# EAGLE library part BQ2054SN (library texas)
CHARGE MANAGEMENT IC

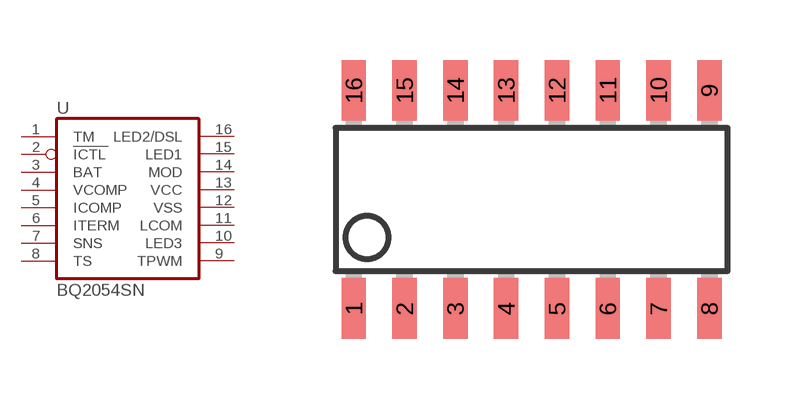
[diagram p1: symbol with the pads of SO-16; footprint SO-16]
Designator prefix U

## BQ2054SN (MF: TEXAS INSTRUMENT CONNECTORS; MPN: BQ2054SN; OC_FARNELL: unknown; OC_NEWARK: 74C7583)  [SO-16]
1  TM  in
2  ICTL  out
3  BAT  in
4  VCOMP  in
5  ICOMP  in
6  ITERM  in
7  SNS  in
8  TS  in
9  TPWM  in
10  LED3  hiz
11  LCOM  out
12  VSS  pwr
13  VCC  pwr
14  MOD  out
15  LED1  hiz
16  LED2/DSL  hiz

## Footprint SO-16 (pad centres in mm)
Small Outline Integrated Circuit
smd 0.61 x 1.524: 1 -4.445,-2.794; 2 -3.175,-2.794; 3 -1.905,-2.794; 4 -0.635,-2.794; 5 0.635,-2.794; 6 1.905,-2.794; 7 3.175,-2.794; 8 4.445,-2.794; 9 4.445,2.667; 10 3.175,2.667; 11 1.905,2.667; 12 0.635,2.667; 13 -0.635,2.667; 14 -1.905,2.667; 15 -3.175,2.667; 16 -4.445,2.667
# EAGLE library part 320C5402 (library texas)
DSP DEVICE

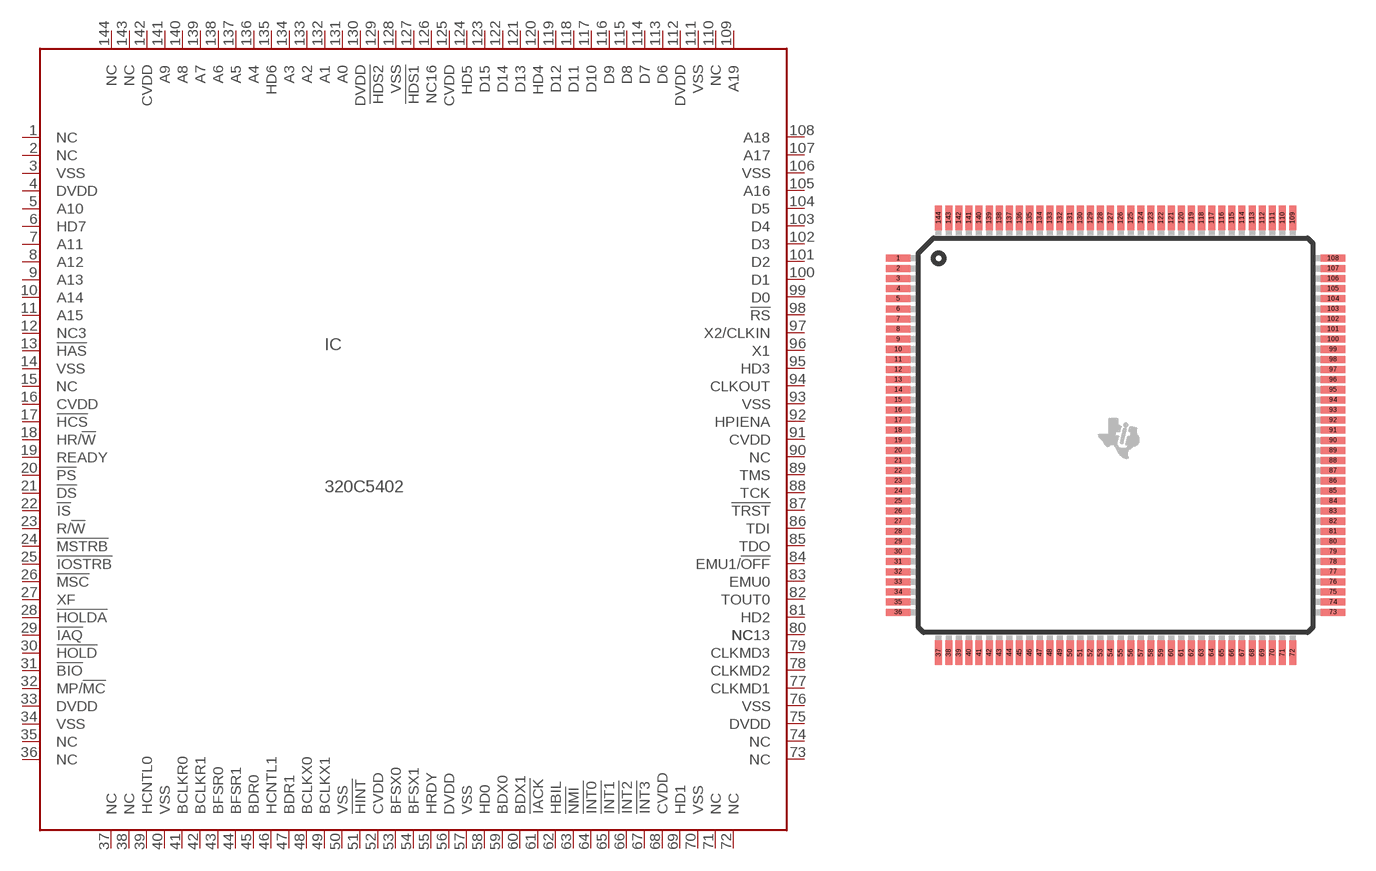
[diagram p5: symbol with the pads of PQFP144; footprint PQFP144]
Designator prefix IC

## 320C5402 (OC_FARNELL: unknown; OC_NEWARK: unknown)  [PQFP144]
1  NC1  nc
2  NC2  nc
3  VSS  pwr
4  DVDD  pwr
5  A10  in
6  HD7  in
7  A11  in
8  A12  in
9  A13  in
10  A14  in
11  A15  in
12  NC3  nc
13  !HAS  in
14  VSS  pwr
15  NC4  nc
16  CVDD  pwr
17  !HCS  in
18  HR/!W  in
19  READY  in
20  !PS  in
21  !DS  in
22  !IS  in
23  R/!W  in
24  !MSTRB  in
25  !IOSTRB  in
26  !MSC  in
27  XF  in
28  !HOLDA  in
29  !IAQ  in
30  !HOLD  in
31  !BIO  in
32  MP/!MC  in
33  DVDD  pwr
34  VSS  pwr
35  NC5  nc
36  NC6  nc
37  NC7  nc
38  NC8  nc
39  HCNTL0  in
40  VSS  pwr
41  BCLKR0  in
42  BCLKR1  in
43  BFSR0  in
44  BFSR1  in
45  BDR0  in
46  HCNTL1  in
47  BDR1  in
48  BCLKX0  in
49  BCLKX1  in
50  VSS  pwr
51  !HINT  in
52  CVDD  pwr
53  BFSX0  in
54  BFSX1  in
55  HRDY  in
56  DVDD  pwr
57  VSS  pwr
58  HD0  in
59  BDX0  in
60  BDX1  in
61  !IACK  in
62  HBIL  in
63  !NMI  in
64  !INT0  in
65  !INT1  in
66  !INT2  in
67  !INT3  in
68  CVDD  pwr
69  HD1  in
70  VSS  pwr
71  NC9  nc
72  NC10  nc
73  NC11  nc
74  NC12  nc
75  DVDD  pwr
76  VSS  pwr
77  CLKMD1  in
78  CLKMD2  in
79  CLKMD3  in
80  NC13  nc
81  HD2  in
82  TOUT0  in
83  EMU0  in
84  EMU1/!OFF  in
85  TDO  in
86  TDI  in
87  !TRST  in
88  TCK  in
89  TMS  in
90  NC14  nc
91  CVDD  pwr
92  HPIENA  in
93  VSS  pwr
94  CLKOUT  in
95  HD3  in
96  X1  in
97  X2/CLKIN  in
98  !RS  in
99  D0  in
100  D1  in
101  D2  in
102  D3  in
103  D4  in
104  D5  in
105  A16  in
106  VSS  pwr
107  A17  in
108  A18  in
109  A19  in
110  NC15  nc
111  VSS  pwr
112  DVDD  pwr
113  D6  in
114  D7  in
115  D8  in
116  D9  in
117  D10  in
118  D11  in
119  D12  in
120  HD4  in
121  D13  in
122  D14  in
123  D15  in
124  HD5  in
125  CVDD  pwr
126  NC16  nc
127  !HDS1  in
128  VSS  pwr
129  !HDS2  in
130  DVDD  pwr
131  A0  in
132  A1  in
133  A2  in
134  A3  in
135  HD6  in
136  A4  in
137  A5  in
138  A6  in
139  A7  in
140  A8  in
141  A9  in
142  CVDD  pwr
143  NC17  nc
144  NC18  nc

## Footprint PQFP144 (pad centres in mm)
Platic Quad Flat Package PGE (S-PQFP-G144)
smd 1.2 x 0.35: 1 -10.75,8.75; 2 -10.75,8.25; 3 -10.75,7.75; 4 -10.75,7.25; 5 -10.75,6.75; 6 -10.75,6.25; 7 -10.75,5.75; 8 -10.75,5.25; 9 -10.75,4.75; 10 -10.75,4.25; 11 -10.75,3.75; 12 -10.75,3.25; 13 -10.75,2.75; 14 -10.75,2.25; 15 -10.75,1.75; 16 -10.75,1.25; 17 -10.75,0.75; 18 -10.75,0.25; 19 -10.75,-0.25; 20 -10.75,-0.75; 21 -10.75,-1.25; 22 -10.75,-1.75; 23 -10.75,-2.25; 24 -10.75,-2.75; 25 -10.75,-3.25; 26 -10.75,-3.75; 27 -10.75,-4.25; 28 -10.75,-4.75; 29 -10.75,-5.25; 30 -10.75,-5.75; 31 -10.75,-6.25; 32 -10.75,-6.75; 33 -10.75,-7.25; 34 -10.75,-7.75; 35 -10.75,-8.25; 36 -10.75,-8.75; 73 10.75,-8.75; 74 10.75,-8.25; 75 10.75,-7.75; 76 10.75,-7.25; 77 10.75,-6.75; 78 10.75,-6.25; 79 10.75,-5.75; 80 10.75,-5.25; 81 10.75,-4.75; 82 10.75,-4.25; 83 10.75,-3.75; 84 10.75,-3.25; 85 10.75,-2.75; 86 10.75,-2.25; 87 10.75,-1.75; 88 10.75,-1.25; 89 10.75,-0.75; 90 10.75,-0.25; 91 10.75,0.25; 92 10.75,0.75; 93 10.75,1.25; 94 10.75,1.75; 95 10.75,2.25; 96 10.75,2.75; 97 10.75,3.25; 98 10.75,3.75; 99 10.75,4.25; 100 10.75,4.75; 101 10.75,5.25; 102 10.75,5.75; 103 10.75,6.25; 104 10.75,6.75; 105 10.75,7.25; 106 10.75,7.75; 107 10.75,8.25; 108 10.75,8.75
smd 0.35 x 1.2: 37 -8.75,-10.75; 38 -8.25,-10.75; 39 -7.75,-10.75; 40 -7.25,-10.75; 41 -6.75,-10.75; 42 -6.25,-10.75; 43 -5.75,-10.75; 44 -5.25,-10.75; 45 -4.75,-10.75; 46 -4.25,-10.75; 47 -3.75,-10.75; 48 -3.25,-10.75; 49 -2.75,-10.75; 50 -2.25,-10.75; 51 -1.75,-10.75; 52 -1.25,-10.75; 53 -0.75,-10.75; 54 -0.25,-10.75; 55 0.25,-10.75; 56 0.75,-10.75; 57 1.25,-10.75; 58 1.75,-10.75; 59 2.25,-10.75; 60 2.75,-10.75; 61 3.25,-10.75; 62 3.75,-10.75; 63 4.25,-10.75; 64 4.75,-10.75; 65 5.25,-10.75; 66 5.75,-10.75; 67 6.25,-10.75; 68 6.75,-10.75; 69 7.25,-10.75; 70 7.75,-10.75; 71 8.25,-10.75; 72 8.75,-10.75; 109 8.75,10.75; 110 8.25,10.75; 111 7.75,10.75; 112 7.25,10.75; 113 6.75,10.75; 114 6.25,10.75; 115 5.75,10.75; 116 5.25,10.75; 117 4.75,10.75; 118 4.25,10.75; 119 3.75,10.75; 120 3.25,10.75; 121 2.75,10.75; 122 2.25,10.75; 123 1.75,10.75; 124 1.25,10.75; 125 0.75,10.75; 126 0.25,10.75; 127 -0.25,10.75; 128 -0.75,10.75; 129 -1.25,10.75; 130 -1.75,10.75; 131 -2.25,10.75; 132 -2.75,10.75; 133 -3.25,10.75; 134 -3.75,10.75; 135 -4.25,10.75; 136 -4.75,10.75; 137 -5.25,10.75; 138 -5.75,10.75; 139 -6.25,10.75; 140 -6.75,10.75; 141 -7.25,10.75; 142 -7.75,10.75; 143 -8.25,10.75; 144 -8.75,10.75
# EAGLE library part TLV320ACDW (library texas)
DSP DEVICE

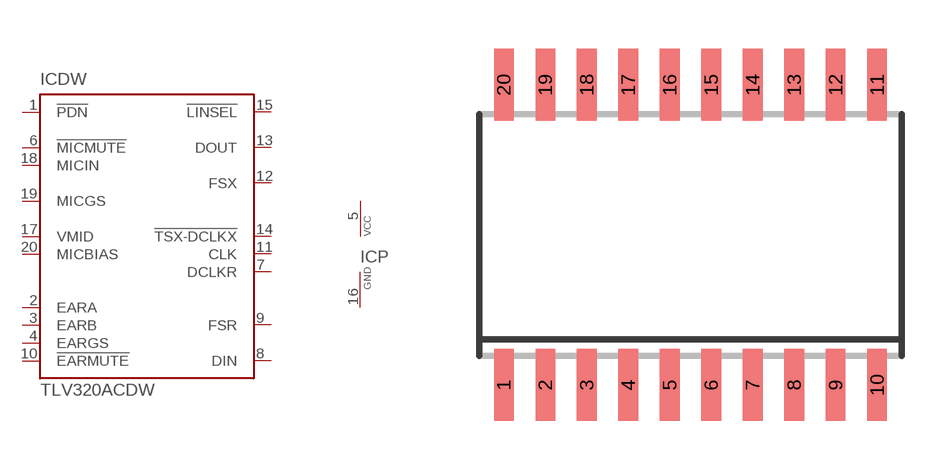
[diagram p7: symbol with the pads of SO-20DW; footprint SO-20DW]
Designator prefix IC; gates DW=TLV320AC P=VCCGND

## TLV320ACDW (OC_FARNELL: unknown; OC_NEWARK: unknown)  [SO-20DW]
1  DW:!PDN  in
2  DW:EARA  out
3  DW:EARB  out
4  DW:EARGS  in
5  P:VCC  pwr
6  DW:!MICMUTE  in
7  DW:DCLKR  in
8  DW:DIN  in
9  DW:FSR  in
10  DW:!EARMUTE  in
11  DW:CLK  in
12  DW:FSX  in
13  DW:DOUT  out
14  DW:!TSX-DCLKX
15  DW:!LINSEL  in
16  P:GND  pwr
17  DW:VMID  out
18  DW:MICIN  in
19  DW:MICGS  out
20  DW:MICBIAS  out

## Footprint SO-20DW (pad centres in mm)
Small Outline Integrated Circuit wide
smd 0.6 x 2.2: 1 -5.715,-4.6; 2 -4.445,-4.6; 3 -3.175,-4.6; 4 -1.905,-4.6; 5 -0.635,-4.6; 6 0.635,-4.6; 7 1.905,-4.6; 8 3.175,-4.6; 9 4.445,-4.6; 10 5.715,-4.6; 11 5.715,4.6; 12 4.445,4.6; 13 3.175,4.6; 14 1.905,4.6; 15 0.635,4.6; 16 -0.635,4.6; 17 -1.905,4.6; 18 -3.175,4.6; 19 -4.445,4.6; 20 -5.715,4.6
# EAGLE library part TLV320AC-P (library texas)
DSP DEVICE

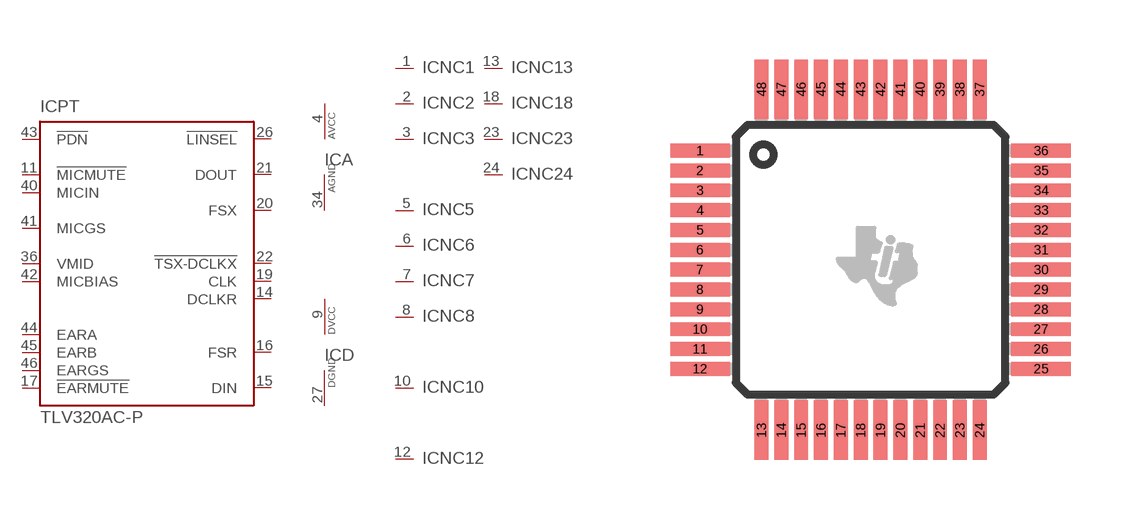
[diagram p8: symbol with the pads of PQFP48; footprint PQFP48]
Designator prefix IC; gates PT=TLV320AC A=AVCCGND D=DVCCGND NC1=NC NC2=NC NC3=NC NC5=NC NC6=NC NC7=NC NC8=NC NC10=NC NC12=NC NC13=NC NC18=NC NC23=NC NC24=NC NC25=NC NC28=NC NC29=NC NC30=NC NC31=NC NC32=NC NC33=NC NC35=NC NC37=NC NC38=NC NC39=NC NC47=NC NC48=NC

## TLV320AC-P (OC_FARNELL: unknown; OC_NEWARK: unknown)  [PQFP48]
1  NC1:NC  nc
2  NC2:NC  nc
3  NC3:NC  nc
4  A:AVCC  pwr
5  NC5:NC  nc
6  NC6:NC  nc
7  NC7:NC  nc
8  NC8:NC  nc
9  D:DVCC  pwr
10  NC10:NC  nc
11  PT:!MICMUTE  in
12  NC12:NC  nc
13  NC13:NC  nc
14  PT:DCLKR  in
15  PT:DIN  in
16  PT:FSR  in
17  PT:!EARMUTE  in
18  NC18:NC  nc
19  PT:CLK  in
20  PT:FSX  in
21  PT:DOUT  out
22  PT:!TSX-DCLKX
23  NC23:NC  nc
24  NC24:NC  nc
25  NC25:NC  nc
26  PT:!LINSEL  in
27  D:DGND  pwr
28  NC28:NC  nc
29  NC29:NC  nc
30  NC30:NC  nc
31  NC31:NC  nc
32  NC32:NC  nc
33  NC33:NC  nc
34  A:AGND  pwr
35  NC35:NC  nc
36  PT:VMID  out
37  NC37:NC  nc
38  NC38:NC  nc
39  NC39:NC  nc
40  PT:MICIN  in
41  PT:MICGS  out
42  PT:MICBIAS  out
43  PT:!PDN  in
44  PT:EARA  out
45  PT:EARB  out
46  PT:EARGS  in
47  NC47:NC  nc
48  NC48:NC  nc

## Footprint PQFP48 (pad centres in mm)
Platic Quad Flat Package
smd 1.5 x 0.35: 1 -4.3,2.75; 2 -4.3,2.25; 3 -4.3,1.75; 4 -4.3,1.25; 5 -4.3,0.75; 6 -4.3,0.25; 7 -4.3,-0.25; 8 -4.3,-0.75; 9 -4.3,-1.25; 10 -4.3,-1.75; 11 -4.3,-2.25; 12 -4.3,-2.75; 25 4.3,-2.75; 26 4.3,-2.25; 27 4.3,-1.75; 28 4.3,-1.25; 29 4.3,-0.75; 30 4.3,-0.25; 31 4.3,0.25; 32 4.3,0.75; 33 4.3,1.25; 34 4.3,1.75; 35 4.3,2.25; 36 4.3,2.75
smd 0.35 x 1.5: 13 -2.75,-4.3; 14 -2.25,-4.3; 15 -1.75,-4.3; 16 -1.25,-4.3; 17 -0.75,-4.3; 18 -0.25,-4.3; 19 0.25,-4.3; 20 0.75,-4.3; 21 1.25,-4.3; 22 1.75,-4.3; 23 2.25,-4.3; 24 2.75,-4.3; 37 2.75,4.3; 38 2.25,4.3; 39 1.75,4.3; 40 1.25,4.3; 41 0.75,4.3; 42 0.25,4.3; 43 -0.25,4.3; 44 -0.75,4.3; 45 -1.25,4.3; 46 -1.75,4.3; 47 -2.25,4.3; 48 -2.75,4.3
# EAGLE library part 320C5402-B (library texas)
DSP DEVICE

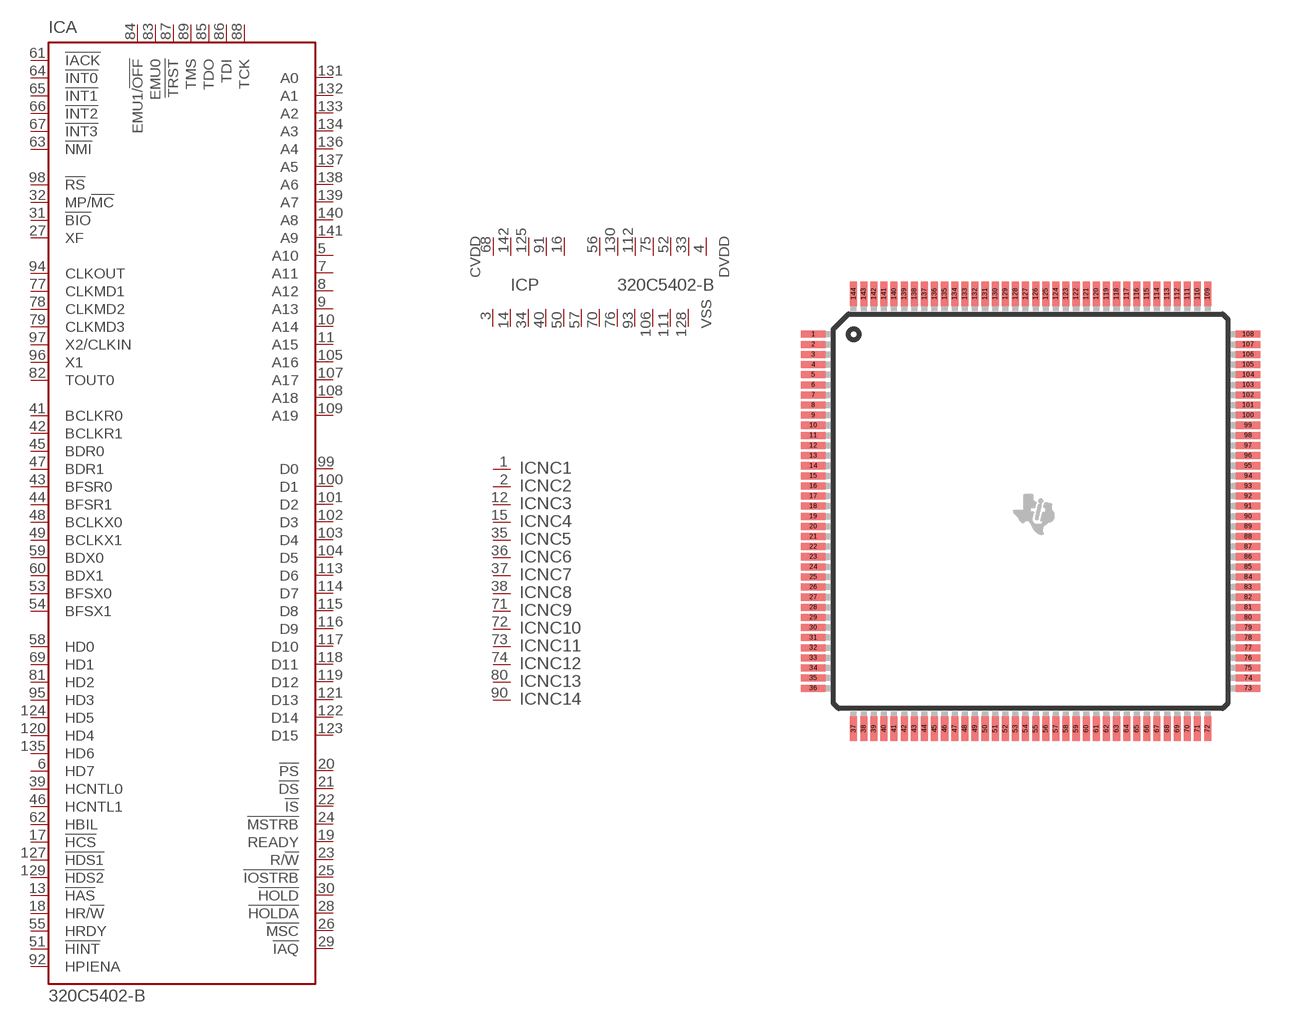
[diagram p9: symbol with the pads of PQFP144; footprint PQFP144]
Designator prefix IC; gates A=320C54-B P=320PWR NC1=NC NC2=NC NC3=NC NC4=NC NC5=NC NC6=NC NC7=NC NC8=NC NC9=NC NC10=NC NC11=NC NC12=NC NC13=NC NC14=NC NC15=NC NC16=NC NC17=NC NC18=NC

## 320C5402-B (OC_FARNELL: unknown; OC_NEWARK: unknown)  [PQFP144]
1  NC1:NC  nc
2  NC2:NC  nc
3  P:VSS  pwr
4  P:DVDD  pwr
5  A:A10  hiz
6  A:HD7  hiz
7  A:A11  hiz
8  A:A12  hiz
9  A:A13  hiz
10  A:A14  hiz
11  A:A15  hiz
12  NC3:NC  nc
13  A:!HAS  in
14  P:VSS  pwr
15  NC4:NC  nc
16  P:CVDD  pwr
17  A:!HCS  in
18  A:HR/!W  in
19  A:READY  in
20  A:!PS  hiz
21  A:!DS  hiz
22  A:!IS  hiz
23  A:R/!W  hiz
24  A:!MSTRB  hiz
25  A:!IOSTRB  hiz
26  A:!MSC  hiz
27  A:XF  hiz
28  A:!HOLDA  hiz
29  A:!IAQ  hiz
30  A:!HOLD  in
31  A:!BIO  in
32  A:MP/!MC  in
33  P:DVDD  pwr
34  P:VSS  pwr
35  NC5:NC  nc
36  NC6:NC  nc
37  NC7:NC  nc
38  NC8:NC  nc
39  A:HCNTL0  in
40  P:VSS  pwr
41  A:BCLKR0  hiz
42  A:BCLKR1  hiz
43  A:BFSR0  hiz
44  A:BFSR1  hiz
45  A:BDR0  in
46  A:HCNTL1  in
47  A:BDR1  in
48  A:BCLKX0  hiz
49  A:BCLKX1  hiz
50  P:VSS  pwr
51  A:!HINT  hiz
52  P:CVDD  pwr
53  A:BFSX0  hiz
54  A:BFSX1  hiz
55  A:HRDY  hiz
56  P:DVDD  pwr
57  P:VSS  pwr
58  A:HD0  hiz
59  A:BDX0  hiz
60  A:BDX1  hiz
61  A:!IACK  hiz
62  A:HBIL  in
63  A:!NMI  in
64  A:!INT0  in
65  A:!INT1  in
66  A:!INT2  in
67  A:!INT3  in
68  P:CVDD  pwr
69  A:HD1  hiz
70  P:VSS  pwr
71  NC9:NC  nc
72  NC10:NC  nc
73  NC11:NC  nc
74  NC12:NC  nc
75  P:DVDD  pwr
76  P:VSS  pwr
77  A:CLKMD1  in
78  A:CLKMD2  in
79  A:CLKMD3  in
80  NC13:NC  nc
81  A:HD2  hiz
82  A:TOUT0  hiz
83  A:EMU0  hiz
84  A:EMU1/!OFF  hiz
85  A:TDO  hiz
86  A:TDI  in
87  A:!TRST  in
88  A:TCK  in
89  A:TMS  in
90  NC14:NC  nc
91  P:CVDD  pwr
92  A:HPIENA  in
93  P:VSS  pwr
94  A:CLKOUT  hiz
95  A:HD3  hiz
96  A:X1  out
97  A:X2/CLKIN  in
98  A:!RS  in
99  A:D0  hiz
100  A:D1  hiz
101  A:D2  hiz
102  A:D3  hiz
103  A:D4  hiz
104  A:D5  hiz
105  A:A16  hiz
106  P:VSS  pwr
107  A:A17  hiz
108  A:A18  hiz
109  A:A19  hiz
110  NC15:NC  nc
111  P:VSS  pwr
112  P:DVDD  pwr
113  A:D6  hiz
114  A:D7  hiz
115  A:D8  hiz
116  A:D9  hiz
117  A:D10  hiz
118  A:D11  hiz
119  A:D12  hiz
120  A:HD4  hiz
121  A:D13  hiz
122  A:D14  hiz
123  A:D15  hiz
124  A:HD5  hiz
125  P:CVDD  pwr
126  NC16:NC  nc
127  A:!HDS1  in
128  P:VSS  pwr
129  A:!HDS2  in
130  P:DVDD  pwr
131  A:A0  hiz
132  A:A1  hiz
133  A:A2  hiz
134  A:A3  hiz
135  A:HD6  hiz
136  A:A4  hiz
137  A:A5  hiz
138  A:A6  hiz
139  A:A7  hiz
140  A:A8  hiz
141  A:A9  hiz
142  P:CVDD  pwr
143  NC17:NC  nc
144  NC18:NC  nc

## Footprint PQFP144 (pad centres in mm)
Platic Quad Flat Package PGE (S-PQFP-G144)
smd 1.2 x 0.35: 1 -10.75,8.75; 2 -10.75,8.25; 3 -10.75,7.75; 4 -10.75,7.25; 5 -10.75,6.75; 6 -10.75,6.25; 7 -10.75,5.75; 8 -10.75,5.25; 9 -10.75,4.75; 10 -10.75,4.25; 11 -10.75,3.75; 12 -10.75,3.25; 13 -10.75,2.75; 14 -10.75,2.25; 15 -10.75,1.75; 16 -10.75,1.25; 17 -10.75,0.75; 18 -10.75,0.25; 19 -10.75,-0.25; 20 -10.75,-0.75; 21 -10.75,-1.25; 22 -10.75,-1.75; 23 -10.75,-2.25; 24 -10.75,-2.75; 25 -10.75,-3.25; 26 -10.75,-3.75; 27 -10.75,-4.25; 28 -10.75,-4.75; 29 -10.75,-5.25; 30 -10.75,-5.75; 31 -10.75,-6.25; 32 -10.75,-6.75; 33 -10.75,-7.25; 34 -10.75,-7.75; 35 -10.75,-8.25; 36 -10.75,-8.75; 73 10.75,-8.75; 74 10.75,-8.25; 75 10.75,-7.75; 76 10.75,-7.25; 77 10.75,-6.75; 78 10.75,-6.25; 79 10.75,-5.75; 80 10.75,-5.25; 81 10.75,-4.75; 82 10.75,-4.25; 83 10.75,-3.75; 84 10.75,-3.25; 85 10.75,-2.75; 86 10.75,-2.25; 87 10.75,-1.75; 88 10.75,-1.25; 89 10.75,-0.75; 90 10.75,-0.25; 91 10.75,0.25; 92 10.75,0.75; 93 10.75,1.25; 94 10.75,1.75; 95 10.75,2.25; 96 10.75,2.75; 97 10.75,3.25; 98 10.75,3.75; 99 10.75,4.25; 100 10.75,4.75; 101 10.75,5.25; 102 10.75,5.75; 103 10.75,6.25; 104 10.75,6.75; 105 10.75,7.25; 106 10.75,7.75; 107 10.75,8.25; 108 10.75,8.75
smd 0.35 x 1.2: 37 -8.75,-10.75; 38 -8.25,-10.75; 39 -7.75,-10.75; 40 -7.25,-10.75; 41 -6.75,-10.75; 42 -6.25,-10.75; 43 -5.75,-10.75; 44 -5.25,-10.75; 45 -4.75,-10.75; 46 -4.25,-10.75; 47 -3.75,-10.75; 48 -3.25,-10.75; 49 -2.75,-10.75; 50 -2.25,-10.75; 51 -1.75,-10.75; 52 -1.25,-10.75; 53 -0.75,-10.75; 54 -0.25,-10.75; 55 0.25,-10.75; 56 0.75,-10.75; 57 1.25,-10.75; 58 1.75,-10.75; 59 2.25,-10.75; 60 2.75,-10.75; 61 3.25,-10.75; 62 3.75,-10.75; 63 4.25,-10.75; 64 4.75,-10.75; 65 5.25,-10.75; 66 5.75,-10.75; 67 6.25,-10.75; 68 6.75,-10.75; 69 7.25,-10.75; 70 7.75,-10.75; 71 8.25,-10.75; 72 8.75,-10.75; 109 8.75,10.75; 110 8.25,10.75; 111 7.75,10.75; 112 7.25,10.75; 113 6.75,10.75; 114 6.25,10.75; 115 5.75,10.75; 116 5.25,10.75; 117 4.75,10.75; 118 4.25,10.75; 119 3.75,10.75; 120 3.25,10.75; 121 2.75,10.75; 122 2.25,10.75; 123 1.75,10.75; 124 1.25,10.75; 125 0.75,10.75; 126 0.25,10.75; 127 -0.25,10.75; 128 -0.75,10.75; 129 -1.25,10.75; 130 -1.75,10.75; 131 -2.25,10.75; 132 -2.75,10.75; 133 -3.25,10.75; 134 -3.75,10.75; 135 -4.25,10.75; 136 -4.75,10.75; 137 -5.25,10.75; 138 -5.75,10.75; 139 -6.25,10.75; 140 -6.75,10.75; 141 -7.25,10.75; 142 -7.75,10.75; 143 -8.25,10.75; 144 -8.75,10.75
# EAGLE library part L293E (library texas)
TI DEVICE

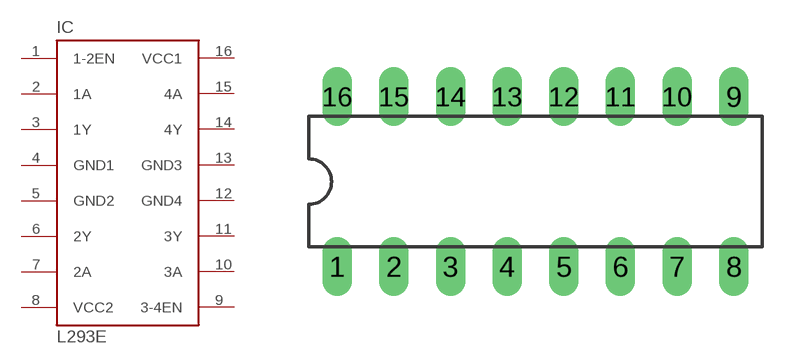
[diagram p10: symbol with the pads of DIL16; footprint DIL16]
Designator prefix IC

## L293E (MF: Arrow Electronics; MPN: L293E; OC_FARNELL: 1467711; OC_NEWARK: 89K0732)  [DIL16]
1  1-2EN  in
2  1A  in
3  1Y  out
4  GND1  pwr
5  GND2  pwr
6  2Y  out
7  2A  in
8  VCC2  pwr
9  3-4EN  in
10  3A  in
11  3Y  out
12  GND4  pwr
13  GND3  pwr
14  4Y  out
15  4A  in
16  VCC1  pwr

## Footprint DIL16 (pad centres in mm)
Dual In Line Package
drill 0.813 long: 1 -8.89,-3.81; 2 -6.35,-3.81; 3 -3.81,-3.81; 4 -1.27,-3.81; 5 1.27,-3.81; 6 3.81,-3.81; 7 6.35,-3.81; 8 8.89,-3.81; 9 8.89,3.81; 10 6.35,3.81; 11 3.81,3.81; 12 1.27,3.81; 13 -1.27,3.81; 14 -3.81,3.81; 15 -6.35,3.81; 16 -8.89,3.81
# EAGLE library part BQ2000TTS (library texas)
CHARGE MANAGEMENT IC

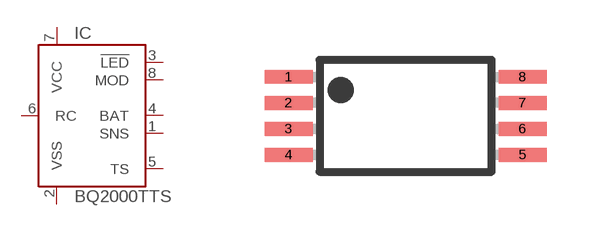
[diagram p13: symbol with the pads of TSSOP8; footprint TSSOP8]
Designator prefix IC

## BQ2000TTS (OC_FARNELL: unknown; OC_NEWARK: unknown)  [TSSOP8]
1  SNS  in
2  VSS  pwr
3  !LED  out
4  BAT  in
5  TS  in
6  RC  in
7  VCC  in
8  MOD  out

## Footprint TSSOP8 (pad centres in mm)
Plastic Small Outline
smd 1.2 x 0.35: 1 -2.925,0.975; 2 -2.925,0.325; 3 -2.925,-0.325; 4 -2.925,-0.975; 5 2.925,-0.975; 6 2.925,-0.325; 7 2.925,0.325; 8 2.925,0.975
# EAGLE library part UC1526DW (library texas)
PULSE WIDTH MODULATOR

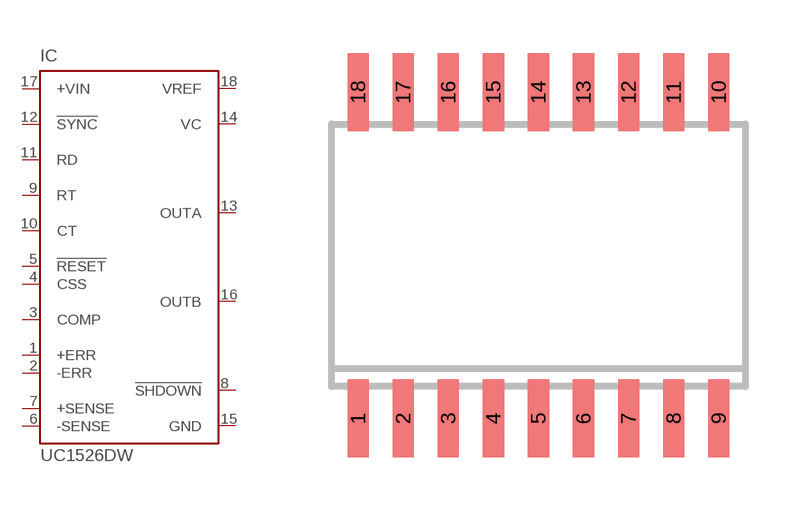
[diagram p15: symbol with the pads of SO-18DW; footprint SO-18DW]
Designator prefix IC

## UC1526DW (OC_FARNELL: unknown; OC_NEWARK: unknown)  [SO-18DW]
1  +ERR  in
2  -ERR  in
3  COMP  pas
4  CSS  in
5  !RESET  in
6  -SENSE  in
7  +SENSE  in
8  !SHDOWN  out
9  RT  pas
10  CT  pas
11  RD  pas
12  !SYNC  in
13  OUTA  out
14  VC  in
15  GND  pwr
16  OUTB  out
17  +VIN  in
18  VREF  out

## Footprint SO-18DW (pad centres in mm)
Small Outline Integrated Circuit wide
smd 0.6 x 2.2: 1 -5.08,-4.6; 2 -3.81,-4.6; 3 -2.54,-4.6; 4 -1.27,-4.6; 5 0,-4.6; 6 1.27,-4.6; 7 2.54,-4.6; 8 3.81,-4.6; 9 5.08,-4.6; 10 5.08,4.6; 11 3.81,4.6; 12 2.54,4.6; 13 1.27,4.6; 14 0,4.6; 15 -1.27,4.6; 16 -2.54,4.6; 17 -3.81,4.6; 18 -5.08,4.6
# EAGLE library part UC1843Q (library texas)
PULSE WIDTH MODULATOR

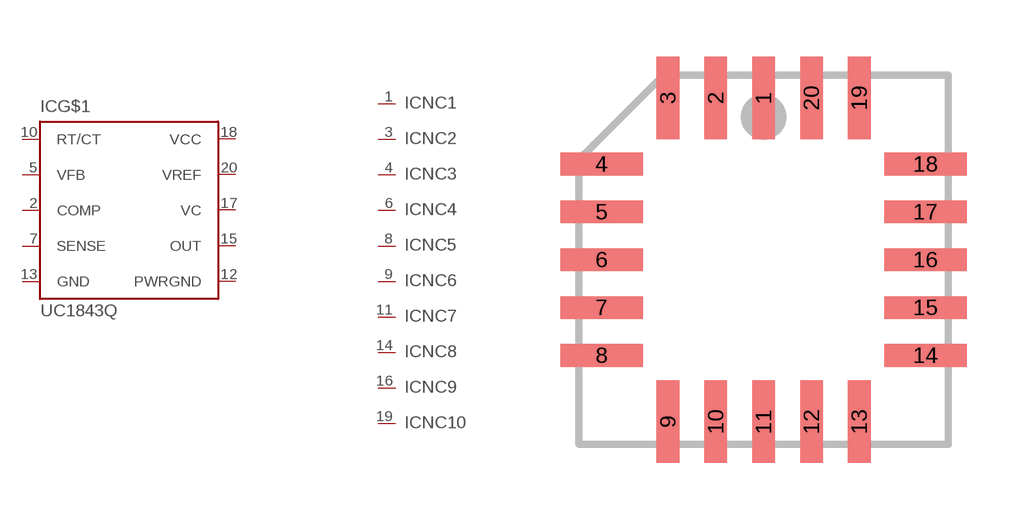
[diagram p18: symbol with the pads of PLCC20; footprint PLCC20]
Designator prefix IC; gates G$1=UC1843 NC1=NC NC2=NC NC3=NC NC4=NC NC5=NC NC6=NC NC7=NC NC8=NC NC9=NC NC10=NC

## UC1843Q (OC_FARNELL: unknown; OC_NEWARK: unknown)  [PLCC20]
1  NC1:NC  nc
2  G$1:COMP  pas
3  NC2:NC  nc
4  NC3:NC  nc
5  G$1:VFB  in
6  NC4:NC  nc
7  G$1:SENSE  in
8  NC5:NC  nc
9  NC6:NC  nc
10  G$1:RT/CT  pas
11  NC7:NC  nc
12  G$1:PWRGND  pwr
13  G$1:GND  pwr
14  NC8:NC  nc
15  G$1:OUT  out
16  NC9:NC  nc
17  G$1:VC  in
18  G$1:VCC  pwr
19  NC10:NC  nc
20  G$1:VREF  out

## Footprint PLCC20 (pad centres in mm)
Plastic Leaded Chip Carrier
smd 0.6 x 2.2: 1 0,4.3; 2 -1.27,4.3; 3 -2.54,4.3; 9 -2.54,-4.3; 10 -1.27,-4.3; 11 0,-4.3; 12 1.27,-4.3; 13 2.54,-4.3; 19 2.54,4.3; 20 1.27,4.3
smd 2.2 x 0.6: 4 -4.3,2.54; 5 -4.3,1.27; 6 -4.3,0; 7 -4.3,-1.27; 8 -4.3,-2.54; 14 4.3,-2.54; 15 4.3,-1.27; 16 4.3,0; 17 4.3,1.27; 18 4.3,2.54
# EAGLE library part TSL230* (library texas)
PROGRAMMABLE LIGHT TO FREQUENCY CONVERTER

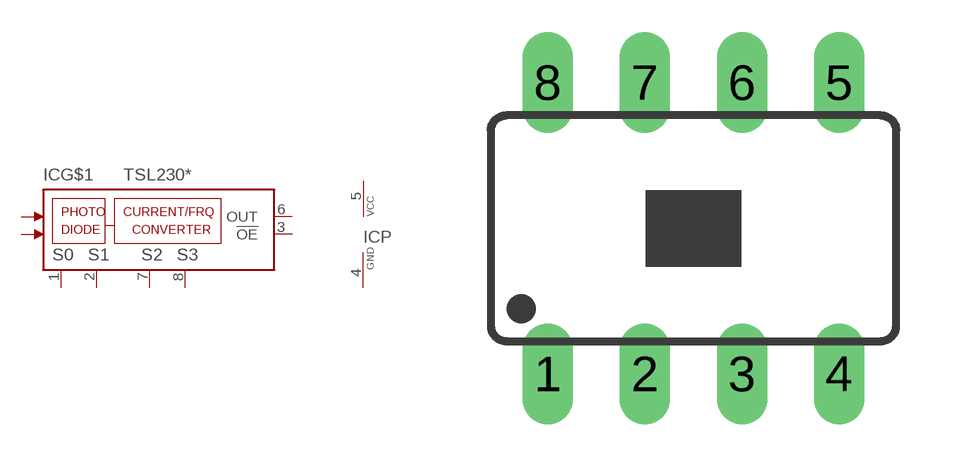
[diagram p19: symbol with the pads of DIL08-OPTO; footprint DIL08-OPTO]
Designator prefix IC; gates G$1=TSL230 P=VCCGND

## TSL230 (MPN: TSL230RP-LF; OC_FARNELL: 1182355; OC_NEWARK: 24M8654), TSL230A (OC_FARNELL: unknown; OC_NEWARK: unknown), TSL230B (OC_FARNELL: unknown; OC_NEWARK: unknown)  [DIL08-OPTO]
1  G$1:S0  in
2  G$1:S1  in
3  G$1:!OE  in
4  P:GND  pwr
5  P:VCC  pwr
6  G$1:OUT  out
7  G$1:S2  in
8  G$1:S3  in

## Footprint DIL08-OPTO (pad centres in mm)
Dula In Line This dual-in-line package consists of an integrated circuit mounted on a lead frame and encapsulated with an electrically nonconductive clear plastic compound. The photodiode area is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
drill 0.813 long: 1 -3.81,-3.81; 2 -1.27,-3.81; 3 1.27,-3.81; 4 3.81,-3.81; 5 3.81,3.81; 6 1.27,3.81; 7 -1.27,3.81; 8 -3.81,3.81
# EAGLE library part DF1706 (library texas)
Stereo, 24-Bit, 192kHz 8x Oversampling Digital Interpolation Filter www.ti.com df1706.pdf

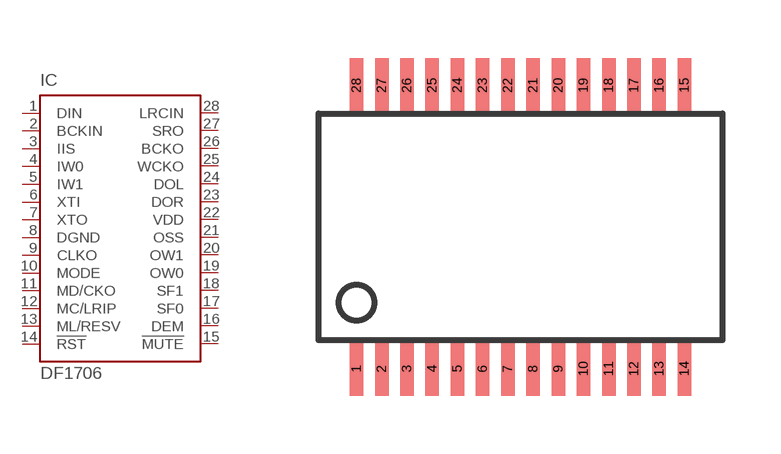
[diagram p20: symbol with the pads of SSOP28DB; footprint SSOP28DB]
Designator prefix IC

## DF1706 (MPN: DF1706EG4; OC_FARNELL: unknown; OC_NEWARK: 66K1929)  [SSOP28DB]
1  DIN  in
2  BCKIN  in
3  IIS  in
4  IW0  in
5  IW1  in
6  XTI  in
7  XTO  out
8  DGND  pwr
9  CLKO  out
10  MODE  in
11  MD/CKO  in
12  MC/LRIP  in
13  ML/RESV  in
14  !RST  in
15  !MUTE  in
16  DEM  in
17  SF0  in
18  SF1  in
19  OW0  in
20  OW1  in
21  OSS  in
22  VDD  pwr
23  DOR  out
24  DOL  out
25  WCKO  out
26  BCKO  out
27  SRO  in
28  LRCIN  in

## Footprint SSOP28DB (pad centres in mm)
Small Shrink Outline Package
smd 0.348 x 1.397: 1 -4.225,-3.656; 2 -3.575,-3.656; 3 -2.925,-3.656; 4 -2.275,-3.656; 5 -1.625,-3.656; 6 -0.975,-3.656; 7 -0.325,-3.656; 8 0.325,-3.656; 9 0.975,-3.656; 10 1.625,-3.656; 11 2.275,-3.656; 12 2.925,-3.656; 13 3.575,-3.656; 14 4.225,-3.656; 15 4.225,3.656; 16 3.575,3.656; 17 2.925,3.656; 18 2.275,3.656; 19 1.625,3.656; 20 0.975,3.656; 21 0.325,3.656; 22 -0.325,3.656; 23 -0.975,3.656; 24 -1.625,3.656; 25 -2.275,3.656; 26 -2.925,3.656; 27 -3.575,3.656; 28 -4.225,3.656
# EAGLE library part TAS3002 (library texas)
Digital Audio Processor with Codec www.ti.com; tas3002.pdf

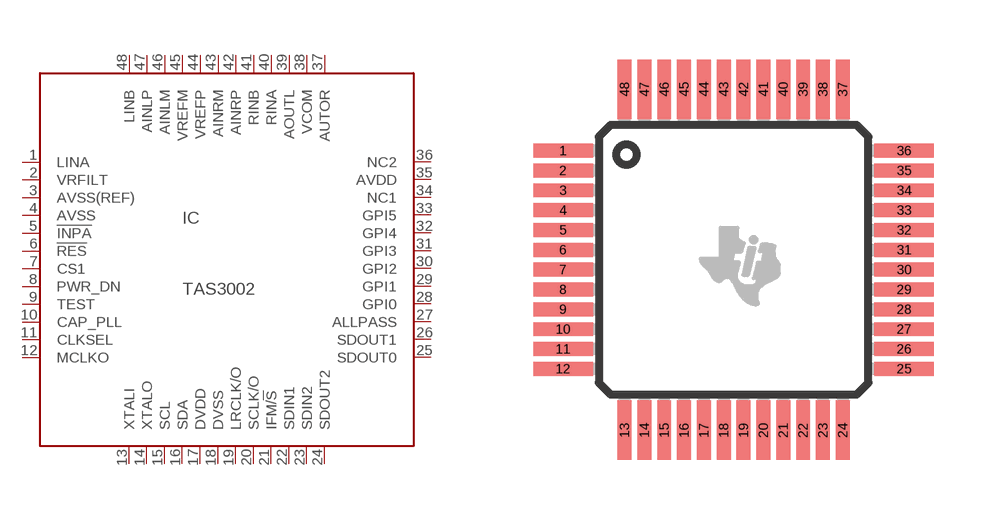
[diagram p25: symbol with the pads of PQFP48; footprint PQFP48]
Designator prefix IC

## TAS3002 (MF: TEXAS INSTRUMENTS; MPN: TAS3002PFB; OC_FARNELL: unknown; OC_NEWARK: 76C5960)  [PQFP48]
1  LINA  in
2  VRFILT  out
3  AVSS(REF)  pwr
4  AVSS  pwr
5  !INPA  out
6  !RES  in
7  CS1  in
8  PWR_DN  in
9  TEST  in
10  CAP_PLL  in
11  CLKSEL  in
12  MCLKO  out
13  XTALI  in
14  XTALO  in
15  SCL
16  SDA
17  DVDD  pwr
18  DVSS  pwr
19  LRCLK/O
20  SCLK/O
21  IFM/!S  in
22  SDIN1  in
23  SDIN2  in
24  SDOUT2  out
25  SDOUT0  out
26  SDOUT1  out
27  ALLPASS  in
28  GPI0  in
29  GPI1  in
30  GPI2  in
31  GPI3  in
32  GPI4  in
33  GPI5  in
34  NC1  in
35  AVDD  pwr
36  NC2  in
37  AUTOR  out
38  VCOM  pwr
39  AOUTL  out
40  RINA  in
41  RINB  in
42  AINRP  in
43  AINRM  in
44  VREFP  in
45  VREFM  in
46  AINLM  in
47  AINLP  in
48  LINB  in

## Footprint PQFP48 (pad centres in mm)
Platic Quad Flat Package
smd 1.5 x 0.35: 1 -4.3,2.75; 2 -4.3,2.25; 3 -4.3,1.75; 4 -4.3,1.25; 5 -4.3,0.75; 6 -4.3,0.25; 7 -4.3,-0.25; 8 -4.3,-0.75; 9 -4.3,-1.25; 10 -4.3,-1.75; 11 -4.3,-2.25; 12 -4.3,-2.75; 25 4.3,-2.75; 26 4.3,-2.25; 27 4.3,-1.75; 28 4.3,-1.25; 29 4.3,-0.75; 30 4.3,-0.25; 31 4.3,0.25; 32 4.3,0.75; 33 4.3,1.25; 34 4.3,1.75; 35 4.3,2.25; 36 4.3,2.75
smd 0.35 x 1.5: 13 -2.75,-4.3; 14 -2.25,-4.3; 15 -1.75,-4.3; 16 -1.25,-4.3; 17 -0.75,-4.3; 18 -0.25,-4.3; 19 0.25,-4.3; 20 0.75,-4.3; 21 1.25,-4.3; 22 1.75,-4.3; 23 2.25,-4.3; 24 2.75,-4.3; 37 2.75,4.3; 38 2.25,4.3; 39 1.75,4.3; 40 1.25,4.3; 41 0.75,4.3; 42 0.25,4.3; 43 -0.25,4.3; 44 -0.75,4.3; 45 -1.25,4.3; 46 -1.75,4.3; 47 -2.25,4.3; 48 -2.75,4.3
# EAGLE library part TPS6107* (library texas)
90% EFFICIENT SYNCHRONOUS BOOST CONVERTER WITH 600-mA SWITCH Source: http://focus.ti.com/lit/ds/symlink/tps61070.pdf

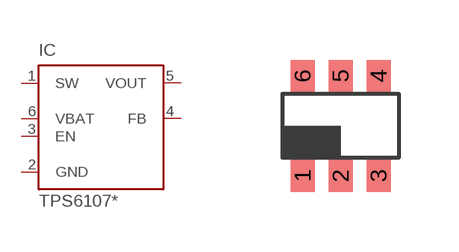
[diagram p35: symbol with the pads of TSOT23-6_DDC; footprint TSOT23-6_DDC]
Designator prefix IC

## TPS61070DDC (MPN: TPS61070DDCR; OC_FARNELL: 1461062; OC_NEWARK: 64M3125), TPS61071DDC (MF: TEXAS INSTRUMENT CONNECTORS; MPN: TPS61071DDCR; OC_FARNELL: 1412515; OC_NEWARK: 21J9232), TPS61072DDC (MPN: TPS61072DDCR; OC_FARNELL: unknown; OC_NEWARK: 30M1829), TPS61073DDC (MPN: TPS61073DDCRG4; OC_FARNELL: 1755459; OC_NEWARK: 52M6122)  [TSOT23-6_DDC]
1  SW  in
2  GND  pwr
3  EN  in
4  FB  in
5  VOUT  pas
6  VBAT  in

## Footprint TSOT23-6_DDC (pad centres in mm)
DDC (R-PDSO-G6) PLASTIC SMALL OUTLINE PACKAGE Source: http://focus.ti.com/lit/ds/symlink/tps61070.pdf
smd 0.6 x 0.8: 1 -0.95,-1.25; 2 0,-1.25; 3 0.95,-1.25; 4 0.95,1.25; 5 0,1.25; 6 -0.95,1.25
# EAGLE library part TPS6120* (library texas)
LOW INPUT VOLTAGE SYNCHRONOUS BOOST CONVERTER WITH 1.3-A SWITCHES Source: http://focus.ti.com/lit/ds/symlink/tps61200.pdf

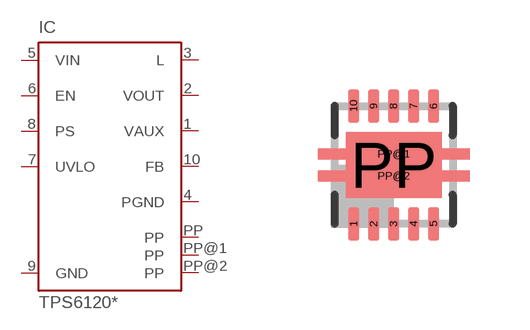
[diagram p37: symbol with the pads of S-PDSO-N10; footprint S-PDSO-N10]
Designator prefix IC

## TPS61200 (MPN: TPS61200DRCT; OC_FARNELL: 1471238; OC_NEWARK: 37M0066), TPS61201 (MPN: TPS61201DRCT; OC_FARNELL: unknown; OC_NEWARK: 37M0068), TPS61202 (MPN: TPS61202DRCR; OC_FARNELL: unknown; OC_NEWARK: 37M0069)  [S-PDSO-N10]
1  VAUX
2  VOUT  pas
3  L  in
4  PGND  pwr
5  VIN  in
6  EN  in
7  UVLO  in
8  PS  in
9  GND  pwr
10  FB  in
PP  PP  pwr
PP@1  PP  pwr
PP@2  PP  pwr

## Footprint S-PDSO-N10 (pad centres in mm)
QFN 10 3 x 3 mm Source: http://focus.ti.com/lit/ds/symlink/tps61200.pdf
smd 0.28 x 0.85: 1 -1,-1.475; 2 -0.5,-1.475; 3 0,-1.475; 4 0.5,-1.475; 5 1,-1.475; 6 1,1.475; 7 0.5,1.475; 8 0,1.475; 9 -0.5,1.475; 10 -1,1.475
smd 2.4 x 1.65: PP 0,0
smd 3.8 x 0.28: PP@1 0,0.275; PP@2 0,-0.275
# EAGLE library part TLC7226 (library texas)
QUADRUPLE 8-BIT DIGITAL-TO-ANALOG CONVERTERS Source: http://focus.ti.com/lit/ds/symlink/tlc7226.pdf

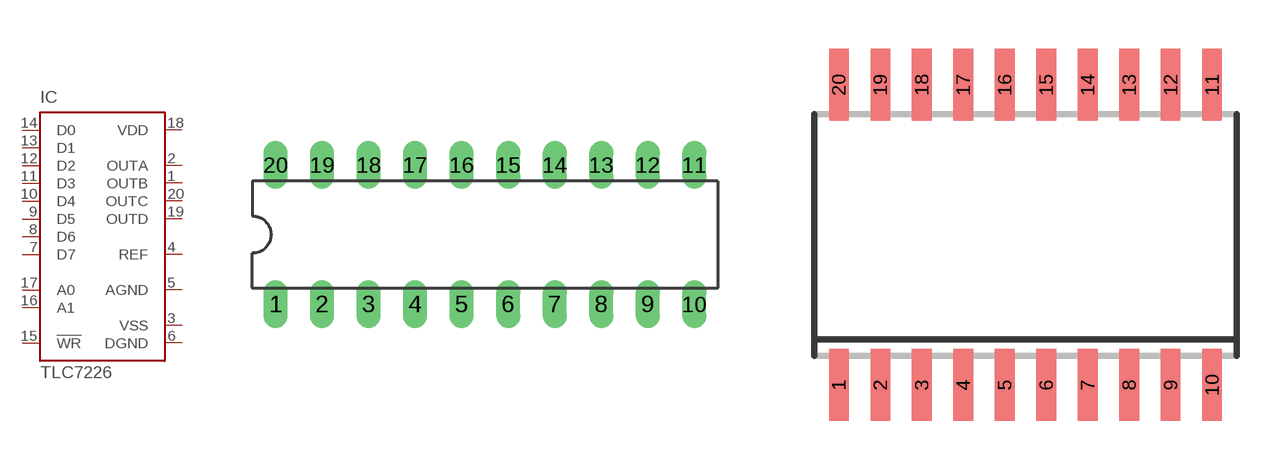
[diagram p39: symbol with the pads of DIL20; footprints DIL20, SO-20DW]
Designator prefix IC

## TLC7226CN (MF: TEXAS INSTRUMENT CONNECTORS; MPN: TLC7226CN; OC_FARNELL: 8454604; OC_NEWARK: 36K3647), TLC7226IN (MF: TEXAS INSTRUMENT CONNECTORS; MPN: TLC7226IN; OC_FARNELL: 8454620; OC_NEWARK: 76C7492)  [DIL20]
1  OUTB  out
2  OUTA  out
3  VSS  pwr
4  REF  in
5  AGND  pwr
6  DGND  pwr
7  D7  in
8  D6  in
9  D5  in
10  D4  in
11  D3  in
12  D2  in
13  D1  in
14  D0  in
15  !WR  in
16  A1  in
17  A0  in
18  VDD  pwr
19  OUTD  out
20  OUTC  out

## TLC7226CDW (MF: TEXAS INSTRUMENTS; MPN: TLC7226CDW; OC_FARNELL: 9854061; OC_NEWARK: 35K1223), TLC7226IDW (MF: TEXAS INSTRUMENTS; MPN: TLC7226IDW; OC_FARNELL: 8454612; OC_NEWARK: 76C7490)  [SO-20DW]
Pads as for DIL20

## TLC7226MFK (OC_FARNELL: unknown; OC_NEWARK: unknown)  [PLCC20]
Pads as for DIL20

## Footprint DIL20 (pad centres in mm)
Dual In Line Package
drill 0.813 long: 1 -11.43,-3.81; 2 -8.89,-3.81; 3 -6.35,-3.81; 4 -3.81,-3.81; 5 -1.27,-3.81; 6 1.27,-3.81; 7 3.81,-3.81; 8 6.35,-3.81; 9 8.89,-3.81; 10 11.43,-3.81; 11 11.43,3.81; 12 8.89,3.81; 13 6.35,3.81; 14 3.81,3.81; 15 1.27,3.81; 16 -1.27,3.81; 17 -3.81,3.81; 18 -6.35,3.81; 19 -8.89,3.81; 20 -11.43,3.81

## Footprint SO-20DW (pad centres in mm)
Small Outline Integrated Circuit wide
smd 0.6 x 2.2: 1 -5.715,-4.6; 2 -4.445,-4.6; 3 -3.175,-4.6; 4 -1.905,-4.6; 5 -0.635,-4.6; 6 0.635,-4.6; 7 1.905,-4.6; 8 3.175,-4.6; 9 4.445,-4.6; 10 5.715,-4.6; 11 5.715,4.6; 12 4.445,4.6; 13 3.175,4.6; 14 1.905,4.6; 15 0.635,4.6; 16 -0.635,4.6; 17 -1.905,4.6; 18 -3.175,4.6; 19 -4.445,4.6; 20 -5.715,4.6

## Footprint PLCC20 (pad centres in mm)
Plastic Leaded Chip Carrier
smd 0.6 x 2.2: 1 0,4.3; 2 -1.27,4.3; 3 -2.54,4.3; 9 -2.54,-4.3; 10 -1.27,-4.3; 11 0,-4.3; 12 1.27,-4.3; 13 2.54,-4.3; 19 2.54,4.3; 20 1.27,4.3
smd 2.2 x 0.6: 4 -4.3,2.54; 5 -4.3,1.27; 6 -4.3,0; 7 -4.3,-1.27; 8 -4.3,-2.54; 14 4.3,-2.54; 15 4.3,-1.27; 16 4.3,0; 17 4.3,1.27; 18 4.3,2.54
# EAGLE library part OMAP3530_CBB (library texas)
OMAP3530/25 Applications Processor 600-MHz ARM Cortex?-A8 Core Auto generated by make-symbol-device-package-bsdl.ulp Rev. 23 Source: sprm315.bsd

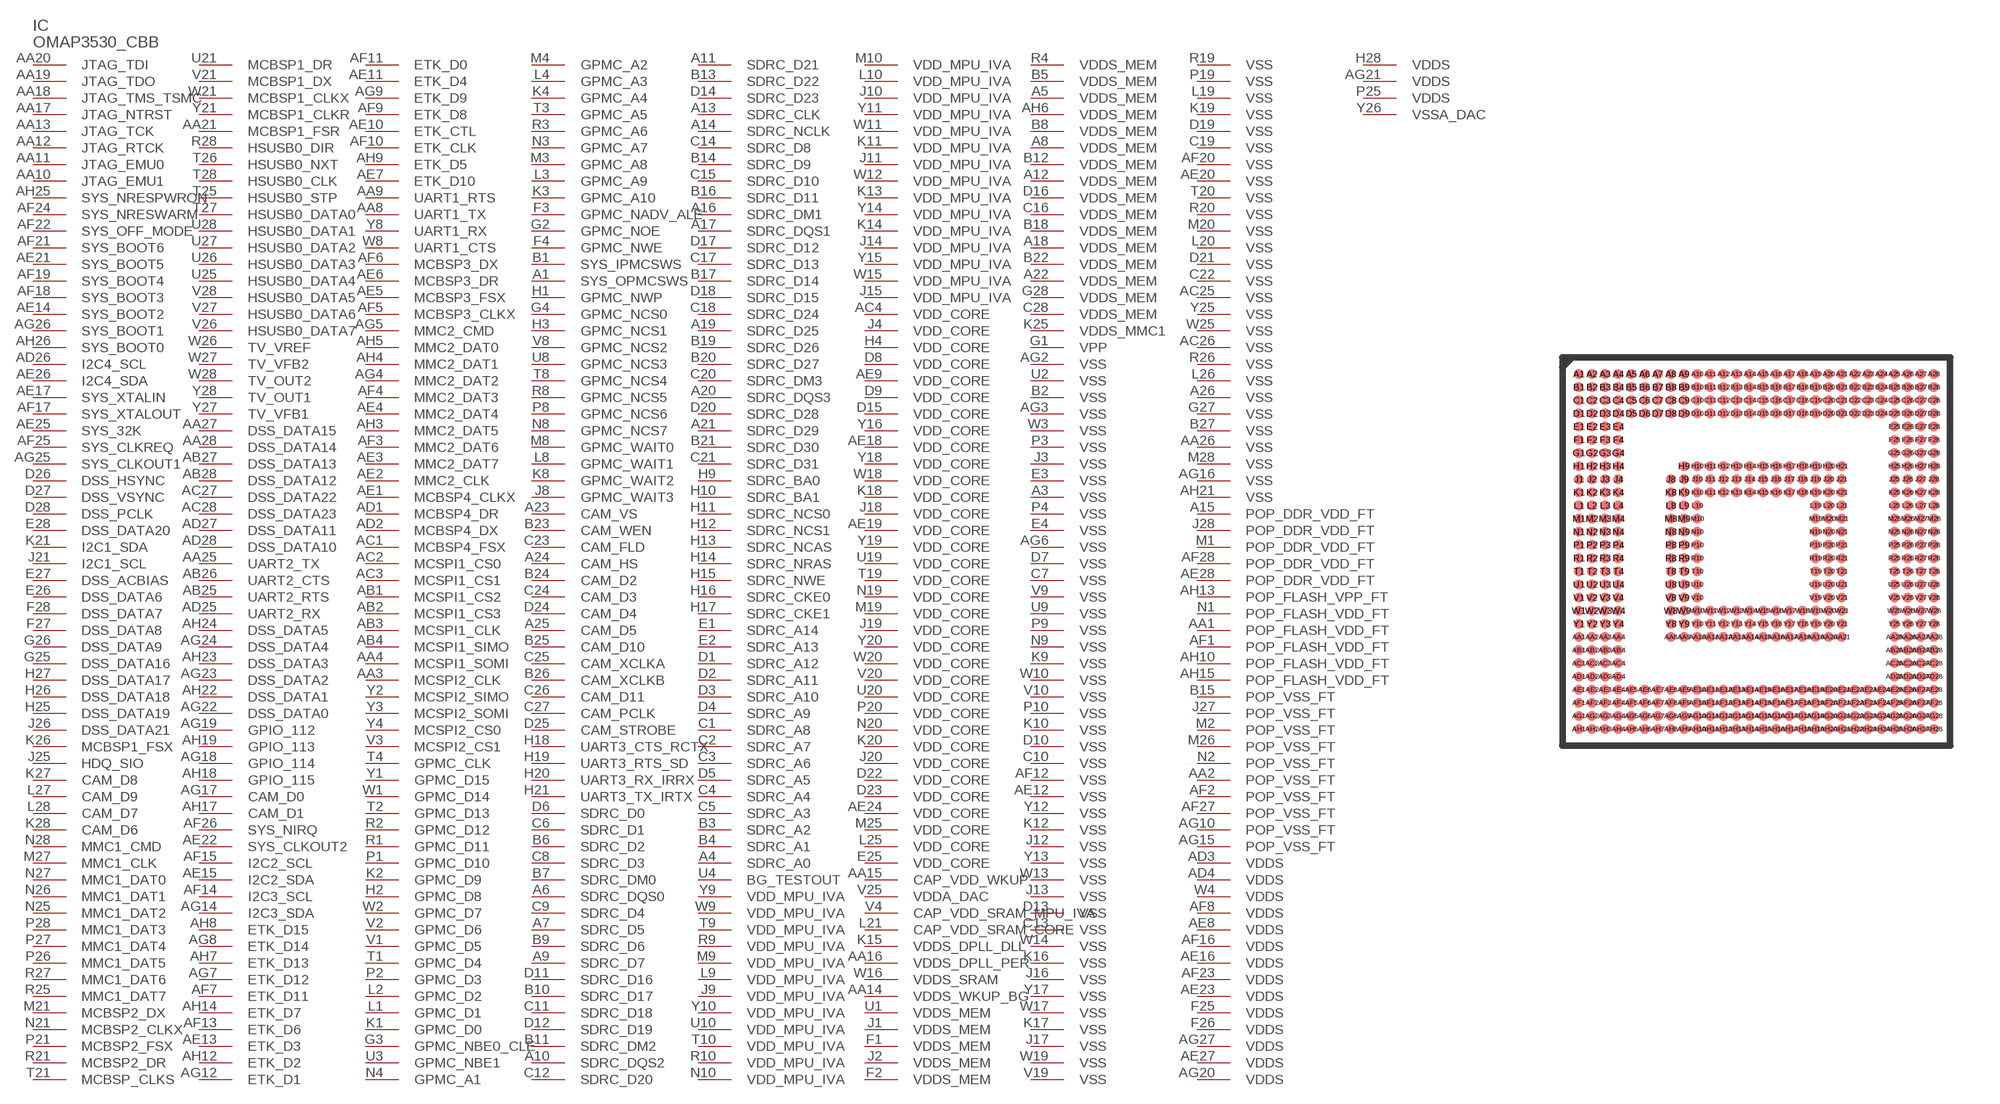
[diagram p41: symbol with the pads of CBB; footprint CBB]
Designator prefix IC

## OMAP3530_CBB (OC_FARNELL: 1660215; OC_NEWARK: unknown)  [CBB]
A1  SYS_OPMCSWS  pas
A3  VSS  pwr
A4  SDRC_A0  out
A5  VDDS_MEM  pwr
A6  SDRC_DQS0  pas
A7  SDRC_D5
A8  VDDS_MEM  pwr
A9  SDRC_D7
A10  SDRC_DQS2  pas
A11  SDRC_D21
A12  VDDS_MEM  pwr
A13  SDRC_CLK  pas
A14  SDRC_NCLK  pas
A15  POP_DDR_VDD_FT  pwr
A16  SDRC_DM1  out
A17  SDRC_DQS1  pas
A18  VDDS_MEM  pwr
A19  SDRC_D25
A20  SDRC_DQS3  pas
A21  SDRC_D29
A22  VDDS_MEM  pwr
A23  CAM_VS
A24  CAM_HS
A25  CAM_D5
A26  VSS  pwr
AA1  POP_FLASH_VDD_FT  pwr
AA2  POP_VSS_FT  pwr
AA3  MCSPI2_CLK
AA4  MCSPI1_SOMI
AA8  UART1_TX
AA9  UART1_RTS
AA10  JTAG_EMU1  pas
AA11  JTAG_EMU0  pas
AA12  JTAG_RTCK  pas
AA13  JTAG_TCK  in
AA14  VDDS_WKUP_BG  pwr
AA15  CAP_VDD_WKUP  pwr
AA16  VDDS_DPLL_PER  pwr
AA17  JTAG_NTRST  in
AA18  JTAG_TMS_TSMC  in
AA19  JTAG_TDO  out
AA20  JTAG_TDI  in
AA21  MCBSP1_FSR
AA25  UART2_TX
AA26  VSS  pwr
AA27  DSS_DATA15
AA28  DSS_DATA14
AB1  MCSPI1_CS2
AB2  MCSPI1_CS3
AB3  MCSPI1_CLK
AB4  MCSPI1_SIMO
AB25  UART2_RTS
AB26  UART2_CTS
AB27  DSS_DATA13
AB28  DSS_DATA12
AC1  MCBSP4_FSX
AC2  MCSPI1_CS0
AC3  MCSPI1_CS1
AC4  VDD_CORE  pwr
AC25  VSS  pwr
AC26  VSS  pwr
AC27  DSS_DATA22
AC28  DSS_DATA23
AD1  MCBSP4_DR
AD2  MCBSP4_DX
AD3  VDDS  pwr
AD4  VDDS  pwr
AD25  UART2_RX
AD26  I2C4_SCL
AD27  DSS_DATA11
AD28  DSS_DATA10
AE1  MCBSP4_CLKX
AE2  MMC2_CLK
AE3  MMC2_DAT7
AE4  MMC2_DAT4
AE5  MCBSP3_FSX
AE6  MCBSP3_DR
AE7  ETK_D10
AE8  VDDS  pwr
AE9  VDD_CORE  pwr
AE10  ETK_CTL
AE11  ETK_D4
AE12  VSS  pwr
AE13  ETK_D3
AE14  SYS_BOOT2
AE15  I2C2_SDA
AE16  VDDS  pwr
AE17  SYS_XTALIN  pas
AE18  VDD_CORE  pwr
AE19  VDD_CORE  pwr
AE20  VSS  pwr
AE21  SYS_BOOT5
AE22  SYS_CLKOUT2
AE23  VDDS  pwr
AE24  VDD_CORE  pwr
AE25  SYS_32K  pas
AE26  I2C4_SDA
AE27  VDDS  pwr
AE28  POP_DDR_VDD_FT  pwr
AF1  POP_FLASH_VDD_FT  pwr
AF2  POP_VSS_FT  pwr
AF3  MMC2_DAT6
AF4  MMC2_DAT3
AF5  MCBSP3_CLKX
AF6  MCBSP3_DX
AF7  ETK_D11
AF8  VDDS  pwr
AF9  ETK_D8
AF10  ETK_CLK
AF11  ETK_D0
AF12  VSS  pwr
AF13  ETK_D6
AF14  I2C3_SCL
AF15  I2C2_SCL
AF16  VDDS  pwr
AF17  SYS_XTALOUT  pas
AF18  SYS_BOOT3
AF19  SYS_BOOT4
AF20  VSS  pwr
AF21  SYS_BOOT6
AF22  SYS_OFF_MODE
AF23  VDDS  pwr
AF24  SYS_NRESWARM  pas
AF25  SYS_CLKREQ
AF26  SYS_NIRQ
AF27  POP_VSS_FT  pwr
AF28  POP_DDR_VDD_FT  pwr
AG2  VSS  pwr
AG3  VSS  pwr
AG4  MMC2_DAT2
AG5  MMC2_CMD
AG6  VSS  pwr
AG7  ETK_D12
AG8  ETK_D14
AG9  ETK_D9
AG10  POP_VSS_FT  pwr
AG12  ETK_D1
AG14  I2C3_SDA
AG15  POP_VSS_FT  pwr
AG16  VSS  pwr
AG17  CAM_D0
AG18  GPIO_114
AG19  GPIO_112
AG20  VDDS  pwr
AG21  VDDS  pwr
AG22  DSS_DATA0
AG23  DSS_DATA2
AG24  DSS_DATA4
AG25  SYS_CLKOUT1
AG26  SYS_BOOT1
AG27  VDDS  pwr
AH3  MMC2_DAT5
AH4  MMC2_DAT1
AH5  MMC2_DAT0
AH6  VDDS_MEM  pwr
AH7  ETK_D13
AH8  ETK_D15
AH9  ETK_D5
AH10  POP_FLASH_VDD_FT  pwr
AH12  ETK_D2
AH13  POP_FLASH_VPP_FT  pas
AH14  ETK_D7
AH15  POP_FLASH_VDD_FT  pwr
AH17  CAM_D1
AH18  GPIO_115
AH19  GPIO_113
AH21  VSS  pwr
AH22  DSS_DATA1
AH23  DSS_DATA3
AH24  DSS_DATA5
AH25  SYS_NRESPWRON  pas
AH26  SYS_BOOT0
B1  SYS_IPMCSWS  pas
B2  VSS  pwr
B3  SDRC_A2  out
B4  SDRC_A1  out
B5  VDDS_MEM  pwr
B6  SDRC_D2
B7  SDRC_DM0  out
B8  VDDS_MEM  pwr
B9  SDRC_D6
B10  SDRC_D17
B11  SDRC_DM2  out
B12  VDDS_MEM  pwr
B13  SDRC_D22
B14  SDRC_D9
B15  POP_VSS_FT  pwr
B16  SDRC_D11
B17  SDRC_D14
B18  VDDS_MEM  pwr
B19  SDRC_D26
B20  SDRC_D27
B21  SDRC_D30
B22  VDDS_MEM  pwr
B23  CAM_WEN
B24  CAM_D2
B25  CAM_D10
B26  CAM_XCLKB
B27  VSS  pwr
C1  SDRC_A8  out
C2  SDRC_A7  out
C3  SDRC_A6  out
C4  SDRC_A4  out
C5  SDRC_A3  out
C6  SDRC_D1
C7  VSS  pwr
C8  SDRC_D3
C9  SDRC_D4
C10  VSS  pwr
C11  SDRC_D18
C12  SDRC_D20
C13  VSS  pwr
C14  SDRC_D8
C15  SDRC_D10
C16  VDDS_MEM  pwr
C17  SDRC_D13
C18  SDRC_D24
C19  VSS  pwr
C20  SDRC_DM3  out
C21  SDRC_D31
C22  VSS  pwr
C23  CAM_FLD
C24  CAM_D3
C25  CAM_XCLKA
C26  CAM_D11
C27  CAM_PCLK
C28  VDDS_MEM  pwr
D1  SDRC_A12  out
D2  SDRC_A11  out
D3  SDRC_A10  out
D4  SDRC_A9  out
D5  SDRC_A5  out
D6  SDRC_D0
D7  VSS  pwr
D8  VDD_CORE  pwr
D9  VDD_CORE  pwr
D10  VSS  pwr
D11  SDRC_D16
D12  SDRC_D19
D13  VSS  pwr
D14  SDRC_D23
D15  VDD_CORE  pwr
D16  VDDS_MEM  pwr
D17  SDRC_D12
D18  SDRC_D15
D19  VSS  pwr
D20  SDRC_D28
D21  VSS  pwr
D22  VDD_CORE  pwr
D23  VDD_CORE  pwr
D24  CAM_D4
D25  CAM_STROBE
D26  DSS_HSYNC
D27  DSS_VSYNC
D28  DSS_PCLK
E1  SDRC_A14  out
E2  SDRC_A13  out
E3  VSS  pwr
E4  VSS  pwr
E25  VDD_CORE  pwr
E26  DSS_DATA6
E27  DSS_ACBIAS
E28  DSS_DATA20
F1  VDDS_MEM  pwr
F2  VDDS_MEM  pwr
F3  GPMC_NADV_ALE  out
F4  GPMC_NWE  out
F25  VDDS  pwr
F26  VDDS  pwr
F27  DSS_DATA8
F28  DSS_DATA7
G1  VPP  pas
G2  GPMC_NOE  out
G3  GPMC_NBE0_CLE
G4  GPMC_NCS0  out
G25  DSS_DATA16
G26  DSS_DATA9
G27  VSS  pwr
G28  VDDS_MEM  pwr
H1  GPMC_NWP
H2  GPMC_D8
H3  GPMC_NCS1
H4  VDD_CORE  pwr
H9  SDRC_BA0  out
H10  SDRC_BA1  out
H11  SDRC_NCS0  out
H12  SDRC_NCS1  out
H13  SDRC_NCAS  out
H14  SDRC_NRAS  out
H15  SDRC_NWE  out
H16  SDRC_CKE0  out
H17  SDRC_CKE1  out
H18  UART3_CTS_RCTX
H19  UART3_RTS_SD
H20  UART3_RX_IRRX
H21  UART3_TX_IRTX
H25  DSS_DATA19
H26  DSS_DATA18
H27  DSS_DATA17
H28  VDDS  pwr
J1  VDDS_MEM  pwr
J2  VDDS_MEM  pwr
J3  VSS  pwr
J4  VDD_CORE  pwr
J8  GPMC_WAIT3
J9  VDD_MPU_IVA  pwr
J10  VDD_MPU_IVA  pwr
J11  VDD_MPU_IVA  pwr
J12  VSS  pwr
J13  VSS  pwr
J14  VDD_MPU_IVA  pwr
J15  VDD_MPU_IVA  pwr
J16  VSS  pwr
J17  VSS  pwr
J18  VDD_CORE  pwr
J19  VDD_CORE  pwr
J20  VDD_CORE  pwr
J21  I2C1_SCL
J25  HDQ_SIO
J26  DSS_DATA21
J27  POP_VSS_FT  pwr
J28  POP_DDR_VDD_FT  pwr
K1  GPMC_D0
K2  GPMC_D9
K3  GPMC_A10
K4  GPMC_A4
K8  GPMC_WAIT2
K9  VSS  pwr
K10  VSS  pwr
K11  VDD_MPU_IVA  pwr
K12  VSS  pwr
K13  VDD_MPU_IVA  pwr
K14  VDD_MPU_IVA  pwr
K15  VDDS_DPLL_DLL  pwr
K16  VSS  pwr
K17  VSS  pwr
K18  VDD_CORE  pwr
K19  VSS  pwr
K20  VDD_CORE  pwr
K21  I2C1_SDA
K25  VDDS_MMC1  pwr
K26  MCBSP1_FSX
K27  CAM_D8
K28  CAM_D6
L1  GPMC_D1
L2  GPMC_D2
L3  GPMC_A9
L4  GPMC_A3
L8  GPMC_WAIT1
L9  VDD_MPU_IVA  pwr
L10  VDD_MPU_IVA  pwr
L19  VSS  pwr
L20  VSS  pwr
L21  CAP_VDD_SRAM_CORE  pwr
L25  VDD_CORE  pwr
L26  VSS  pwr
L27  CAM_D9
L28  CAM_D7
M1  POP_DDR_VDD_FT  pwr
M2  POP_VSS_FT  pwr
M3  GPMC_A8
M4  GPMC_A2
M8  GPMC_WAIT0  in
M9  VDD_MPU_IVA  pwr
M10  VDD_MPU_IVA  pwr
M19  VDD_CORE  pwr
M20  VSS  pwr
M21  MCBSP2_DX
M25  VDD_CORE  pwr
M26  POP_VSS_FT  pwr
M27  MMC1_CLK
M28  VSS  pwr
N1  POP_FLASH_VDD_FT  pwr
N2  POP_VSS_FT  pwr
N3  GPMC_A7
N4  GPMC_A1
N8  GPMC_NCS7
N9  VSS  pwr
N10  VDD_MPU_IVA  pwr
N19  VDD_CORE  pwr
N20  VDD_CORE  pwr
N21  MCBSP2_CLKX
N25  MMC1_DAT2
N26  MMC1_DAT1
N27  MMC1_DAT0
N28  MMC1_CMD
P1  GPMC_D10
P2  GPMC_D3
P3  VSS  pwr
P4  VSS  pwr
P8  GPMC_NCS6
P9  VSS  pwr
P10  VSS  pwr
P19  VSS  pwr
P20  VDD_CORE  pwr
P21  MCBSP2_FSX
P25  VDDS  pwr
P26  MMC1_DAT5
P27  MMC1_DAT4
P28  MMC1_DAT3
R1  GPMC_D11
R2  GPMC_D12
R3  GPMC_A6
R4  VDDS_MEM  pwr
R8  GPMC_NCS5
R9  VDD_MPU_IVA  pwr
R10  VDD_MPU_IVA  pwr
R19  VSS  pwr
R20  VSS  pwr
R21  MCBSP2_DR
R25  MMC1_DAT7
R26  VSS  pwr
R27  MMC1_DAT6
R28  HSUSB0_DIR
T1  GPMC_D4
T2  GPMC_D13
T3  GPMC_A5
T4  GPMC_CLK
T8  GPMC_NCS4
T9  VDD_MPU_IVA  pwr
T10  VDD_MPU_IVA  pwr
T19  VDD_CORE  pwr
T20  VSS  pwr
T21  MCBSP_CLKS
T25  HSUSB0_STP
T26  HSUSB0_NXT
T27  HSUSB0_DATA0
T28  HSUSB0_CLK
U1  VDDS_MEM  pwr
U2  VSS  pwr
U3  GPMC_NBE1
U4  BG_TESTOUT  pas
U8  GPMC_NCS3
U9  VSS  pwr
U10  VDD_MPU_IVA  pwr
U19  VDD_CORE  pwr
U20  VDD_CORE  pwr
U21  MCBSP1_DR
U25  HSUSB0_DATA4
U26  HSUSB0_DATA3
U27  HSUSB0_DATA2
U28  HSUSB0_DATA1
V1  GPMC_D5
V2  GPMC_D6
V3  MCSPI2_CS1
V4  CAP_VDD_SRAM_MPU_IVA  pwr
V8  GPMC_NCS2
V9  VSS  pwr
V10  VSS  pwr
V19  VSS  pwr
V20  VDD_CORE  pwr
V21  MCBSP1_DX
V25  VDDA_DAC  pwr
V26  HSUSB0_DATA7
V27  HSUSB0_DATA6
V28  HSUSB0_DATA5
W1  GPMC_D14
W2  GPMC_D7
W3  VSS  pwr
W4  VDDS  pwr
W8  UART1_CTS
W9  VDD_MPU_IVA  pwr
W10  VSS  pwr
W11  VDD_MPU_IVA  pwr
W12  VDD_MPU_IVA  pwr
W13  VSS  pwr
W14  VSS  pwr
W15  VDD_MPU_IVA  pwr
W16  VDDS_SRAM  pwr
W17  VSS  pwr
W18  VDD_CORE  pwr
W19  VSS  pwr
W20  VDD_CORE  pwr
W21  MCBSP1_CLKX
W25  VSS  pwr
W26  TV_VREF  pas
W27  TV_VFB2  pas
W28  TV_OUT2  pas
Y1  GPMC_D15
Y2  MCSPI2_SIMO
Y3  MCSPI2_SOMI
Y4  MCSPI2_CS0
Y8  UART1_RX
Y9  VDD_MPU_IVA  pwr
Y10  VDD_MPU_IVA  pwr
Y11  VDD_MPU_IVA  pwr
Y12  VSS  pwr
Y13  VSS  pwr
Y14  VDD_MPU_IVA  pwr
Y15  VDD_MPU_IVA  pwr
Y16  VDD_CORE  pwr
Y17  VSS  pwr
Y18  VDD_CORE  pwr
Y19  VDD_CORE  pwr
Y20  VDD_CORE  pwr
Y21  MCBSP1_CLKR
Y25  VSS  pwr
Y26  VSSA_DAC  pwr
Y27  TV_VFB1  pas
Y28  TV_OUT1  pas

## Footprint CBB (pad centres in mm)
CBB (S-PBGA-N515) Auto generated by make-symbol-device-package-bsdl.ulp Rev. 23 Source: sprm315.bsd
smd 0.3 x 0.3: A1 -5.4,5.4; A2 -5,5.4; A3 -4.6,5.4; A4 -4.2,5.4; A5 -3.8,5.4; A6 -3.4,5.4; A7 -3,5.4; A8 -2.6,5.4; A9 -2.2,5.4; A10 -1.8,5.4; A11 -1.4,5.4; A12 -1,5.4; A13 -0.6,5.4; A14 -0.2,5.4; A15 0.2,5.4; A16 0.6,5.4; A17 1,5.4; A18 1.4,5.4; A19 1.8,5.4; A20 2.2,5.4; A21 2.6,5.4; A22 3,5.4; A23 3.4,5.4; A24 3.8,5.4; A25 4.2,5.4; A26 4.6,5.4; A27 5,5.4; A28 5.4,5.4; AA1 -5.4,-2.6; AA2 -5,-2.6; AA3 -4.6,-2.6; AA4 -4.2,-2.6; AA8 -2.6,-2.6; AA9 -2.2,-2.6; AA10 -1.8,-2.6; AA11 -1.4,-2.6; AA12 -1,-2.6; AA13 -0.6,-2.6; AA14 -0.2,-2.6; AA15 0.2,-2.6; AA16 0.6,-2.6; AA17 1,-2.6; AA18 1.4,-2.6; AA19 1.8,-2.6; AA20 2.2,-2.6; AA21 2.6,-2.6; AA25 4.2,-2.6; AA26 4.6,-2.6; AA27 5,-2.6; AA28 5.4,-2.6; AB1 -5.4,-3; AB2 -5,-3; AB3 -4.6,-3; AB4 -4.2,-3; AB25 4.2,-3; AB26 4.6,-3; AB27 5,-3; AB28 5.4,-3; AC1 -5.4,-3.4; AC2 -5,-3.4; AC3 -4.6,-3.4; AC4 -4.2,-3.4; AC25 4.2,-3.4; AC26 4.6,-3.4; AC27 5,-3.4; AC28 5.4,-3.4; AD1 -5.4,-3.8; AD2 -5,-3.8; AD3 -4.6,-3.8; AD4 -4.2,-3.8; AD25 4.2,-3.8; AD26 4.6,-3.8; AD27 5,-3.8; AD28 5.4,-3.8; AE1 -5.4,-4.2; AE2 -5,-4.2; AE3 -4.6,-4.2; AE4 -4.2,-4.2; AE5 -3.8,-4.2; AE6 -3.4,-4.2; AE7 -3,-4.2; AE8 -2.6,-4.2; AE9 -2.2,-4.2; AE10 -1.8,-4.2; AE11 -1.4,-4.2; AE12 -1,-4.2; AE13 -0.6,-4.2; AE14 -0.2,-4.2; AE15 0.2,-4.2; AE16 0.6,-4.2; AE17 1,-4.2; AE18 1.4,-4.2; AE19 1.8,-4.2; AE20 2.2,-4.2; AE21 2.6,-4.2; AE22 3,-4.2; AE23 3.4,-4.2; AE24 3.8,-4.2; AE25 4.2,-4.2; AE26 4.6,-4.2; AE27 5,-4.2; AE28 5.4,-4.2; AF1 -5.4,-4.6; AF2 -5,-4.6; AF3 -4.6,-4.6; AF4 -4.2,-4.6; AF5 -3.8,-4.6; AF6 -3.4,-4.6; AF7 -3,-4.6; AF8 -2.6,-4.6; AF9 -2.2,-4.6; AF10 -1.8,-4.6; AF11 -1.4,-4.6; AF12 -1,-4.6; AF13 -0.6,-4.6; AF14 -0.2,-4.6; AF15 0.2,-4.6; AF16 0.6,-4.6; AF17 1,-4.6; AF18 1.4,-4.6; AF19 1.8,-4.6; AF20 2.2,-4.6; AF21 2.6,-4.6; AF22 3,-4.6; AF23 3.4,-4.6; AF24 3.8,-4.6; AF25 4.2,-4.6; AF26 4.6,-4.6; AF27 5,-4.6; AF28 5.4,-4.6; AG1 -5.4,-5; AG2 -5,-5; AG3 -4.6,-5; AG4 -4.2,-5; AG5 -3.8,-5; AG6 -3.4,-5; AG7 -3,-5; AG8 -2.6,-5; AG9 -2.2,-5; AG10 -1.8,-5; AG11 -1.4,-5; AG12 -1,-5; AG13 -0.6,-5; AG14 -0.2,-5; AG15 0.2,-5; AG16 0.6,-5; AG17 1,-5; AG18 1.4,-5; AG19 1.8,-5; AG20 2.2,-5; AG21 2.6,-5; AG22 3,-5; AG23 3.4,-5; AG24 3.8,-5; AG25 4.2,-5; AG26 4.6,-5; AG27 5,-5; AG28 5.4,-5; AH1 -5.4,-5.4; AH2 -5,-5.4; AH3 -4.6,-5.4; AH4 -4.2,-5.4; AH5 -3.8,-5.4; AH6 -3.4,-5.4; AH7 -3,-5.4; AH8 -2.6,-5.4; AH9 -2.2,-5.4; AH10 -1.8,-5.4; AH11 -1.4,-5.4; AH12 -1,-5.4; AH13 -0.6,-5.4; AH14 -0.2,-5.4; AH15 0.2,-5.4; AH16 0.6,-5.4; AH17 1,-5.4; AH18 1.4,-5.4; AH19 1.8,-5.4; AH20 2.2,-5.4; AH21 2.6,-5.4; AH22 3,-5.4; AH23 3.4,-5.4; AH24 3.8,-5.4; AH25 4.2,-5.4; AH26 4.6,-5.4; AH27 5,-5.4; AH28 5.4,-5.4; B1 -5.4,5; B2 -5,5; B3 -4.6,5; B4 -4.2,5; B5 -3.8,5; B6 -3.4,5; B7 -3,5; B8 -2.6,5; B9 -2.2,5; B10 -1.8,5; B11 -1.4,5; B12 -1,5; B13 -0.6,5; B14 -0.2,5; B15 0.2,5; B16 0.6,5; B17 1,5; B18 1.4,5; B19 1.8,5; B20 2.2,5; B21 2.6,5; B22 3,5; B23 3.4,5; B24 3.8,5; B25 4.2,5; B26 4.6,5; B27 5,5; B28 5.4,5; C1 -5.4,4.6; C2 -5,4.6; C3 -4.6,4.6; C4 -4.2,4.6; C5 -3.8,4.6; C6 -3.4,4.6; C7 -3,4.6; C8 -2.6,4.6; C9 -2.2,4.6; C10 -1.8,4.6; C11 -1.4,4.6; C12 -1,4.6; C13 -0.6,4.6; C14 -0.2,4.6; C15 0.2,4.6; C16 0.6,4.6; C17 1,4.6; C18 1.4,4.6; C19 1.8,4.6; C20 2.2,4.6; C21 2.6,4.6; C22 3,4.6; C23 3.4,4.6; C24 3.8,4.6; C25 4.2,4.6; C26 4.6,4.6; C27 5,4.6; C28 5.4,4.6; D1 -5.4,4.2; D2 -5,4.2; D3 -4.6,4.2; D4 -4.2,4.2; D5 -3.8,4.2; D6 -3.4,4.2; D7 -3,4.2; D8 -2.6,4.2; D9 -2.2,4.2; D10 -1.8,4.2; D11 -1.4,4.2; D12 -1,4.2; D13 -0.6,4.2; D14 -0.2,4.2; D15 0.2,4.2; D16 0.6,4.2; D17 1,4.2; D18 1.4,4.2; D19 1.8,4.2; D20 2.2,4.2; D21 2.6,4.2; D22 3,4.2; D23 3.4,4.2; D24 3.8,4.2; D25 4.2,4.2; D26 4.6,4.2; D27 5,4.2; D28 5.4,4.2; E1 -5.4,3.8; E2 -5,3.8; E3 -4.6,3.8; E4 -4.2,3.8; E25 4.2,3.8; E26 4.6,3.8; E27 5,3.8; E28 5.4,3.8; F1 -5.4,3.4; F2 -5,3.4; F3 -4.6,3.4; F4 -4.2,3.4; F25 4.2,3.4; F26 4.6,3.4; F27 5,3.4; F28 5.4,3.4; G1 -5.4,3; G2 -5,3; G3 -4.6,3; G4 -4.2,3; G25 4.2,3; G26 4.6,3; G27 5,3; G28 5.4,3; H1 -5.4,2.6; H2 -5,2.6; H3 -4.6,2.6; H4 -4.2,2.6; H9 -2.2,2.6; H10 -1.8,2.6; H11 -1.4,2.6; H12 -1,2.6; H13 -0.6,2.6; H14 -0.2,2.6; H15 0.2,2.6; H16 0.6,2.6; H17 1,2.6; H18 1.4,2.6; H19 1.8,2.6; H20 2.2,2.6; H21 2.6,2.6; H25 4.2,2.6; H26 4.6,2.6; H27 5,2.6; H28 5.4,2.6; J1 -5.4,2.2; J2 -5,2.2; J3 -4.6,2.2; J4 -4.2,2.2; J8 -2.6,2.2; J9 -2.2,2.2; J10 -1.8,2.2; J11 -1.4,2.2; J12 -1,2.2; J13 -0.6,2.2; J14 -0.2,2.2; J15 0.2,2.2; J16 0.6,2.2; J17 1,2.2; J18 1.4,2.2; J19 1.8,2.2; J20 2.2,2.2; J21 2.6,2.2; J25 4.2,2.2; J26 4.6,2.2; J27 5,2.2; J28 5.4,2.2; K1 -5.4,1.8; K2 -5,1.8; K3 -4.6,1.8; K4 -4.2,1.8; K8 -2.6,1.8; K9 -2.2,1.8; K10 -1.8,1.8; K11 -1.4,1.8; K12 -1,1.8; K13 -0.6,1.8; K14 -0.2,1.8; K15 0.2,1.8; K16 0.6,1.8; K17 1,1.8; K18 1.4,1.8; K19 1.8,1.8; K20 2.2,1.8; K21 2.6,1.8; K25 4.2,1.8; K26 4.6,1.8; K27 5,1.8; K28 5.4,1.8; L1 -5.4,1.4; L2 -5,1.4; L3 -4.6,1.4; L4 -4.2,1.4; L8 -2.6,1.4; L9 -2.2,1.4; L10 -1.8,1.4; L19 1.8,1.4; L20 2.2,1.4; L21 2.6,1.4; L25 4.2,1.4; L26 4.6,1.4; L27 5,1.4; L28 5.4,1.4; M1 -5.4,1; M2 -5,1; M3 -4.6,1; M4 -4.2,1; M8 -2.6,1; M9 -2.2,1; M10 -1.8,1; M19 1.8,1; M20 2.2,1; M21 2.6,1; M25 4.2,1; M26 4.6,1; M27 5,1; M28 5.4,1; N1 -5.4,0.6; N2 -5,0.6; N3 -4.6,0.6; N4 -4.2,0.6; N8 -2.6,0.6; N9 -2.2,0.6; N10 -1.8,0.6; N19 1.8,0.6; N20 2.2,0.6; N21 2.6,0.6; N25 4.2,0.6; N26 4.6,0.6; N27 5,0.6; N28 5.4,0.6; P1 -5.4,0.2; P2 -5,0.2; P3 -4.6,0.2; P4 -4.2,0.2; P8 -2.6,0.2; P9 -2.2,0.2; P10 -1.8,0.2; P19 1.8,0.2; P20 2.2,0.2; P21 2.6,0.2; P25 4.2,0.2; P26 4.6,0.2; P27 5,0.2; P28 5.4,0.2; R1 -5.4,-0.2; R2 -5,-0.2; R3 -4.6,-0.2; R4 -4.2,-0.2; R8 -2.6,-0.2; R9 -2.2,-0.2; R10 -1.8,-0.2; R19 1.8,-0.2; R20 2.2,-0.2; R21 2.6,-0.2; R25 4.2,-0.2; R26 4.6,-0.2; R27 5,-0.2; R28 5.4,-0.2; T1 -5.4,-0.6; T2 -5,-0.6; T3 -4.6,-0.6; T4 -4.2,-0.6; T8 -2.6,-0.6; T9 -2.2,-0.6; T10 -1.8,-0.6; T19 1.8,-0.6; T20 2.2,-0.6; T21 2.6,-0.6; T25 4.2,-0.6; T26 4.6,-0.6; T27 5,-0.6; T28 5.4,-0.6; U1 -5.4,-1; U2 -5,-1; U3 -4.6,-1; U4 -4.2,-1; U8 -2.6,-1; U9 -2.2,-1; U10 -1.8,-1; U19 1.8,-1; U20 2.2,-1; U21 2.6,-1; U25 4.2,-1; U26 4.6,-1; U27 5,-1; U28 5.4,-1; V1 -5.4,-1.4; V2 -5,-1.4; V3 -4.6,-1.4; V4 -4.2,-1.4; V8 -2.6,-1.4; V9 -2.2,-1.4; V10 -1.8,-1.4; V19 1.8,-1.4; V20 2.2,-1.4; V21 2.6,-1.4; V25 4.2,-1.4; V26 4.6,-1.4; V27 5,-1.4; V28 5.4,-1.4; W1 -5.4,-1.8; W2 -5,-1.8; W3 -4.6,-1.8; W4 -4.2,-1.8; W8 -2.6,-1.8; W9 -2.2,-1.8; W10 -1.8,-1.8; W11 -1.4,-1.8; W12 -1,-1.8; W13 -0.6,-1.8; W14 -0.2,-1.8; W15 0.2,-1.8; W16 0.6,-1.8; W17 1,-1.8; W18 1.4,-1.8; W19 1.8,-1.8; W20 2.2,-1.8; W21 2.6,-1.8; W25 4.2,-1.8; W26 4.6,-1.8; W27 5,-1.8; W28 5.4,-1.8; Y1 -5.4,-2.2; Y2 -5,-2.2; Y3 -4.6,-2.2; Y4 -4.2,-2.2; Y8 -2.6,-2.2; Y9 -2.2,-2.2; Y10 -1.8,-2.2; Y11 -1.4,-2.2; Y12 -1,-2.2; Y13 -0.6,-2.2; Y14 -0.2,-2.2; Y15 0.2,-2.2; Y16 0.6,-2.2; Y17 1,-2.2; Y18 1.4,-2.2; Y19 1.8,-2.2; Y20 2.2,-2.2; Y21 2.6,-2.2; Y25 4.2,-2.2; Y26 4.6,-2.2; Y27 5,-2.2; Y28 5.4,-2.2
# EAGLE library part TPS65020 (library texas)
POWER MANAGEMENT IC FOR LI-ION POWERED SYSTEMS Source: http://focus.ti.com/lit/ds/symlink/tps65020.pdf

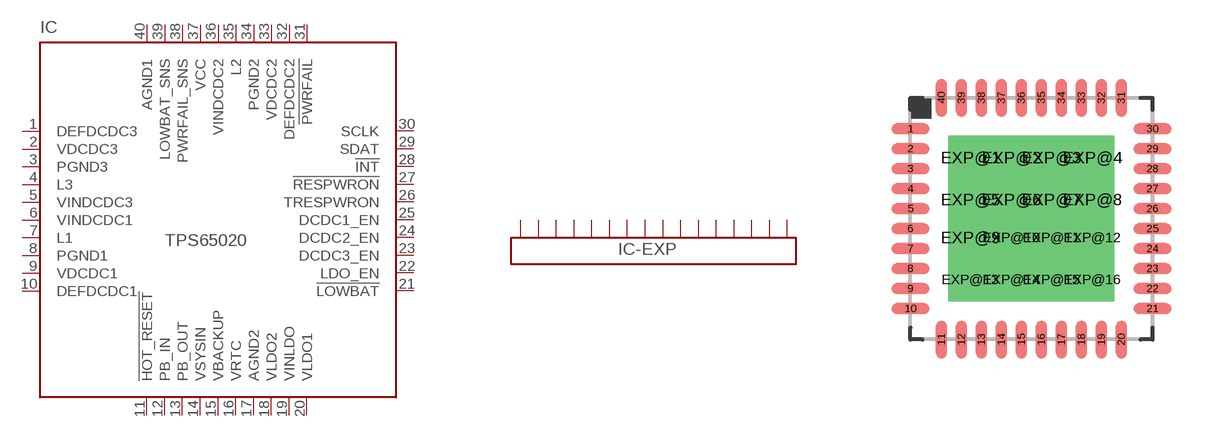
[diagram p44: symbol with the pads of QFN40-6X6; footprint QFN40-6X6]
Designator prefix IC; gates G$1=TPS65020 -EXP=EXP-16

## TPS65020 (MF: TEXAS INSTRUMENT CONNECTORS; MPN: TPS65020RHAT; OC_FARNELL: 1412603; OC_NEWARK: 61K1903)  [QFN40-6X6]
1  G$1:DEFDCDC3  in
2  G$1:VDCDC3  in
3  G$1:PGND3  in
4  G$1:L3  pas
5  G$1:VINDCDC3  in
6  G$1:VINDCDC1  in
7  G$1:L1  pas
8  G$1:PGND1  in
9  G$1:VDCDC1  in
10  G$1:DEFDCDC1  in
11  G$1:!HOT_RESET  in
12  G$1:PB_IN  in
13  G$1:PB_OUT  in
14  G$1:VSYSIN  in
15  G$1:VBACKUP  in
16  G$1:VRTC  out
17  G$1:AGND2  in
18  G$1:VLDO2  out
19  G$1:VINLDO  in
20  G$1:VLDO1  out
21  G$1:!LOWBAT  oc
22  G$1:LDO_EN  in
23  G$1:DCDC3_EN  in
24  G$1:DCDC2_EN  in
25  G$1:DCDC1_EN  in
26  G$1:TRESPWRON  in
27  G$1:!RESPWRON  oc
28  G$1:!INT  oc
29  G$1:SDAT
30  G$1:SCLK  in
31  G$1:!PWRFAIL  oc
32  G$1:DEFDCDC2  in
33  G$1:VDCDC2  in
34  G$1:PGND2  in
35  G$1:L2  pas
36  G$1:VINDCDC2  in
37  G$1:VCC  in
38  G$1:PWRFAIL_SNS  in
39  G$1:LOWBAT_SNS  in
40  G$1:AGND1  in
EXP@1  -EXP:EXP16  in
EXP@2  -EXP:EXP16  in
EXP@3  -EXP:EXP16  in
EXP@4  -EXP:EXP16  in
EXP@5  -EXP:EXP16  in
EXP@6  -EXP:EXP16  in
EXP@7  -EXP:EXP16  in
EXP@8  -EXP:EXP16  in
EXP@9  -EXP:EXP16  in
EXP@10  -EXP:EXP16  in
EXP@11  -EXP:EXP16  in
EXP@12  -EXP:EXP16  in
EXP@13  -EXP:EXP16  in
EXP@14  -EXP:EXP16  in
EXP@15  -EXP:EXP16  in
EXP@16  -EXP:EXP16  in

## Footprint QFN40-6X6 (pad centres in mm)
RHA (S-PQFP-N40) 6 x 6 mm Source: http://focus.ti.com/lit/ds/symlink/tps65020.pdf
smd 0.95 x 0.28: 1 -3.025,2.25; 2 -3.025,1.75; 3 -3.025,1.25; 4 -3.025,0.75; 5 -3.025,0.25; 6 -3.025,-0.25; 7 -3.025,-0.75; 8 -3.025,-1.25; 9 -3.025,-1.75; 10 -3.025,-2.25; 21 3.025,-2.25; 22 3.025,-1.75; 23 3.025,-1.25; 24 3.025,-0.75; 25 3.025,-0.25; 26 3.025,0.25; 27 3.025,0.75; 28 3.025,1.25; 29 3.025,1.75; 30 3.025,2.25
smd 0.28 x 0.95: 11 -2.25,-3.025; 12 -1.75,-3.025; 13 -1.25,-3.025; 14 -0.75,-3.025; 15 -0.25,-3.025; 16 0.25,-3.025; 17 0.75,-3.025; 18 1.25,-3.025; 19 1.75,-3.025; 20 2.25,-3.025; 31 2.25,3.025; 32 1.75,3.025; 33 1.25,3.025; 34 0.75,3.025; 35 0.25,3.025; 36 -0.25,3.025; 37 -0.75,3.025; 38 -1.25,3.025; 39 -1.75,3.025; 40 -2.25,3.025
drill 0.3 pad 1.1 square: EXP@1 -1.525,1.525; EXP@2 -0.5,1.525; EXP@3 0.5,1.525; EXP@4 1.525,1.525; EXP@5 -1.525,0.475; EXP@6 -0.5,0.475; EXP@7 0.5,0.475; EXP@8 1.525,0.475; EXP@9 -1.525,-0.475; EXP@10 -0.5,-0.475; EXP@11 0.5,-0.475; EXP@12 1.525,-0.475; EXP@13 -1.525,-1.525; EXP@14 -0.5,-1.525; EXP@15 0.5,-1.525; EXP@16 1.525,-1.525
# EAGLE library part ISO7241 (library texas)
HIGH SPEED QUAD DIGITAL ISOLATORS Source: http://focus.ti.com/lit/ds/symlink/iso7240m.pdf

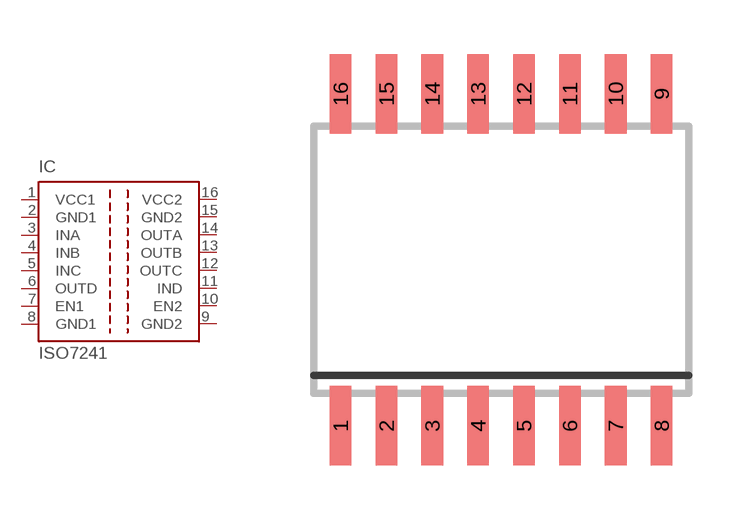
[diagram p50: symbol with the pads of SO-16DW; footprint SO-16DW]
Designator prefix IC

## ISO7241 (MPN: ISO7241CDW; OC_FARNELL: 1575372; OC_NEWARK: 73M3155)  [SO-16DW]
1  VCC1  pwr
2  GND1  pwr
3  INA  in
4  INB  in
5  INC  in
6  OUTD  out
7  EN1  in
8  GND1  pwr
9  GND2  pwr
10  EN2  in
11  IND  in
12  OUTC  out
13  OUTB  out
14  OUTA  out
15  GND2  pwr
16  VCC2  pwr

## Footprint SO-16DW (pad centres in mm)
DW (RPDSO-G16) Source: http://focus.ti.com/lit/ds/symlink/iso1176.pdf
smd 0.6 x 2.2: 1 -4.445,-4.6; 2 -3.175,-4.6; 3 -1.905,-4.6; 4 -0.635,-4.6; 5 0.635,-4.6; 6 1.905,-4.6; 7 3.175,-4.6; 8 4.445,-4.6; 9 4.445,4.6; 10 3.175,4.6; 11 1.905,4.6; 12 0.635,4.6; 13 -0.635,4.6; 14 -1.905,4.6; 15 -3.175,4.6; 16 -4.445,4.6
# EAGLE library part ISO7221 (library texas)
DUAL DIGITAL ISOLATORS Source: http://focus.ti.com/lit/ds/symlink/iso7221a.pdf

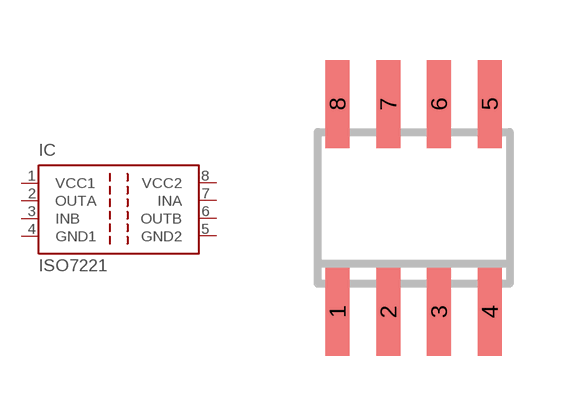
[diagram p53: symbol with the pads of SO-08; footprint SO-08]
Designator prefix IC

## ISO7221A (MPN: ISO7221AD; OC_FARNELL: 1390651; OC_NEWARK: 48M0672), ISO7221B (MPN: ISO7221BD; OC_FARNELL: 1600639; OC_NEWARK: 94M7889), ISO7221C (MPN: ISO7221CD; OC_FARNELL: 1390645; OC_NEWARK: 61M6993), ISO7221M (MPN: ISO7221MD; OC_FARNELL: 1390647; OC_NEWARK: 48M0676)  [SO-08]
1  VCC1  pwr
2  OUTA  out
3  INB  in
4  GND1  pwr
5  GND2  pwr
6  OUTB  out
7  INA  in
8  VCC2  pwr

## Footprint SO-08 (pad centres in mm)
D (R-PDSO-G8) Plastic Small Outline Package Source: http://focus.ti.com/lit/ds/symlink/sn65als176.pdf
smd 0.6 x 2.2: 1 -1.905,-2.6; 2 -0.635,-2.6; 3 0.635,-2.6; 4 1.905,-2.6; 5 1.905,2.6; 6 0.635,2.6; 7 -0.635,2.6; 8 -1.905,2.6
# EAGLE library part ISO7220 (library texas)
DUAL DIGITAL ISOLATORS Source: http://focus.ti.com/lit/ds/symlink/iso7221a.pdf

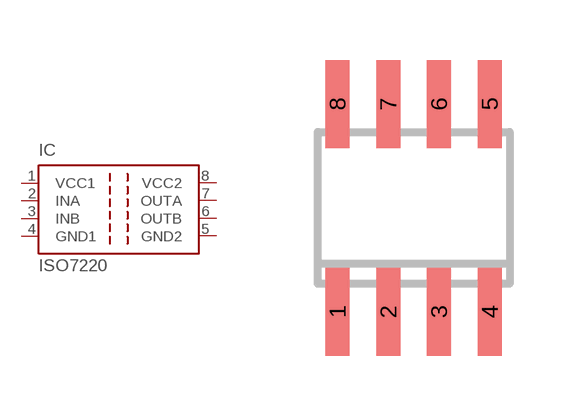
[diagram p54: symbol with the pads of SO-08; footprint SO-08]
Designator prefix IC

## ISO7220A (MPN: ISO7220AD; OC_FARNELL: 1390649; OC_NEWARK: 48M0666), ISO7220B (MPN: ISO7220BD; OC_FARNELL: 1600638; OC_NEWARK: 94M7887), ISO7220C (MPN: ISO7220CD; OC_FARNELL: 1390644; OC_NEWARK: 48M0668), ISO7220M (MPN: ISO7220MD; OC_FARNELL: 1390646; OC_NEWARK: 61M6991)  [SO-08]
1  VCC1  pwr
2  INA  in
3  INB  in
4  GND1  pwr
5  GND2  pwr
6  OUTB  out
7  OUTA  out
8  VCC2  pwr

## Footprint SO-08 (pad centres in mm)
D (R-PDSO-G8) Plastic Small Outline Package Source: http://focus.ti.com/lit/ds/symlink/sn65als176.pdf
smd 0.6 x 2.2: 1 -1.905,-2.6; 2 -0.635,-2.6; 3 0.635,-2.6; 4 1.905,-2.6; 5 1.905,2.6; 6 0.635,2.6; 7 -0.635,2.6; 8 -1.905,2.6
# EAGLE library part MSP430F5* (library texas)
MIXED SIGNAL MICROCONTROLLER Auto generated by make-symbol-device-package-bsdl.ulp Rev. 27 Source: www.ti.com .. msp430f5437.pdf

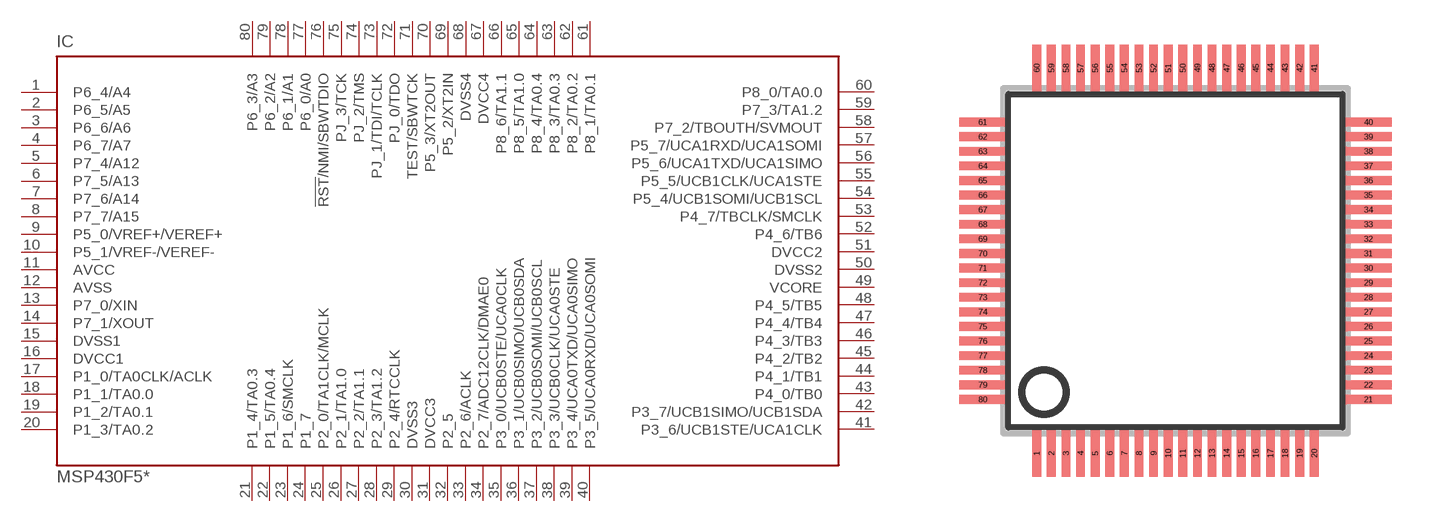
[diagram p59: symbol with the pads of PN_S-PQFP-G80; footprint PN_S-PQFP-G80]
Designator prefix IC

## MSP430F5418 (MPN: MSP430F5418IPN; OC_FARNELL: 1740334; OC_NEWARK: 84R7421), MSP430F5418A (MPN: MSP430F5418AIPN; OC_FARNELL: 1740334; OC_NEWARK: 68R9290), MSP430F5435 (MPN: MSP430F5435AIPN; OC_FARNELL: 1740336; OC_NEWARK: 68R9296), MSP430F5435A (MPN: MSP430F5435AIPN; OC_FARNELL: 1740336; OC_NEWARK: 68R9296), MSP430F5437 (MPN: MSP430F5437IPN; OC_FARNELL: 1740339; OC_NEWARK: 87R0103), MSP430F5437A (MPN: MSP430F5437AIPN; OC_FARNELL: unknown; OC_NEWARK: 68R9302)  [PN_S-PQFP-G80]
1  P6_4/A4
2  P6_5/A5
3  P6_6/A6
4  P6_7/A7
5  P7_4/A12
6  P7_5/A13
7  P7_6/A14
8  P7_7/A15
9  P5_0/VREF+/VEREF+
10  P5_1/VREF-/VEREF-
11  AVCC  pwr
12  AVSS  pwr
13  P7_0/XIN
14  P7_1/XOUT
15  DVSS1  pwr
16  DVCC1  pwr
17  P1_0/TA0CLK/ACLK
18  P1_1/TA0.0
19  P1_2/TA0.1
20  P1_3/TA0.2
21  P1_4/TA0.3
22  P1_5/TA0.4
23  P1_6/SMCLK
24  P1_7
25  P2_0/TA1CLK/MCLK
26  P2_1/TA1.0
27  P2_2/TA1.1
28  P2_3/TA1.2
29  P2_4/RTCCLK
30  DVSS3  pwr
31  DVCC3  pwr
32  P2_5
33  P2_6/ACLK
34  P2_7/ADC12CLK/DMAE0
35  P3_0/UCB0STE/UCA0CLK
36  P3_1/UCB0SIMO/UCB0SDA
37  P3_2/UCB0SOMI/UCB0SCL
38  P3_3/UCB0CLK/UCA0STE
39  P3_4/UCA0TXD/UCA0SIMO
40  P3_5/UCA0RXD/UCA0SOMI
41  P3_6/UCB1STE/UCA1CLK
42  P3_7/UCB1SIMO/UCB1SDA
43  P4_0/TB0
44  P4_1/TB1
45  P4_2/TB2
46  P4_3/TB3
47  P4_4/TB4
48  P4_5/TB5
49  VCORE  pwr
50  DVSS2  pwr
51  DVCC2  pwr
52  P4_6/TB6
53  P4_7/TBCLK/SMCLK
54  P5_4/UCB1SOMI/UCB1SCL
55  P5_5/UCB1CLK/UCA1STE
56  P5_6/UCA1TXD/UCA1SIMO
57  P5_7/UCA1RXD/UCA1SOMI
58  P7_2/TBOUTH/SVMOUT
59  P7_3/TA1.2
60  P8_0/TA0.0
61  P8_1/TA0.1
62  P8_2/TA0.2
63  P8_3/TA0.3
64  P8_4/TA0.4
65  P8_5/TA1.0
66  P8_6/TA1.1
67  DVCC4  pwr
68  DVSS4  pwr
69  P5_2/XT2IN
70  P5_3/XT2OUT
71  TEST/SBWTCK  in
72  PJ_0/TDO
73  PJ_1/TDI/TCLK
74  PJ_2/TMS
75  PJ_3/TCK
76  !RST!/NMI/SBWTDIO
77  P6_0/A0
78  P6_1/A1
79  P6_2/A2
80  P6_3/A3

## Footprint PN_S-PQFP-G80 (pad centres in mm)
QFP80 Source: www.ti.com .. msp430f5437.pdf
smd 0.3 x 1.6: 1 -4.75,-6.6; 2 -4.25,-6.6; 3 -3.75,-6.6; 4 -3.25,-6.6; 5 -2.75,-6.6; 6 -2.25,-6.6; 7 -1.75,-6.6; 8 -1.25,-6.6; 9 -0.75,-6.6; 10 -0.25,-6.6; 11 0.25,-6.6; 12 0.75,-6.6; 13 1.25,-6.6; 14 1.75,-6.6; 15 2.25,-6.6; 16 2.75,-6.6; 17 3.25,-6.6; 18 3.75,-6.6; 19 4.25,-6.6; 20 4.75,-6.6; 41 4.75,6.6; 42 4.25,6.6; 43 3.75,6.6; 44 3.25,6.6; 45 2.75,6.6; 46 2.25,6.6; 47 1.75,6.6; 48 1.25,6.6; 49 0.75,6.6; 50 0.25,6.6; 51 -0.25,6.6; 52 -0.75,6.6; 53 -1.25,6.6; 54 -1.75,6.6; 55 -2.25,6.6; 56 -2.75,6.6; 57 -3.25,6.6; 58 -3.75,6.6; 59 -4.25,6.6; 60 -4.75,6.6
smd 1.6 x 0.3: 21 6.6,-4.75; 22 6.6,-4.25; 23 6.6,-3.75; 24 6.6,-3.25; 25 6.6,-2.75; 26 6.6,-2.25; 27 6.6,-1.75; 28 6.6,-1.25; 29 6.6,-0.75; 30 6.6,-0.25; 31 6.6,0.25; 32 6.6,0.75; 33 6.6,1.25; 34 6.6,1.75; 35 6.6,2.25; 36 6.6,2.75; 37 6.6,3.25; 38 6.6,3.75; 39 6.6,4.25; 40 6.6,4.75; 61 -6.6,4.75; 62 -6.6,4.25; 63 -6.6,3.75; 64 -6.6,3.25; 65 -6.6,2.75; 66 -6.6,2.25; 67 -6.6,1.75; 68 -6.6,1.25; 69 -6.6,0.75; 70 -6.6,0.25; 71 -6.6,-0.25; 72 -6.6,-0.75; 73 -6.6,-1.25; 74 -6.6,-1.75; 75 -6.6,-2.25; 76 -6.6,-2.75; 77 -6.6,-3.25; 78 -6.6,-3.75; 79 -6.6,-4.25; 80 -6.6,-4.75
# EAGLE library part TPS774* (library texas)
250-mA LDO REGULATORS WITH POWER GOOD OUTPUT WITH 8-PIN MSOP PACKAGING Source: http://focus.ti.com/lit/ds/symlink/tps77333.pdf

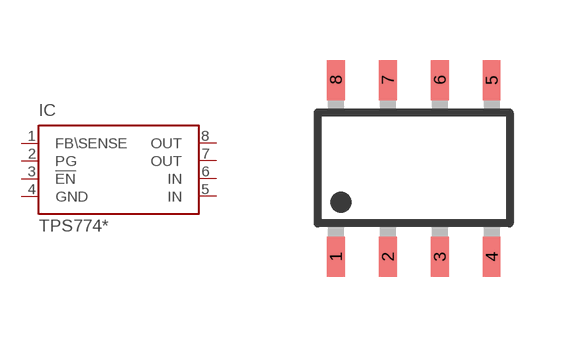
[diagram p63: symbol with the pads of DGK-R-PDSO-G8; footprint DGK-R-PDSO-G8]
Designator prefix IC

## TPS774 (OC_FARNELL: 1412896; OC_NEWARK: unknown)  [DGK-R-PDSO-G8]
1  FB\SENSE  in
2  PG  in
3  !EN  in
4  GND  pwr
5  IN  in
6  IN  in
7  OUT  out
8  OUT  pas

## Footprint DGK-R-PDSO-G8 (pad centres in mm)
DGK (R-PDSO-G8) Source: http://focus.ti.com/lit/ds/symlink/tps77333.pdf
smd 0.45 x 1: 1 -1.95,-2.21; 2 -0.65,-2.21; 3 0.65,-2.21; 4 1.95,-2.21; 5 1.95,2.21; 6 0.65,2.21; 7 -0.65,2.21; 8 -1.95,2.21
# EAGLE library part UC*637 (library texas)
Switched Mode Controller for DC Motor Drive Source: http://focus.ti.com/lit/ds/symlink/uc3637.pdf

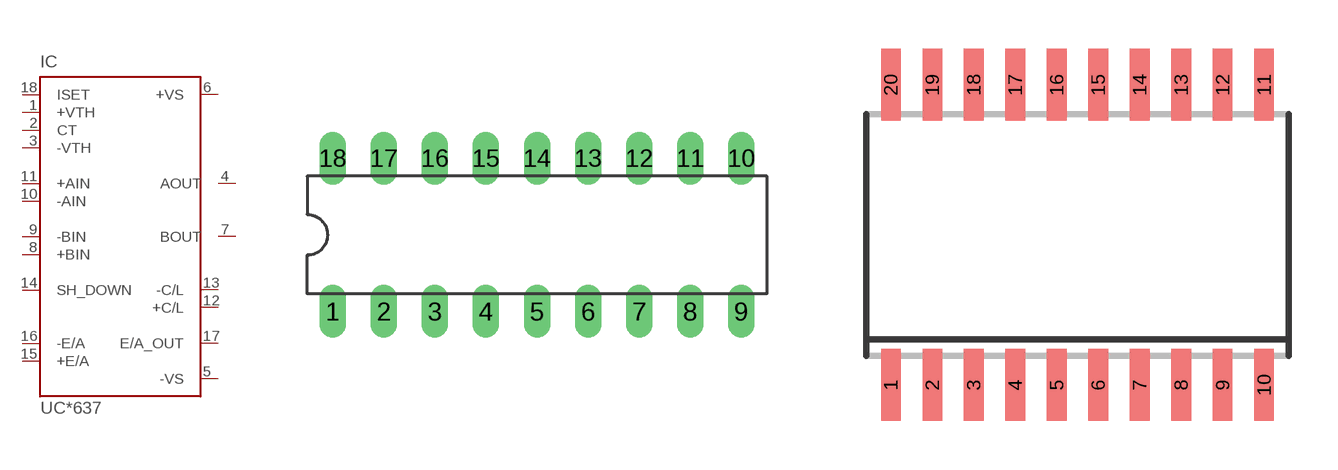
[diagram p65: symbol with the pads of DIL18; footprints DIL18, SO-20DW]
Designator prefix IC

## UC2637N (MF: TEXAS INSTRUMENTS; MPN: UC2637N; OC_FARNELL: 1207367; OC_NEWARK: 77C2829), UC3637N (MF: TEXAS INSTRUMENTS; MPN: UC3637N; OC_FARNELL: 1107292; OC_NEWARK: 62K3473)  [DIL18]
1  +VTH  in
2  CT  pas
3  -VTH  in
4  AOUT  out
5  -VS  in
6  +VS  in
7  BOUT  out
8  +BIN  in
9  -BIN  in
10  -AIN  in
11  +AIN  in
12  +C/L  in
13  -C/L  in
14  SH_DOWN  in
15  +E/A  in
16  -E/A  in
17  E/A_OUT  out
18  ISET  in

## UC2637DW (MF: TEXAS INSTRUMENTS; MPN: UC2637DW; OC_FARNELL: unknown; OC_NEWARK: 77C2827), UC3637DW (MF: TEXAS INSTRUMENTS; MPN: UC3637DW; OC_FARNELL: 1212378; OC_NEWARK: 77C3168)  [SO-20DW]
1  +VTH  in
2  CT  pas
3  -VTH  in
4  AOUT  out
5  -VS  in
6  +VS  in
7  BOUT  out
8  +BIN  in
9  -BIN  in
12  -AIN  in
13  +AIN  in
14  +C/L  in
15  -C/L  in
16  SH_DOWN  in
17  +E/A  in
18  -E/A  in
19  E/A_OUT  out
20  ISET  in

## UC2637Q (MF: TEXAS INSTRUMENT CONNECTORS; MPN: UC2637Q; OC_FARNELL: 1510339; OC_NEWARK: 77C2830), UC3637Q (MF: TEXAS INSTRUMENT CONNECTORS; MPN: UC3637Q; OC_FARNELL: 1413281; OC_NEWARK: 05C3766)  [PLCC20]
1  +VTH  in
2  CT  pas
3  -VTH  in
4  AOUT  out
5  -VS  in
7  +VS  in
8  BOUT  out
9  +BIN  in
10  -BIN  in
11  -AIN  in
12  +AIN  in
13  +C/L  in
14  -C/L  in
15  SH_DOWN  in
17  +E/A  in
18  -E/A  in
19  E/A_OUT  out
20  ISET  in

## UC1637J (OC_FARNELL: unknown; OC_NEWARK: unknown)  [DIL18]
Pads as for DIL18

## Footprint DIL18 (pad centres in mm)
Dual In Line Package
drill 0.813 long: 1 -10.16,-3.81; 2 -7.62,-3.81; 3 -5.08,-3.81; 4 -2.54,-3.81; 5 0,-3.81; 6 2.54,-3.81; 7 5.08,-3.81; 8 7.62,-3.81; 9 10.16,-3.81; 10 10.16,3.81; 11 7.62,3.81; 12 5.08,3.81; 13 2.54,3.81; 14 0,3.81; 15 -2.54,3.81; 16 -5.08,3.81; 17 -7.62,3.81; 18 -10.16,3.81

## Footprint SO-20DW (pad centres in mm)
Small Outline Integrated Circuit wide
smd 0.6 x 2.2: 1 -5.715,-4.6; 2 -4.445,-4.6; 3 -3.175,-4.6; 4 -1.905,-4.6; 5 -0.635,-4.6; 6 0.635,-4.6; 7 1.905,-4.6; 8 3.175,-4.6; 9 4.445,-4.6; 10 5.715,-4.6; 11 5.715,4.6; 12 4.445,4.6; 13 3.175,4.6; 14 1.905,4.6; 15 0.635,4.6; 16 -0.635,4.6; 17 -1.905,4.6; 18 -3.175,4.6; 19 -4.445,4.6; 20 -5.715,4.6

## Footprint PLCC20 (pad centres in mm)
Plastic Leaded Chip Carrier
smd 0.6 x 2.2: 1 0,4.3; 2 -1.27,4.3; 3 -2.54,4.3; 9 -2.54,-4.3; 10 -1.27,-4.3; 11 0,-4.3; 12 1.27,-4.3; 13 2.54,-4.3; 19 2.54,4.3; 20 1.27,4.3
smd 2.2 x 0.6: 4 -4.3,2.54; 5 -4.3,1.27; 6 -4.3,0; 7 -4.3,-1.27; 8 -4.3,-2.54; 14 4.3,-2.54; 15 4.3,-1.27; 16 4.3,0; 17 4.3,1.27; 18 4.3,2.54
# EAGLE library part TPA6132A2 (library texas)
25-mW DIRECTPATH (TM) STEREO HEADPHONE AMPLIFIER WITH POP SUPPRESSION Source: www.ti.com .. tpa6132a2 direct path stereo $.65.pdf

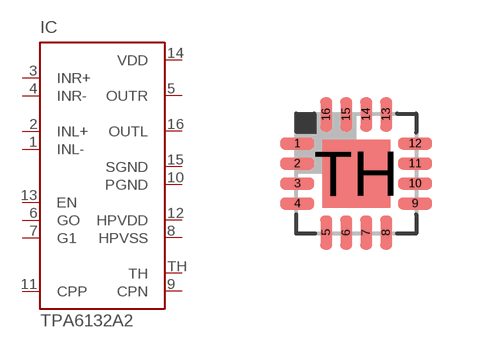
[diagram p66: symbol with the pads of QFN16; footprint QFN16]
Designator prefix IC

## TPA6132A2 (MPN: TPA6132A2RTET; OC_FARNELL: 1697167; OC_NEWARK: 46P3781)  [QFN16]
1  INL-  in
2  INL+  in
3  INR+  in
4  INR-  in
5  OUTR  out
6  GO  in
7  G1  in
8  HPVSS  pas
9  CPN  pas
10  PGND  pwr
11  CPP  pas
12  HPVDD  pas
13  EN  in
14  VDD  pwr
15  SGND  pwr
16  OUTL  out
TH  TH  pas

## Footprint QFN16 (pad centres in mm)
RTE (S-PQFP-N16) 3x3 mm Source: www.ti.com .. tpa6132a2 direct path stereo $.65.pdf
smd 0.85 x 0.3: 1 -1.475,0.75; 2 -1.475,0.25; 3 -1.475,-0.25; 4 -1.475,-0.75; 9 1.475,-0.75; 10 1.475,-0.25; 11 1.475,0.25; 12 1.475,0.75
smd 0.3 x 0.85: 5 -0.75,-1.475; 6 -0.25,-1.475; 7 0.25,-1.475; 8 0.75,-1.475; 13 0.75,1.475; 14 0.25,1.475; 15 -0.25,1.475; 16 -0.75,1.475
smd 1.7 x 1.7: TH 0,0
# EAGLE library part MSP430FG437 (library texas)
MIXED SIGNAL MICROCONTROLLER Auto generated by make-symbol-device-package-bsdl.ulp Rev. 29 Source: http://focus.ti.com/lit/ds/symlink/msp430fg437.pdf

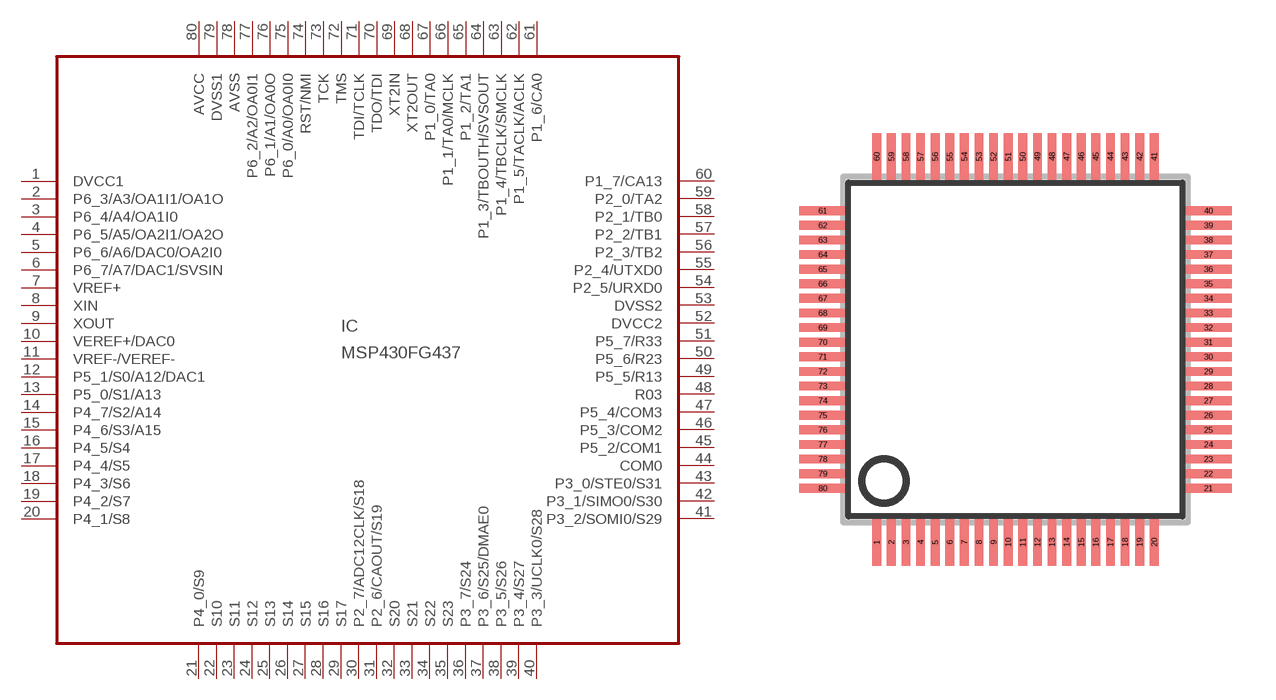
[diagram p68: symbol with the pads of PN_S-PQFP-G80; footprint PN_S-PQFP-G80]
Designator prefix IC

## MSP430FG437 (MPN: MSP430FG437IPN; OC_FARNELL: 1471275; OC_NEWARK: 61M7844)  [PN_S-PQFP-G80]
1  DVCC1  pwr
2  P6_3/A3/OA1I1/OA1O
3  P6_4/A4/OA1I0
4  P6_5/A5/OA2I1/OA2O
5  P6_6/A6/DAC0/OA2I0
6  P6_7/A7/DAC1/SVSIN
7  VREF+  out
8  XIN  in
9  XOUT  out
10  VEREF+/DAC0
11  VREF-/VEREF-  in
12  P5_1/S0/A12/DAC1
13  P5_0/S1/A13
14  P4_7/S2/A14
15  P4_6/S3/A15
16  P4_5/S4
17  P4_4/S5
18  P4_3/S6
19  P4_2/S7
20  P4_1/S8
21  P4_0/S9
22  S10  out
23  S11  out
24  S12  out
25  S13  out
26  S14  out
27  S15  out
28  S16  out
29  S17  out
30  P2_7/ADC12CLK/S18
31  P2_6/CAOUT/S19
32  S20  out
33  S21  out
34  S22  out
35  S23  out
36  P3_7/S24
37  P3_6/S25/DMAE0
38  P3_5/S26
39  P3_4/S27
40  P3_3/UCLK0/S28
41  P3_2/SOMI0/S29
42  P3_1/SIMO0/S30
43  P3_0/STE0/S31
44  COM0  out
45  P5_2/COM1
46  P5_3/COM2
47  P5_4/COM3
48  R03  in
49  P5_5/R13
50  P5_6/R23
51  P5_7/R33
52  DVCC2  pwr
53  DVSS2  pwr
54  P2_5/URXD0
55  P2_4/UTXD0
56  P2_3/TB2
57  P2_2/TB1
58  P2_1/TB0
59  P2_0/TA2
60  P1_7/CA13
61  P1_6/CA0
62  P1_5/TACLK/ACLK
63  P1_4/TBCLK/SMCLK
64  P1_3/TBOUTH/SVSOUT
65  P1_2/TA1
66  P1_1/TA0/MCLK
67  P1_0/TA0
68  XT2OUT  out
69  XT2IN  in
70  TDO/TDI
71  TDI/TCLK  in
72  TMS  in
73  TCK  in
74  RST/NMI  in
75  P6_0/A0/OA0I0
76  P6_1/A1/OA0O
77  P6_2/A2/OA0I1
78  AVSS  pwr
79  DVSS1  pwr
80  AVCC  pwr

## Footprint PN_S-PQFP-G80 (pad centres in mm)
QFP80 Source: www.ti.com .. msp430f5437.pdf
smd 0.3 x 1.6: 1 -4.75,-6.6; 2 -4.25,-6.6; 3 -3.75,-6.6; 4 -3.25,-6.6; 5 -2.75,-6.6; 6 -2.25,-6.6; 7 -1.75,-6.6; 8 -1.25,-6.6; 9 -0.75,-6.6; 10 -0.25,-6.6; 11 0.25,-6.6; 12 0.75,-6.6; 13 1.25,-6.6; 14 1.75,-6.6; 15 2.25,-6.6; 16 2.75,-6.6; 17 3.25,-6.6; 18 3.75,-6.6; 19 4.25,-6.6; 20 4.75,-6.6; 41 4.75,6.6; 42 4.25,6.6; 43 3.75,6.6; 44 3.25,6.6; 45 2.75,6.6; 46 2.25,6.6; 47 1.75,6.6; 48 1.25,6.6; 49 0.75,6.6; 50 0.25,6.6; 51 -0.25,6.6; 52 -0.75,6.6; 53 -1.25,6.6; 54 -1.75,6.6; 55 -2.25,6.6; 56 -2.75,6.6; 57 -3.25,6.6; 58 -3.75,6.6; 59 -4.25,6.6; 60 -4.75,6.6
smd 1.6 x 0.3: 21 6.6,-4.75; 22 6.6,-4.25; 23 6.6,-3.75; 24 6.6,-3.25; 25 6.6,-2.75; 26 6.6,-2.25; 27 6.6,-1.75; 28 6.6,-1.25; 29 6.6,-0.75; 30 6.6,-0.25; 31 6.6,0.25; 32 6.6,0.75; 33 6.6,1.25; 34 6.6,1.75; 35 6.6,2.25; 36 6.6,2.75; 37 6.6,3.25; 38 6.6,3.75; 39 6.6,4.25; 40 6.6,4.75; 61 -6.6,4.75; 62 -6.6,4.25; 63 -6.6,3.75; 64 -6.6,3.25; 65 -6.6,2.75; 66 -6.6,2.25; 67 -6.6,1.75; 68 -6.6,1.25; 69 -6.6,0.75; 70 -6.6,0.25; 71 -6.6,-0.25; 72 -6.6,-0.75; 73 -6.6,-1.25; 74 -6.6,-1.75; 75 -6.6,-2.25; 76 -6.6,-2.75; 77 -6.6,-3.25; 78 -6.6,-3.75; 79 -6.6,-4.25; 80 -6.6,-4.75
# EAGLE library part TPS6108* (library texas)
HIGH VOLTAGE DC/DC BOOST CONVERTER WITH 0.5-A/1.3-A INTEGRATED SWITCH Source: www.ti.com .. tps61081[1].pdf

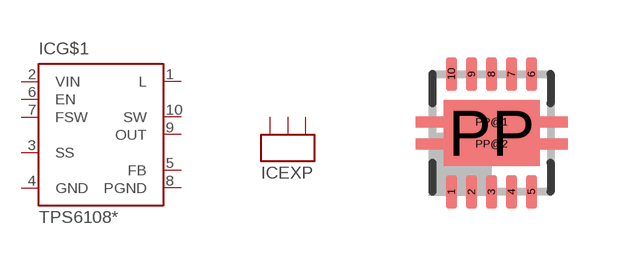
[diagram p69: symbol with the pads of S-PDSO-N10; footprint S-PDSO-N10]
Designator prefix IC; gates G$1=TPS6108 EXP=EXP-3

## TPS61080 (MPN: TPS61080DRCT; OC_FARNELL: 1412517; OC_NEWARK: 30M1831), TPS61081 (MPN: TPS61081DRCT; OC_FARNELL: 1412518; OC_NEWARK: 30M1833)  [S-PDSO-N10]
1  G$1:L  pas
2  G$1:VIN  in
3  G$1:SS  in
4  G$1:GND  pwr
5  G$1:FB  in
6  G$1:EN  in
7  G$1:FSW  in
8  G$1:PGND  in
9  G$1:OUT  out
10  G$1:SW  pas
PP  EXP:EXP  in
PP@1  EXP:EXP  in
PP@2  EXP:EXP  in

## Footprint S-PDSO-N10 (pad centres in mm)
QFN 10 3 x 3 mm Source: http://focus.ti.com/lit/ds/symlink/tps61200.pdf
smd 0.28 x 0.85: 1 -1,-1.475; 2 -0.5,-1.475; 3 0,-1.475; 4 0.5,-1.475; 5 1,-1.475; 6 1,1.475; 7 0.5,1.475; 8 0,1.475; 9 -0.5,1.475; 10 -1,1.475
smd 2.4 x 1.65: PP 0,0
smd 3.8 x 0.28: PP@1 0,0.275; PP@2 0,-0.275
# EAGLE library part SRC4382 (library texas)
Two-Channel, Asynchronous Sample Rate Converter with Integrated Digital Audio Interface Receiver and Transmitter Auto generated by make-symbol-device-package-bsdl.ulp Rev. 29 Source: http://focus.ti.com/lit/ds/symlink/src4382.pdf

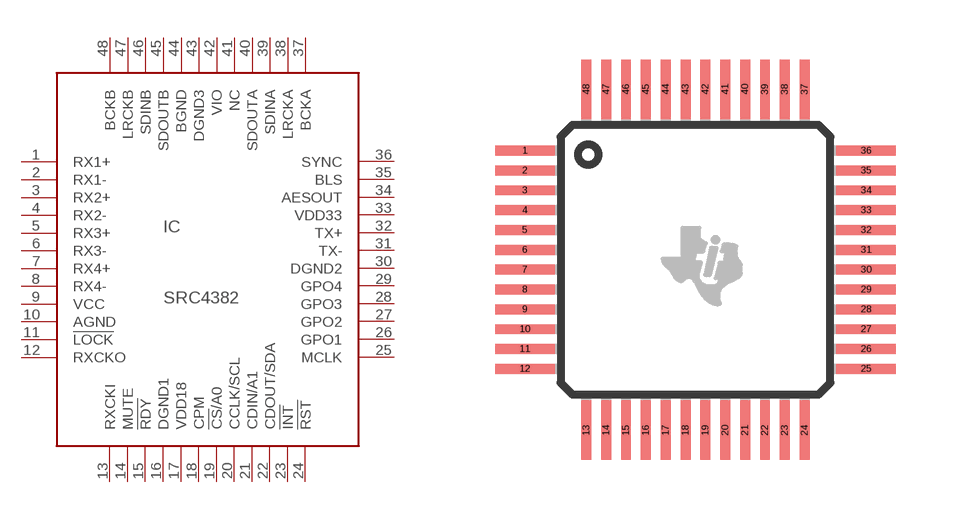
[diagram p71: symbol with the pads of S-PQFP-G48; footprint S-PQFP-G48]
Designator prefix IC

## SRC4382 (MPN: SRC4382IPFB; OC_FARNELL: 1755339; OC_NEWARK: 99K4322)  [S-PQFP-G48]
1  RX1+  in
2  RX1-  in
3  RX2+  in
4  RX2-  in
5  RX3+  in
6  RX3-  in
7  RX4+  in
8  RX4-  in
9  VCC  pwr
10  AGND  pwr
11  !LOCK  out
12  RXCKO  out
13  RXCKI  in
14  MUTE  in
15  !RDY  out
16  DGND1  pwr
17  VDD18  pwr
18  CPM  in
19  !CS!/A0  in
20  CCLK/SCL  in
21  CDIN/A1  in
22  CDOUT/SDA
23  !INT  out
24  !RST  in
25  MCLK  in
26  GPO1  out
27  GPO2  out
28  GPO3  out
29  GPO4  out
30  DGND2  pwr
31  TX-  out
32  TX+  out
33  VDD33  pwr
34  AESOUT  out
35  BLS
36  SYNC  out
37  BCKA
38  LRCKA
39  SDINA  in
40  SDOUTA  out
41  NC  nc
42  VIO  pwr
43  DGND3  pwr
44  BGND  pwr
45  SDOUTB  out
46  SDINB  in
47  LRCKB
48  BCKB

## Footprint S-PQFP-G48 (pad centres in mm)
PFB (S-PQFP-G48) Source: http://focus.ti.com/lit/ds/symlink/src4392.pdf
smd 1.5 x 0.25: 1 -4.3,2.75; 2 -4.3,2.25; 3 -4.3,1.75; 4 -4.3,1.25; 5 -4.3,0.75; 6 -4.3,0.25; 7 -4.3,-0.25; 8 -4.3,-0.75; 9 -4.3,-1.25; 10 -4.3,-1.75; 11 -4.3,-2.25; 12 -4.3,-2.75; 25 4.3,-2.75; 26 4.3,-2.25; 27 4.3,-1.75; 28 4.3,-1.25; 29 4.3,-0.75; 30 4.3,-0.25; 31 4.3,0.25; 32 4.3,0.75; 33 4.3,1.25; 34 4.3,1.75; 35 4.3,2.25; 36 4.3,2.75
smd 0.25 x 1.5: 13 -2.75,-4.3; 14 -2.25,-4.3; 15 -1.75,-4.3; 16 -1.25,-4.3; 17 -0.75,-4.3; 18 -0.25,-4.3; 19 0.25,-4.3; 20 0.75,-4.3; 21 1.25,-4.3; 22 1.75,-4.3; 23 2.25,-4.3; 24 2.75,-4.3; 37 2.75,4.3; 38 2.25,4.3; 39 1.75,4.3; 40 1.25,4.3; 41 0.75,4.3; 42 0.25,4.3; 43 -0.25,4.3; 44 -0.75,4.3; 45 -1.25,4.3; 46 -1.75,4.3; 47 -2.25,4.3; 48 -2.75,4.3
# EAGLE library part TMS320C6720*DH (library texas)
Floating-Point Digital Signal Processors TMS320C6727B, TMS320C6726B, TMS320C6722B, TMS320C6720 Auto generated by make-symbol-device-package-bsdl.ulp Rev. 29 Source: http://focus.ti.com/lit/ds/symlink/tms320c6720.pdf

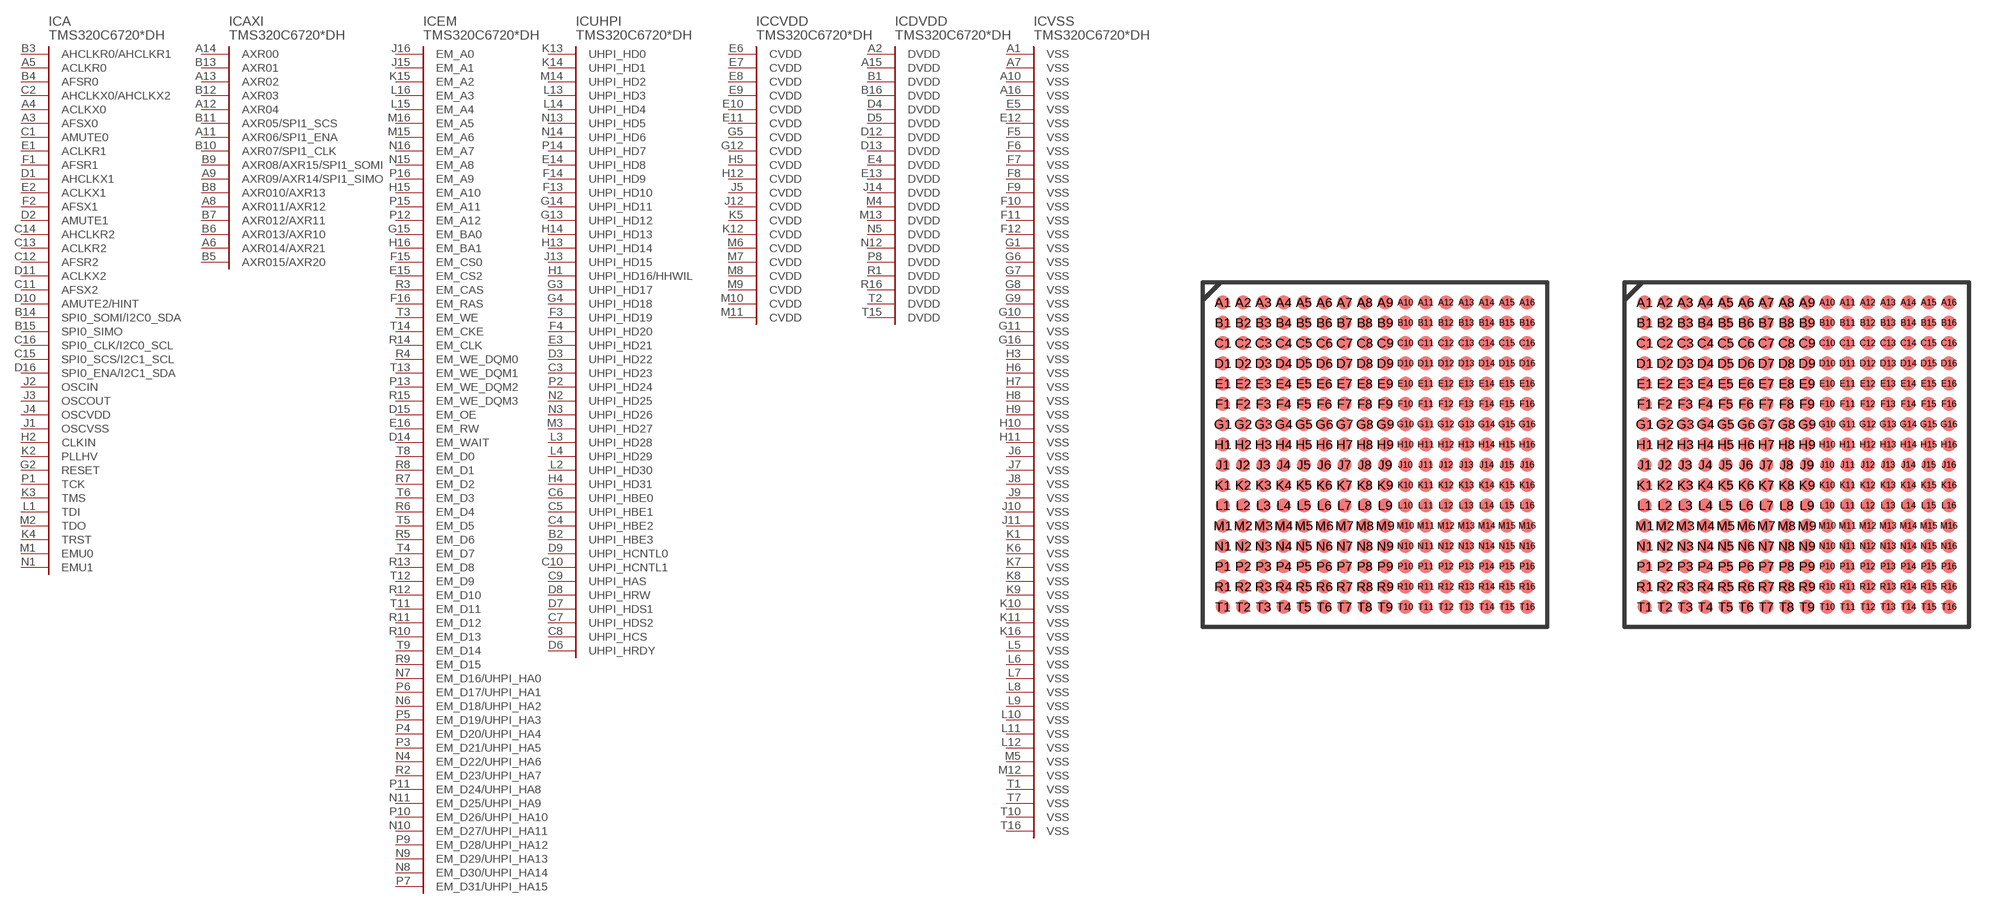
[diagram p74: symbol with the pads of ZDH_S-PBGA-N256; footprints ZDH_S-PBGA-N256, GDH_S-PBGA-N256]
Designator prefix IC; gates A=TMS320C6720-1 AXI=TMS320C6720-AXI EM=TMS320C6720-EM UHPI=TMS320C6720-UHPI CVDD=TMS320C6720-CVDD DVDD=TMS320C6720-DVDD VSS=TMS320C6720-VSS

## TMS320C6720DHZ (OC_FARNELL: unknown; OC_NEWARK: unknown)  [ZDH_S-PBGA-N256]
A1  VSS:VSS  pwr
A2  DVDD:DVDD  pwr
A3  A:AFSX0
A4  A:ACLKX0
A5  A:ACLKR0
A6  AXI:AXR014/AXR21
A7  VSS:VSS  pwr
A8  AXI:AXR011/AXR12
A9  AXI:AXR09/AXR14/SPI1_SIMO
A10  VSS:VSS  pwr
A11  AXI:AXR06/SPI1_ENA
A12  AXI:AXR04
A13  AXI:AXR02
A14  AXI:AXR00
A15  DVDD:DVDD  pwr
A16  VSS:VSS  pwr
B1  DVDD:DVDD  pwr
B2  UHPI:UHPI_HBE3  in
B3  A:AHCLKR0/AHCLKR1
B4  A:AFSR0
B5  AXI:AXR015/AXR20
B6  AXI:AXR013/AXR10
B7  AXI:AXR012/AXR11
B8  AXI:AXR010/AXR13
B9  AXI:AXR08/AXR15/SPI1_SOMI
B10  AXI:AXR07/SPI1_CLK
B11  AXI:AXR05/SPI1_SCS
B12  AXI:AXR03
B13  AXI:AXR01
B14  A:SPI0_SOMI/I2C0_SDA
B15  A:SPI0_SIMO
B16  DVDD:DVDD  pwr
C1  A:AMUTE0  out
C2  A:AHCLKX0/AHCLKX2
C3  UHPI:UHPI_HD23
C4  UHPI:UHPI_HBE2  in
C5  UHPI:UHPI_HBE1  in
C6  UHPI:UHPI_HBE0  in
C7  UHPI:UHPI_HDS2  in
C8  UHPI:UHPI_HCS  in
C9  UHPI:UHPI_HAS  in
C10  UHPI:UHPI_HCNTL1  in
C11  A:AFSX2
C12  A:AFSR2
C13  A:ACLKR2
C14  A:AHCLKR2
C15  A:SPI0_SCS/I2C1_SCL
C16  A:SPI0_CLK/I2C0_SCL
D1  A:AHCLKX1
D2  A:AMUTE1  out
D3  UHPI:UHPI_HD22
D4  DVDD:DVDD  pwr
D5  DVDD:DVDD  pwr
D6  UHPI:UHPI_HRDY  out
D7  UHPI:UHPI_HDS1  in
D8  UHPI:UHPI_HRW  in
D9  UHPI:UHPI_HCNTL0  in
D10  A:AMUTE2/HINT  out
D11  A:ACLKX2
D12  DVDD:DVDD  pwr
D13  DVDD:DVDD  pwr
D14  EM:EM_WAIT  in
D15  EM:EM_OE  out
D16  A:SPI0_ENA/I2C1_SDA
E1  A:ACLKR1
E2  A:ACLKX1
E3  UHPI:UHPI_HD21
E4  DVDD:DVDD  pwr
E5  VSS:VSS  pwr
E6  CVDD:CVDD  pwr
E7  CVDD:CVDD  pwr
E8  CVDD:CVDD  pwr
E9  CVDD:CVDD  pwr
E10  CVDD:CVDD  pwr
E11  CVDD:CVDD  pwr
E12  VSS:VSS  pwr
E13  DVDD:DVDD  pwr
E14  UHPI:UHPI_HD8
E15  EM:EM_CS2  out
E16  EM:EM_RW  out
F1  A:AFSR1
F2  A:AFSX1
F3  UHPI:UHPI_HD19
F4  UHPI:UHPI_HD20
F5  VSS:VSS  pwr
F6  VSS:VSS  pwr
F7  VSS:VSS  pwr
F8  VSS:VSS  pwr
F9  VSS:VSS  pwr
F10  VSS:VSS  pwr
F11  VSS:VSS  pwr
F12  VSS:VSS  pwr
F13  UHPI:UHPI_HD10
F14  UHPI:UHPI_HD9
F15  EM:EM_CS0  out
F16  EM:EM_RAS  out
G1  VSS:VSS  pwr
G2  A:RESET  in
G3  UHPI:UHPI_HD17
G4  UHPI:UHPI_HD18
G5  CVDD:CVDD  pwr
G6  VSS:VSS  pwr
G7  VSS:VSS  pwr
G8  VSS:VSS  pwr
G9  VSS:VSS  pwr
G10  VSS:VSS  pwr
G11  VSS:VSS  pwr
G12  CVDD:CVDD  pwr
G13  UHPI:UHPI_HD12
G14  UHPI:UHPI_HD11
G15  EM:EM_BA0  out
G16  VSS:VSS  pwr
H1  UHPI:UHPI_HD16/HHWIL
H2  A:CLKIN  in
H3  VSS:VSS  pwr
H4  UHPI:UHPI_HD31
H5  CVDD:CVDD  pwr
H6  VSS:VSS  pwr
H7  VSS:VSS  pwr
H8  VSS:VSS  pwr
H9  VSS:VSS  pwr
H10  VSS:VSS  pwr
H11  VSS:VSS  pwr
H12  CVDD:CVDD  pwr
H13  UHPI:UHPI_HD14
H14  UHPI:UHPI_HD13
H15  EM:EM_A10  out
H16  EM:EM_BA1  out
J1  A:OSCVSS  pwr
J2  A:OSCIN  in
J3  A:OSCOUT  out
J4  A:OSCVDD  pwr
J5  CVDD:CVDD  pwr
J6  VSS:VSS  pwr
J7  VSS:VSS  pwr
J8  VSS:VSS  pwr
J9  VSS:VSS  pwr
J10  VSS:VSS  pwr
J11  VSS:VSS  pwr
J12  CVDD:CVDD  pwr
J13  UHPI:UHPI_HD15
J14  DVDD:DVDD  pwr
J15  EM:EM_A1  out
J16  EM:EM_A0  out
K1  VSS:VSS  pwr
K2  A:PLLHV  pwr
K3  A:TMS  in
K4  A:TRST  in
K5  CVDD:CVDD  pwr
K6  VSS:VSS  pwr
K7  VSS:VSS  pwr
K8  VSS:VSS  pwr
K9  VSS:VSS  pwr
K10  VSS:VSS  pwr
K11  VSS:VSS  pwr
K12  CVDD:CVDD  pwr
K13  UHPI:UHPI_HD0
K14  UHPI:UHPI_HD1
K15  EM:EM_A2  out
K16  VSS:VSS  pwr
L1  A:TDI  in
L2  UHPI:UHPI_HD30
L3  UHPI:UHPI_HD28
L4  UHPI:UHPI_HD29
L5  VSS:VSS  pwr
L6  VSS:VSS  pwr
L7  VSS:VSS  pwr
L8  VSS:VSS  pwr
L9  VSS:VSS  pwr
L10  VSS:VSS  pwr
L11  VSS:VSS  pwr
L12  VSS:VSS  pwr
L13  UHPI:UHPI_HD3
L14  UHPI:UHPI_HD4
L15  EM:EM_A4  out
L16  EM:EM_A3  out
M1  A:EMU0
M2  A:TDO  hiz
M3  UHPI:UHPI_HD27
M4  DVDD:DVDD  pwr
M5  VSS:VSS  pwr
M6  CVDD:CVDD  pwr
M7  CVDD:CVDD  pwr
M8  CVDD:CVDD  pwr
M9  CVDD:CVDD  pwr
M10  CVDD:CVDD  pwr
M11  CVDD:CVDD  pwr
M12  VSS:VSS  pwr
M13  DVDD:DVDD  pwr
M14  UHPI:UHPI_HD2
M15  EM:EM_A6  out
M16  EM:EM_A5  out
N1  A:EMU1
N2  UHPI:UHPI_HD25
N3  UHPI:UHPI_HD26
N4  EM:EM_D22/UHPI_HA6
N5  DVDD:DVDD  pwr
N6  EM:EM_D18/UHPI_HA2
N7  EM:EM_D16/UHPI_HA0
N8  EM:EM_D30/UHPI_HA14
N9  EM:EM_D29/UHPI_HA13
N10  EM:EM_D27/UHPI_HA11
N11  EM:EM_D25/UHPI_HA9
N12  DVDD:DVDD  pwr
N13  UHPI:UHPI_HD5
N14  UHPI:UHPI_HD6
N15  EM:EM_A8  out
N16  EM:EM_A7  out
P1  A:TCK  in
P2  UHPI:UHPI_HD24
P3  EM:EM_D21/UHPI_HA5
P4  EM:EM_D20/UHPI_HA4
P5  EM:EM_D19/UHPI_HA3
P6  EM:EM_D17/UHPI_HA1
P7  EM:EM_D31/UHPI_HA15
P8  DVDD:DVDD  pwr
P9  EM:EM_D28/UHPI_HA12
P10  EM:EM_D26/UHPI_HA10
P11  EM:EM_D24/UHPI_HA8
P12  EM:EM_A12  out
P13  EM:EM_WE_DQM2  out
P14  UHPI:UHPI_HD7
P15  EM:EM_A11  out
P16  EM:EM_A9  out
R1  DVDD:DVDD  pwr
R2  EM:EM_D23/UHPI_HA7
R3  EM:EM_CAS  out
R4  EM:EM_WE_DQM0  out
R5  EM:EM_D6
R6  EM:EM_D4
R7  EM:EM_D2
R8  EM:EM_D1
R9  EM:EM_D15
R10  EM:EM_D13
R11  EM:EM_D12
R12  EM:EM_D10
R13  EM:EM_D8
R14  EM:EM_CLK  out
R15  EM:EM_WE_DQM3  out
R16  DVDD:DVDD  pwr
T1  VSS:VSS  pwr
T2  DVDD:DVDD  pwr
T3  EM:EM_WE  out
T4  EM:EM_D7
T5  EM:EM_D5
T6  EM:EM_D3
T7  VSS:VSS  pwr
T8  EM:EM_D0
T9  EM:EM_D14
T10  VSS:VSS  pwr
T11  EM:EM_D11
T12  EM:EM_D9
T13  EM:EM_WE_DQM1  out
T14  EM:EM_CKE  out
T15  DVDD:DVDD  pwr
T16  VSS:VSS  pwr

## TMS320C6720DHG (OC_FARNELL: unknown; OC_NEWARK: unknown)  [GDH_S-PBGA-N256]
Pads as for ZDH_S-PBGA-N256

## Footprint ZDH_S-PBGA-N256 (pad centres in mm)
ZDH (S-PBGA-N256) PLASTIC BALL GRID ARRAY Auto generated by make-symbol-device-package-bsdl.ulp Rev. 29 Source: http://focus.ti.com/lit/ds/symlink/tms320c6720.pdf
smd 0.7 x 0.7: A1 -7.5,7.5; A2 -6.5,7.5; A3 -5.5,7.5; A4 -4.5,7.5; A5 -3.5,7.5; A6 -2.5,7.5; A7 -1.5,7.5; A8 -0.5,7.5; A9 0.5,7.5; A10 1.5,7.5; A11 2.5,7.5; A12 3.5,7.5; A13 4.5,7.5; A14 5.5,7.5; A15 6.5,7.5; A16 7.5,7.5; B1 -7.5,6.5; B2 -6.5,6.5; B3 -5.5,6.5; B4 -4.5,6.5; B5 -3.5,6.5; B6 -2.5,6.5; B7 -1.5,6.5; B8 -0.5,6.5; B9 0.5,6.5; B10 1.5,6.5; B11 2.5,6.5; B12 3.5,6.5; B13 4.5,6.5; B14 5.5,6.5; B15 6.5,6.5; B16 7.5,6.5; C1 -7.5,5.5; C2 -6.5,5.5; C3 -5.5,5.5; C4 -4.5,5.5; C5 -3.5,5.5; C6 -2.5,5.5; C7 -1.5,5.5; C8 -0.5,5.5; C9 0.5,5.5; C10 1.5,5.5; C11 2.5,5.5; C12 3.5,5.5; C13 4.5,5.5; C14 5.5,5.5; C15 6.5,5.5; C16 7.5,5.5; D1 -7.5,4.5; D2 -6.5,4.5; D3 -5.5,4.5; D4 -4.5,4.5; D5 -3.5,4.5; D6 -2.5,4.5; D7 -1.5,4.5; D8 -0.5,4.5; D9 0.5,4.5; D10 1.5,4.5; D11 2.5,4.5; D12 3.5,4.5; D13 4.5,4.5; D14 5.5,4.5; D15 6.5,4.5; D16 7.5,4.5; E1 -7.5,3.5; E2 -6.5,3.5; E3 -5.5,3.5; E4 -4.5,3.5; E5 -3.5,3.5; E6 -2.5,3.5; E7 -1.5,3.5; E8 -0.5,3.5; E9 0.5,3.5; E10 1.5,3.5; E11 2.5,3.5; E12 3.5,3.5; E13 4.5,3.5; E14 5.5,3.5; E15 6.5,3.5; E16 7.5,3.5; F1 -7.5,2.5; F2 -6.5,2.5; F3 -5.5,2.5; F4 -4.5,2.5; F5 -3.5,2.5; F6 -2.5,2.5; F7 -1.5,2.5; F8 -0.5,2.5; F9 0.5,2.5; F10 1.5,2.5; F11 2.5,2.5; F12 3.5,2.5; F13 4.5,2.5; F14 5.5,2.5; F15 6.5,2.5; F16 7.5,2.5; G1 -7.5,1.5; G2 -6.5,1.5; G3 -5.5,1.5; G4 -4.5,1.5; G5 -3.5,1.5; G6 -2.5,1.5; G7 -1.5,1.5; G8 -0.5,1.5; G9 0.5,1.5; G10 1.5,1.5; G11 2.5,1.5; G12 3.5,1.5; G13 4.5,1.5; G14 5.5,1.5; G15 6.5,1.5; G16 7.5,1.5; H1 -7.5,0.5; H2 -6.5,0.5; H3 -5.5,0.5; H4 -4.5,0.5; H5 -3.5,0.5; H6 -2.5,0.5; H7 -1.5,0.5; H8 -0.5,0.5; H9 0.5,0.5; H10 1.5,0.5; H11 2.5,0.5; H12 3.5,0.5; H13 4.5,0.5; H14 5.5,0.5; H15 6.5,0.5; H16 7.5,0.5; J1 -7.5,-0.5; J2 -6.5,-0.5; J3 -5.5,-0.5; J4 -4.5,-0.5; J5 -3.5,-0.5; J6 -2.5,-0.5; J7 -1.5,-0.5; J8 -0.5,-0.5; J9 0.5,-0.5; J10 1.5,-0.5; J11 2.5,-0.5; J12 3.5,-0.5; J13 4.5,-0.5; J14 5.5,-0.5; J15 6.5,-0.5; J16 7.5,-0.5; K1 -7.5,-1.5; K2 -6.5,-1.5; K3 -5.5,-1.5; K4 -4.5,-1.5; K5 -3.5,-1.5; K6 -2.5,-1.5; K7 -1.5,-1.5; K8 -0.5,-1.5; K9 0.5,-1.5; K10 1.5,-1.5; K11 2.5,-1.5; K12 3.5,-1.5; K13 4.5,-1.5; K14 5.5,-1.5; K15 6.5,-1.5; K16 7.5,-1.5; L1 -7.5,-2.5; L2 -6.5,-2.5; L3 -5.5,-2.5; L4 -4.5,-2.5; L5 -3.5,-2.5; L6 -2.5,-2.5; L7 -1.5,-2.5; L8 -0.5,-2.5; L9 0.5,-2.5; L10 1.5,-2.5; L11 2.5,-2.5; L12 3.5,-2.5; L13 4.5,-2.5; L14 5.5,-2.5; L15 6.5,-2.5; L16 7.5,-2.5; M1 -7.5,-3.5; M2 -6.5,-3.5; M3 -5.5,-3.5; M4 -4.5,-3.5; M5 -3.5,-3.5; M6 -2.5,-3.5; M7 -1.5,-3.5; M8 -0.5,-3.5; M9 0.5,-3.5; M10 1.5,-3.5; M11 2.5,-3.5; M12 3.5,-3.5; M13 4.5,-3.5; M14 5.5,-3.5; M15 6.5,-3.5; M16 7.5,-3.5; N1 -7.5,-4.5; N2 -6.5,-4.5; N3 -5.5,-4.5; N4 -4.5,-4.5; N5 -3.5,-4.5; N6 -2.5,-4.5; N7 -1.5,-4.5; N8 -0.5,-4.5; N9 0.5,-4.5; N10 1.5,-4.5; N11 2.5,-4.5; N12 3.5,-4.5; N13 4.5,-4.5; N14 5.5,-4.5; N15 6.5,-4.5; N16 7.5,-4.5; P1 -7.5,-5.5; P2 -6.5,-5.5; P3 -5.5,-5.5; P4 -4.5,-5.5; P5 -3.5,-5.5; P6 -2.5,-5.5; P7 -1.5,-5.5; P8 -0.5,-5.5; P9 0.5,-5.5; P10 1.5,-5.5; P11 2.5,-5.5; P12 3.5,-5.5; P13 4.5,-5.5; P14 5.5,-5.5; P15 6.5,-5.5; P16 7.5,-5.5; R1 -7.5,-6.5; R2 -6.5,-6.5; R3 -5.5,-6.5; R4 -4.5,-6.5; R5 -3.5,-6.5; R6 -2.5,-6.5; R7 -1.5,-6.5; R8 -0.5,-6.5; R9 0.5,-6.5; R10 1.5,-6.5; R11 2.5,-6.5; R12 3.5,-6.5; R13 4.5,-6.5; R14 5.5,-6.5; R15 6.5,-6.5; R16 7.5,-6.5; T1 -7.5,-7.5; T2 -6.5,-7.5; T3 -5.5,-7.5; T4 -4.5,-7.5; T5 -3.5,-7.5; T6 -2.5,-7.5; T7 -1.5,-7.5; T8 -0.5,-7.5; T9 0.5,-7.5; T10 1.5,-7.5; T11 2.5,-7.5; T12 3.5,-7.5; T13 4.5,-7.5; T14 5.5,-7.5; T15 6.5,-7.5; T16 7.5,-7.5

## Footprint GDH_S-PBGA-N256 (pad centres in mm)
GDH (S-PBGA-N256) PLASTIC BALL GRID ARRAY Source: http://focus.ti.com/lit/ds/symlink/tms320c6720.pdf
smd 0.7 x 0.7: A1 -7.5,7.5; A2 -6.5,7.5; A3 -5.5,7.5; A4 -4.5,7.5; A5 -3.5,7.5; A6 -2.5,7.5; A7 -1.5,7.5; A8 -0.5,7.5; A9 0.5,7.5; A10 1.5,7.5; A11 2.5,7.5; A12 3.5,7.5; A13 4.5,7.5; A14 5.5,7.5; A15 6.5,7.5; A16 7.5,7.5; B1 -7.5,6.5; B2 -6.5,6.5; B3 -5.5,6.5; B4 -4.5,6.5; B5 -3.5,6.5; B6 -2.5,6.5; B7 -1.5,6.5; B8 -0.5,6.5; B9 0.5,6.5; B10 1.5,6.5; B11 2.5,6.5; B12 3.5,6.5; B13 4.5,6.5; B14 5.5,6.5; B15 6.5,6.5; B16 7.5,6.5; C1 -7.5,5.5; C2 -6.5,5.5; C3 -5.5,5.5; C4 -4.5,5.5; C5 -3.5,5.5; C6 -2.5,5.5; C7 -1.5,5.5; C8 -0.5,5.5; C9 0.5,5.5; C10 1.5,5.5; C11 2.5,5.5; C12 3.5,5.5; C13 4.5,5.5; C14 5.5,5.5; C15 6.5,5.5; C16 7.5,5.5; D1 -7.5,4.5; D2 -6.5,4.5; D3 -5.5,4.5; D4 -4.5,4.5; D5 -3.5,4.5; D6 -2.5,4.5; D7 -1.5,4.5; D8 -0.5,4.5; D9 0.5,4.5; D10 1.5,4.5; D11 2.5,4.5; D12 3.5,4.5; D13 4.5,4.5; D14 5.5,4.5; D15 6.5,4.5; D16 7.5,4.5; E1 -7.5,3.5; E2 -6.5,3.5; E3 -5.5,3.5; E4 -4.5,3.5; E5 -3.5,3.5; E6 -2.5,3.5; E7 -1.5,3.5; E8 -0.5,3.5; E9 0.5,3.5; E10 1.5,3.5; E11 2.5,3.5; E12 3.5,3.5; E13 4.5,3.5; E14 5.5,3.5; E15 6.5,3.5; E16 7.5,3.5; F1 -7.5,2.5; F2 -6.5,2.5; F3 -5.5,2.5; F4 -4.5,2.5; F5 -3.5,2.5; F6 -2.5,2.5; F7 -1.5,2.5; F8 -0.5,2.5; F9 0.5,2.5; F10 1.5,2.5; F11 2.5,2.5; F12 3.5,2.5; F13 4.5,2.5; F14 5.5,2.5; F15 6.5,2.5; F16 7.5,2.5; G1 -7.5,1.5; G2 -6.5,1.5; G3 -5.5,1.5; G4 -4.5,1.5; G5 -3.5,1.5; G6 -2.5,1.5; G7 -1.5,1.5; G8 -0.5,1.5; G9 0.5,1.5; G10 1.5,1.5; G11 2.5,1.5; G12 3.5,1.5; G13 4.5,1.5; G14 5.5,1.5; G15 6.5,1.5; G16 7.5,1.5; H1 -7.5,0.5; H2 -6.5,0.5; H3 -5.5,0.5; H4 -4.5,0.5; H5 -3.5,0.5; H6 -2.5,0.5; H7 -1.5,0.5; H8 -0.5,0.5; H9 0.5,0.5; H10 1.5,0.5; H11 2.5,0.5; H12 3.5,0.5; H13 4.5,0.5; H14 5.5,0.5; H15 6.5,0.5; H16 7.5,0.5; J1 -7.5,-0.5; J2 -6.5,-0.5; J3 -5.5,-0.5; J4 -4.5,-0.5; J5 -3.5,-0.5; J6 -2.5,-0.5; J7 -1.5,-0.5; J8 -0.5,-0.5; J9 0.5,-0.5; J10 1.5,-0.5; J11 2.5,-0.5; J12 3.5,-0.5; J13 4.5,-0.5; J14 5.5,-0.5; J15 6.5,-0.5; J16 7.5,-0.5; K1 -7.5,-1.5; K2 -6.5,-1.5; K3 -5.5,-1.5; K4 -4.5,-1.5; K5 -3.5,-1.5; K6 -2.5,-1.5; K7 -1.5,-1.5; K8 -0.5,-1.5; K9 0.5,-1.5; K10 1.5,-1.5; K11 2.5,-1.5; K12 3.5,-1.5; K13 4.5,-1.5; K14 5.5,-1.5; K15 6.5,-1.5; K16 7.5,-1.5; L1 -7.5,-2.5; L2 -6.5,-2.5; L3 -5.5,-2.5; L4 -4.5,-2.5; L5 -3.5,-2.5; L6 -2.5,-2.5; L7 -1.5,-2.5; L8 -0.5,-2.5; L9 0.5,-2.5; L10 1.5,-2.5; L11 2.5,-2.5; L12 3.5,-2.5; L13 4.5,-2.5; L14 5.5,-2.5; L15 6.5,-2.5; L16 7.5,-2.5; M1 -7.5,-3.5; M2 -6.5,-3.5; M3 -5.5,-3.5; M4 -4.5,-3.5; M5 -3.5,-3.5; M6 -2.5,-3.5; M7 -1.5,-3.5; M8 -0.5,-3.5; M9 0.5,-3.5; M10 1.5,-3.5; M11 2.5,-3.5; M12 3.5,-3.5; M13 4.5,-3.5; M14 5.5,-3.5; M15 6.5,-3.5; M16 7.5,-3.5; N1 -7.5,-4.5; N2 -6.5,-4.5; N3 -5.5,-4.5; N4 -4.5,-4.5; N5 -3.5,-4.5; N6 -2.5,-4.5; N7 -1.5,-4.5; N8 -0.5,-4.5; N9 0.5,-4.5; N10 1.5,-4.5; N11 2.5,-4.5; N12 3.5,-4.5; N13 4.5,-4.5; N14 5.5,-4.5; N15 6.5,-4.5; N16 7.5,-4.5; P1 -7.5,-5.5; P2 -6.5,-5.5; P3 -5.5,-5.5; P4 -4.5,-5.5; P5 -3.5,-5.5; P6 -2.5,-5.5; P7 -1.5,-5.5; P8 -0.5,-5.5; P9 0.5,-5.5; P10 1.5,-5.5; P11 2.5,-5.5; P12 3.5,-5.5; P13 4.5,-5.5; P14 5.5,-5.5; P15 6.5,-5.5; P16 7.5,-5.5; R1 -7.5,-6.5; R2 -6.5,-6.5; R3 -5.5,-6.5; R4 -4.5,-6.5; R5 -3.5,-6.5; R6 -2.5,-6.5; R7 -1.5,-6.5; R8 -0.5,-6.5; R9 0.5,-6.5; R10 1.5,-6.5; R11 2.5,-6.5; R12 3.5,-6.5; R13 4.5,-6.5; R14 5.5,-6.5; R15 6.5,-6.5; R16 7.5,-6.5; T1 -7.5,-7.5; T2 -6.5,-7.5; T3 -5.5,-7.5; T4 -4.5,-7.5; T5 -3.5,-7.5; T6 -2.5,-7.5; T7 -1.5,-7.5; T8 -0.5,-7.5; T9 0.5,-7.5; T10 1.5,-7.5; T11 2.5,-7.5; T12 3.5,-7.5; T13 4.5,-7.5; T14 5.5,-7.5; T15 6.5,-7.5; T16 7.5,-7.5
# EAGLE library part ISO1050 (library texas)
ISOLATED CAN TRANSCEIVER Source: http://focus.ti.com/lit/ds/symlink/iso1050.pdf

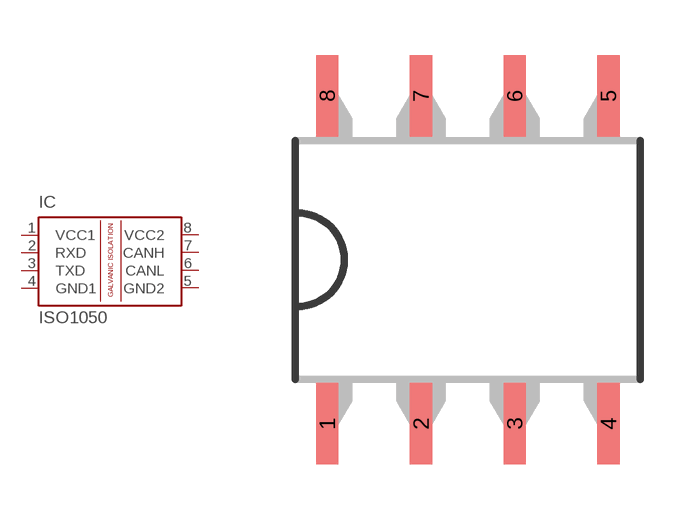
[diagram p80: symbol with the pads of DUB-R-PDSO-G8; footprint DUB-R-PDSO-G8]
Designator prefix IC

## ISO1050DUB (MPN: ISO1050DUBR; OC_FARNELL: 1755712; OC_NEWARK: 14R9899)  [DUB-R-PDSO-G8]
1  VCC1  in
2  RXD  in
3  TXD  in
4  GND1  in
5  GND2  in
6  CANL  in
7  CANH  in
8  VCC2  in

## Footprint DUB-R-PDSO-G8 (pad centres in mm)
DUB (R-PDSO-G8) Source: http://focus.ti.com/lit/ds/symlink/iso1050.pdf
smd 0.6 x 2.2: 1 -3.81,-4.445; 2 -1.27,-4.445; 3 1.27,-4.445; 4 3.81,-4.445; 5 3.81,4.445; 6 1.27,4.445; 7 -1.27,4.445; 8 -3.81,4.445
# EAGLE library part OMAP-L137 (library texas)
OMAP-L137 Low-Power Applications Processor Auto generated by make-symbol-device-package-bsdl.ulp Rev. 29 Source: sprm328.bsm http://focus.ti.com/lit/ds/symlink/omap-l137.pdf

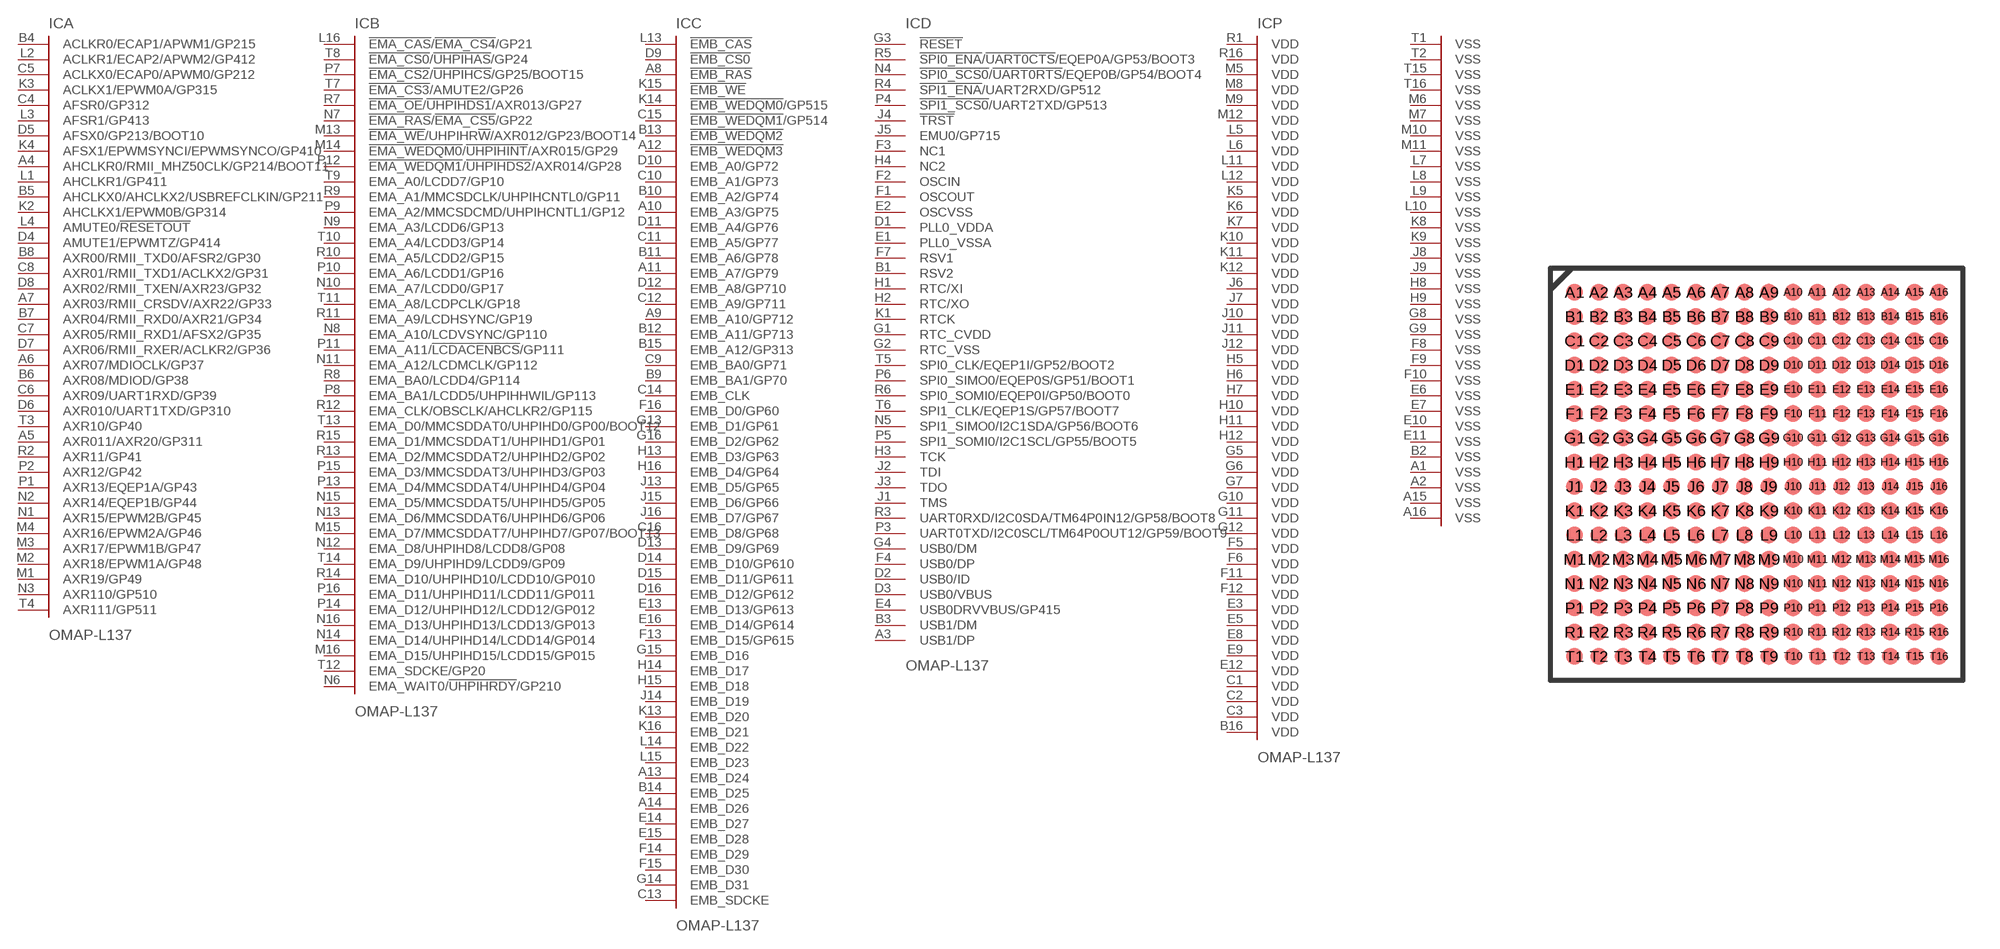
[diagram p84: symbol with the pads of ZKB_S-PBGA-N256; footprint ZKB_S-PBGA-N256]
Designator prefix IC; gates A=OMAP-L137_A B=OMAP-L137_B C=OMAP-L137_C D=OMAP-L137_D P=OMAP-L137_P

## OMAP-L137 (MPN: OMAP-L137 EVAL; OC_FARNELL: 1831923; OC_NEWARK: 78R2891)  [ZKB_S-PBGA-N256]
A1  P:VSS  pwr
A2  P:VSS  pwr
A3  D:USB1/DP  pas
A4  A:AHCLKR0/RMII_MHZ50CLK/GP214/BOOT11
A5  A:AXR011/AXR20/GP311
A6  A:AXR07/MDIOCLK/GP37
A7  A:AXR03/RMII_CRSDV/AXR22/GP33
A8  C:!EMB_RAS
A9  C:EMB_A10/GP712
A10  C:EMB_A3/GP75
A11  C:EMB_A7/GP79
A12  C:!EMB_WEDQM3!
A13  C:EMB_D24
A14  C:EMB_D26
A15  P:VSS  pwr
A16  P:VSS  pwr
B1  D:RSV2  pas
B2  P:VSS  pwr
B3  D:USB1/DM  pas
B4  A:ACLKR0/ECAP1/APWM1/GP215
B5  A:AHCLKX0/AHCLKX2/USBREFCLKIN/GP211
B6  A:AXR08/MDIOD/GP38
B7  A:AXR04/RMII_RXD0/AXR21/GP34
B8  A:AXR00/RMII_TXD0/AFSR2/GP30
B9  C:EMB_BA1/GP70
B10  C:EMB_A2/GP74
B11  C:EMB_A6/GP78
B12  C:EMB_A11/GP713
B13  C:!EMB_WEDQM2!
B14  C:EMB_D25
B15  C:EMB_A12/GP313
B16  P:VDD  pwr
C1  P:VDD  pwr
C2  P:VDD  pwr
C3  P:VDD  pwr
C4  A:AFSR0/GP312
C5  A:ACLKX0/ECAP0/APWM0/GP212
C6  A:AXR09/UART1RXD/GP39
C7  A:AXR05/RMII_RXD1/AFSX2/GP35
C8  A:AXR01/RMII_TXD1/ACLKX2/GP31
C9  C:EMB_BA0/GP71
C10  C:EMB_A1/GP73
C11  C:EMB_A5/GP77
C12  C:EMB_A9/GP711
C13  C:EMB_SDCKE
C14  C:EMB_CLK
C15  C:!EMB_WEDQM1!/GP514
C16  C:EMB_D8/GP68
D1  D:PLL0_VDDA  pwr
D2  D:USB0/ID  pas
D3  D:USB0/VBUS  pas
D4  A:AMUTE1/EPWMTZ/GP414
D5  A:AFSX0/GP213/BOOT10
D6  A:AXR010/UART1TXD/GP310
D7  A:AXR06/RMII_RXER/ACLKR2/GP36
D8  A:AXR02/RMII_TXEN/AXR23/GP32
D9  C:!EMB_CS0
D10  C:EMB_A0/GP72
D11  C:EMB_A4/GP76
D12  C:EMB_A8/GP710
D13  C:EMB_D9/GP69
D14  C:EMB_D10/GP610
D15  C:EMB_D11/GP611
D16  C:EMB_D12/GP612
E1  D:PLL0_VSSA  pwr
E2  D:OSCVSS  pwr
E3  P:VDD  pwr
E4  D:USB0DRVVBUS/GP415
E5  P:VDD  pwr
E6  P:VSS  pwr
E7  P:VSS  pwr
E8  P:VDD  pwr
E9  P:VDD  pwr
E10  P:VSS  pwr
E11  P:VSS  pwr
E12  P:VDD  pwr
E13  C:EMB_D13/GP613
E14  C:EMB_D27
E15  C:EMB_D28
E16  C:EMB_D14/GP614
F1  D:OSCOUT  pas
F2  D:OSCIN  pas
F3  D:NC1  pas
F4  D:USB0/DP  pas
F5  P:VDD  pwr
F6  P:VDD  pwr
F7  D:RSV1  pas
F8  P:VSS  pwr
F9  P:VSS  pwr
F10  P:VSS  pwr
F11  P:VDD  pwr
F12  P:VDD  pwr
F13  C:EMB_D15/GP615
F14  C:EMB_D29
F15  C:EMB_D30
F16  C:EMB_D0/GP60
G1  D:RTC_CVDD  pwr
G2  D:RTC_VSS  pwr
G3  D:!RESET  in
G4  D:USB0/DM  pas
G5  P:VDD  pwr
G6  P:VDD  pwr
G7  P:VDD  pwr
G8  P:VSS  pwr
G9  P:VSS  pwr
G10  P:VDD  pwr
G11  P:VDD  pwr
G12  P:VDD  pwr
G13  C:EMB_D1/GP61
G14  C:EMB_D31
G15  C:EMB_D16
G16  C:EMB_D2/GP62
H1  D:RTC/XI  pas
H2  D:RTC/XO  pas
H3  D:TCK  in
H4  D:NC2  pas
H5  P:VDD  pwr
H6  P:VDD  pwr
H7  P:VDD  pwr
H8  P:VSS  pwr
H9  P:VSS  pwr
H10  P:VDD  pwr
H11  P:VDD  pwr
H12  P:VDD  pwr
H13  C:EMB_D3/GP63
H14  C:EMB_D17
H15  C:EMB_D18
H16  C:EMB_D4/GP64
J1  D:TMS  in
J2  D:TDI  in
J3  D:TDO  out
J4  D:!TRST  in
J5  D:EMU0/GP715
J6  P:VDD  pwr
J7  P:VDD  pwr
J8  P:VSS  pwr
J9  P:VSS  pwr
J10  P:VDD  pwr
J11  P:VDD  pwr
J12  P:VDD  pwr
J13  C:EMB_D5/GP65
J14  C:EMB_D19
J15  C:EMB_D6/GP66
J16  C:EMB_D7/GP67
K1  D:RTCK  pas
K2  A:AHCLKX1/EPWM0B/GP314
K3  A:ACLKX1/EPWM0A/GP315
K4  A:AFSX1/EPWMSYNCI/EPWMSYNCO/GP410
K5  P:VDD  pwr
K6  P:VDD  pwr
K7  P:VDD  pwr
K8  P:VSS  pwr
K9  P:VSS  pwr
K10  P:VDD  pwr
K11  P:VDD  pwr
K12  P:VDD  pwr
K13  C:EMB_D20
K14  C:!EMB_WEDQM0!/GP515
K15  C:!EMB_WE
K16  C:EMB_D21
L1  A:AHCLKR1/GP411
L2  A:ACLKR1/ECAP2/APWM2/GP412
L3  A:AFSR1/GP413
L4  A:AMUTE0/!RESETOUT
L5  P:VDD  pwr
L6  P:VDD  pwr
L7  P:VSS  pwr
L8  P:VSS  pwr
L9  P:VSS  pwr
L10  P:VSS  pwr
L11  P:VDD  pwr
L12  P:VDD  pwr
L13  C:!EMB_CAS
L14  C:EMB_D22
L15  C:EMB_D23
L16  B:!EMA_CAS!/!EMA_CS4!/GP21
M1  A:AXR19/GP49
M2  A:AXR18/EPWM1A/GP48
M3  A:AXR17/EPWM1B/GP47
M4  A:AXR16/EPWM2A/GP46
M5  P:VDD  pwr
M6  P:VSS  pwr
M7  P:VSS  pwr
M8  P:VDD  pwr
M9  P:VDD  pwr
M10  P:VSS  pwr
M11  P:VSS  pwr
M12  P:VDD  pwr
M13  B:!EMA_WE!/UHPIHR!W!/AXR012/GP23/BOOT14
M14  B:!EMA_WEDQM0!/!UHPIHINT!/AXR015/GP29
M15  B:EMA_D7/MMCSDDAT7/UHPIHD7/GP07/BOOT13
M16  B:EMA_D15/UHPIHD15/LCDD15/GP015
N1  A:AXR15/EPWM2B/GP45
N2  A:AXR14/EQEP1B/GP44
N3  A:AXR110/GP510
N4  D:!SPI0_SCS0!/!UART0RTS!/EQEP0B/GP54/BOOT4
N5  D:SPI1_SIMO0/I2C1SDA/GP56/BOOT6
N6  B:EMA_WAIT0/!UHPIHRDY!/GP210
N7  B:!EMA_RAS!/!EMA_CS5!/GP22
N8  B:EMA_A10/LCDVSYNC/GP110
N9  B:EMA_A3/LCDD6/GP13
N10  B:EMA_A7/LCDD0/GP17
N11  B:EMA_A12/LCDMCLK/GP112
N12  B:EMA_D8/UHPIHD8/LCDD8/GP08
N13  B:EMA_D6/MMCSDDAT6/UHPIHD6/GP06
N14  B:EMA_D14/UHPIHD14/LCDD14/GP014
N15  B:EMA_D5/MMCSDDAT5/UHPIHD5/GP05
N16  B:EMA_D13/UHPIHD13/LCDD13/GP013
P1  A:AXR13/EQEP1A/GP43
P2  A:AXR12/GP42
P3  D:UART0TXD/I2C0SCL/TM64P0OUT12/GP59/BOOT9
P4  D:!SPI1_SCS0!/UART2TXD/GP513
P5  D:SPI1_SOMI0/I2C1SCL/GP55/BOOT5
P6  D:SPI0_SIMO0/EQEP0S/GP51/BOOT1
P7  B:!EMA_CS2!/!UHPIHCS!/GP25/BOOT15
P8  B:EMA_BA1/LCDD5/UHPIHHWIL/GP113
P9  B:EMA_A2/MMCSDCMD/UHPIHCNTL1/GP12
P10  B:EMA_A6/LCDD1/GP16
P11  B:EMA_A11/!LCDACENBCS!/GP111
P12  B:!EMA_WEDQM1!/!UHPIHDS2!/AXR014/GP28
P13  B:EMA_D4/MMCSDDAT4/UHPIHD4/GP04
P14  B:EMA_D12/UHPIHD12/LCDD12/GP012
P15  B:EMA_D3/MMCSDDAT3/UHPIHD3/GP03
P16  B:EMA_D11/UHPIHD11/LCDD11/GP011
R1  P:VDD  pwr
R2  A:AXR11/GP41
R3  D:UART0RXD/I2C0SDA/TM64P0IN12/GP58/BOOT8
R4  D:!SPI1_ENA!/UART2RXD/GP512
R5  D:!SPI0_ENA!/!UART0CTS!/EQEP0A/GP53/BOOT3
R6  D:SPI0_SOMI0/EQEP0I/GP50/BOOT0
R7  B:!EMA_OE!/!UHPIHDS1!/AXR013/GP27
R8  B:EMA_BA0/LCDD4/GP114
R9  B:EMA_A1/MMCSDCLK/UHPIHCNTL0/GP11
R10  B:EMA_A5/LCDD2/GP15
R11  B:EMA_A9/LCDHSYNC/GP19
R12  B:EMA_CLK/OBSCLK/AHCLKR2/GP115
R13  B:EMA_D2/MMCSDDAT2/UHPIHD2/GP02
R14  B:EMA_D10/UHPIHD10/LCDD10/GP010
R15  B:EMA_D1/MMCSDDAT1/UHPIHD1/GP01
R16  P:VDD  pwr
T1  P:VSS  pwr
T2  P:VSS  pwr
T3  A:AXR10/GP40
T4  A:AXR111/GP511
T5  D:SPI0_CLK/EQEP1I/GP52/BOOT2
T6  D:SPI1_CLK/EQEP1S/GP57/BOOT7
T7  B:!EMA_CS3!/AMUTE2/GP26
T8  B:!EMA_CS0!/!UHPIHAS!/GP24
T9  B:EMA_A0/LCDD7/GP10
T10  B:EMA_A4/LCDD3/GP14
T11  B:EMA_A8/LCDPCLK/GP18
T12  B:EMA_SDCKE/GP20
T13  B:EMA_D0/MMCSDDAT0/UHPIHD0/GP00/BOOT12
T14  B:EMA_D9/UHPIHD9/LCDD9/GP09
T15  P:VSS  pwr
T16  P:VSS  pwr

## Footprint ZKB_S-PBGA-N256 (pad centres in mm)
sprm328 edit this description Auto generated by make-symbol-device-package-bsdl.ulp Rev. 29 Source: sprm328.bsm
smd 0.7 x 0.7: A1 -7.5,7.5; A2 -6.5,7.5; A3 -5.5,7.5; A4 -4.5,7.5; A5 -3.5,7.5; A6 -2.5,7.5; A7 -1.5,7.5; A8 -0.5,7.5; A9 0.5,7.5; A10 1.5,7.5; A11 2.5,7.5; A12 3.5,7.5; A13 4.5,7.5; A14 5.5,7.5; A15 6.5,7.5; A16 7.5,7.5; B1 -7.5,6.5; B2 -6.5,6.5; B3 -5.5,6.5; B4 -4.5,6.5; B5 -3.5,6.5; B6 -2.5,6.5; B7 -1.5,6.5; B8 -0.5,6.5; B9 0.5,6.5; B10 1.5,6.5; B11 2.5,6.5; B12 3.5,6.5; B13 4.5,6.5; B14 5.5,6.5; B15 6.5,6.5; B16 7.5,6.5; C1 -7.5,5.5; C2 -6.5,5.5; C3 -5.5,5.5; C4 -4.5,5.5; C5 -3.5,5.5; C6 -2.5,5.5; C7 -1.5,5.5; C8 -0.5,5.5; C9 0.5,5.5; C10 1.5,5.5; C11 2.5,5.5; C12 3.5,5.5; C13 4.5,5.5; C14 5.5,5.5; C15 6.5,5.5; C16 7.5,5.5; D1 -7.5,4.5; D2 -6.5,4.5; D3 -5.5,4.5; D4 -4.5,4.5; D5 -3.5,4.5; D6 -2.5,4.5; D7 -1.5,4.5; D8 -0.5,4.5; D9 0.5,4.5; D10 1.5,4.5; D11 2.5,4.5; D12 3.5,4.5; D13 4.5,4.5; D14 5.5,4.5; D15 6.5,4.5; D16 7.5,4.5; E1 -7.5,3.5; E2 -6.5,3.5; E3 -5.5,3.5; E4 -4.5,3.5; E5 -3.5,3.5; E6 -2.5,3.5; E7 -1.5,3.5; E8 -0.5,3.5; E9 0.5,3.5; E10 1.5,3.5; E11 2.5,3.5; E12 3.5,3.5; E13 4.5,3.5; E14 5.5,3.5; E15 6.5,3.5; E16 7.5,3.5; F1 -7.5,2.5; F2 -6.5,2.5; F3 -5.5,2.5; F4 -4.5,2.5; F5 -3.5,2.5; F6 -2.5,2.5; F7 -1.5,2.5; F8 -0.5,2.5; F9 0.5,2.5; F10 1.5,2.5; F11 2.5,2.5; F12 3.5,2.5; F13 4.5,2.5; F14 5.5,2.5; F15 6.5,2.5; F16 7.5,2.5; G1 -7.5,1.5; G2 -6.5,1.5; G3 -5.5,1.5; G4 -4.5,1.5; G5 -3.5,1.5; G6 -2.5,1.5; G7 -1.5,1.5; G8 -0.5,1.5; G9 0.5,1.5; G10 1.5,1.5; G11 2.5,1.5; G12 3.5,1.5; G13 4.5,1.5; G14 5.5,1.5; G15 6.5,1.5; G16 7.5,1.5; H1 -7.5,0.5; H2 -6.5,0.5; H3 -5.5,0.5; H4 -4.5,0.5; H5 -3.5,0.5; H6 -2.5,0.5; H7 -1.5,0.5; H8 -0.5,0.5; H9 0.5,0.5; H10 1.5,0.5; H11 2.5,0.5; H12 3.5,0.5; H13 4.5,0.5; H14 5.5,0.5; H15 6.5,0.5; H16 7.5,0.5; J1 -7.5,-0.5; J2 -6.5,-0.5; J3 -5.5,-0.5; J4 -4.5,-0.5; J5 -3.5,-0.5; J6 -2.5,-0.5; J7 -1.5,-0.5; J8 -0.5,-0.5; J9 0.5,-0.5; J10 1.5,-0.5; J11 2.5,-0.5; J12 3.5,-0.5; J13 4.5,-0.5; J14 5.5,-0.5; J15 6.5,-0.5; J16 7.5,-0.5; K1 -7.5,-1.5; K2 -6.5,-1.5; K3 -5.5,-1.5; K4 -4.5,-1.5; K5 -3.5,-1.5; K6 -2.5,-1.5; K7 -1.5,-1.5; K8 -0.5,-1.5; K9 0.5,-1.5; K10 1.5,-1.5; K11 2.5,-1.5; K12 3.5,-1.5; K13 4.5,-1.5; K14 5.5,-1.5; K15 6.5,-1.5; K16 7.5,-1.5; L1 -7.5,-2.5; L2 -6.5,-2.5; L3 -5.5,-2.5; L4 -4.5,-2.5; L5 -3.5,-2.5; L6 -2.5,-2.5; L7 -1.5,-2.5; L8 -0.5,-2.5; L9 0.5,-2.5; L10 1.5,-2.5; L11 2.5,-2.5; L12 3.5,-2.5; L13 4.5,-2.5; L14 5.5,-2.5; L15 6.5,-2.5; L16 7.5,-2.5; M1 -7.5,-3.5; M2 -6.5,-3.5; M3 -5.5,-3.5; M4 -4.5,-3.5; M5 -3.5,-3.5; M6 -2.5,-3.5; M7 -1.5,-3.5; M8 -0.5,-3.5; M9 0.5,-3.5; M10 1.5,-3.5; M11 2.5,-3.5; M12 3.5,-3.5; M13 4.5,-3.5; M14 5.5,-3.5; M15 6.5,-3.5; M16 7.5,-3.5; N1 -7.5,-4.5; N2 -6.5,-4.5; N3 -5.5,-4.5; N4 -4.5,-4.5; N5 -3.5,-4.5; N6 -2.5,-4.5; N7 -1.5,-4.5; N8 -0.5,-4.5; N9 0.5,-4.5; N10 1.5,-4.5; N11 2.5,-4.5; N12 3.5,-4.5; N13 4.5,-4.5; N14 5.5,-4.5; N15 6.5,-4.5; N16 7.5,-4.5; P1 -7.5,-5.5; P2 -6.5,-5.5; P3 -5.5,-5.5; P4 -4.5,-5.5; P5 -3.5,-5.5; P6 -2.5,-5.5; P7 -1.5,-5.5; P8 -0.5,-5.5; P9 0.5,-5.5; P10 1.5,-5.5; P11 2.5,-5.5; P12 3.5,-5.5; P13 4.5,-5.5; P14 5.5,-5.5; P15 6.5,-5.5; P16 7.5,-5.5; R1 -7.5,-6.5; R2 -6.5,-6.5; R3 -5.5,-6.5; R4 -4.5,-6.5; R5 -3.5,-6.5; R6 -2.5,-6.5; R7 -1.5,-6.5; R8 -0.5,-6.5; R9 0.5,-6.5; R10 1.5,-6.5; R11 2.5,-6.5; R12 3.5,-6.5; R13 4.5,-6.5; R14 5.5,-6.5; R15 6.5,-6.5; R16 7.5,-6.5; T1 -7.5,-7.5; T2 -6.5,-7.5; T3 -5.5,-7.5; T4 -4.5,-7.5; T5 -3.5,-7.5; T6 -2.5,-7.5; T7 -1.5,-7.5; T8 -0.5,-7.5; T9 0.5,-7.5; T10 1.5,-7.5; T11 2.5,-7.5; T12 3.5,-7.5; T13 4.5,-7.5; T14 5.5,-7.5; T15 6.5,-7.5; T16 7.5,-7.5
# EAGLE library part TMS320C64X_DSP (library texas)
TMS320C64x+ digital signal processor Auto generated by make-symbol-device-package-bsdl.ulp Rev. 29 Source: http://focus-webapps.ti.com .. sprm148b.bsd Connect-List generated from TMS320C64X_DSP.DEV Variant '' with connect-device-split-symbol-03.ulp

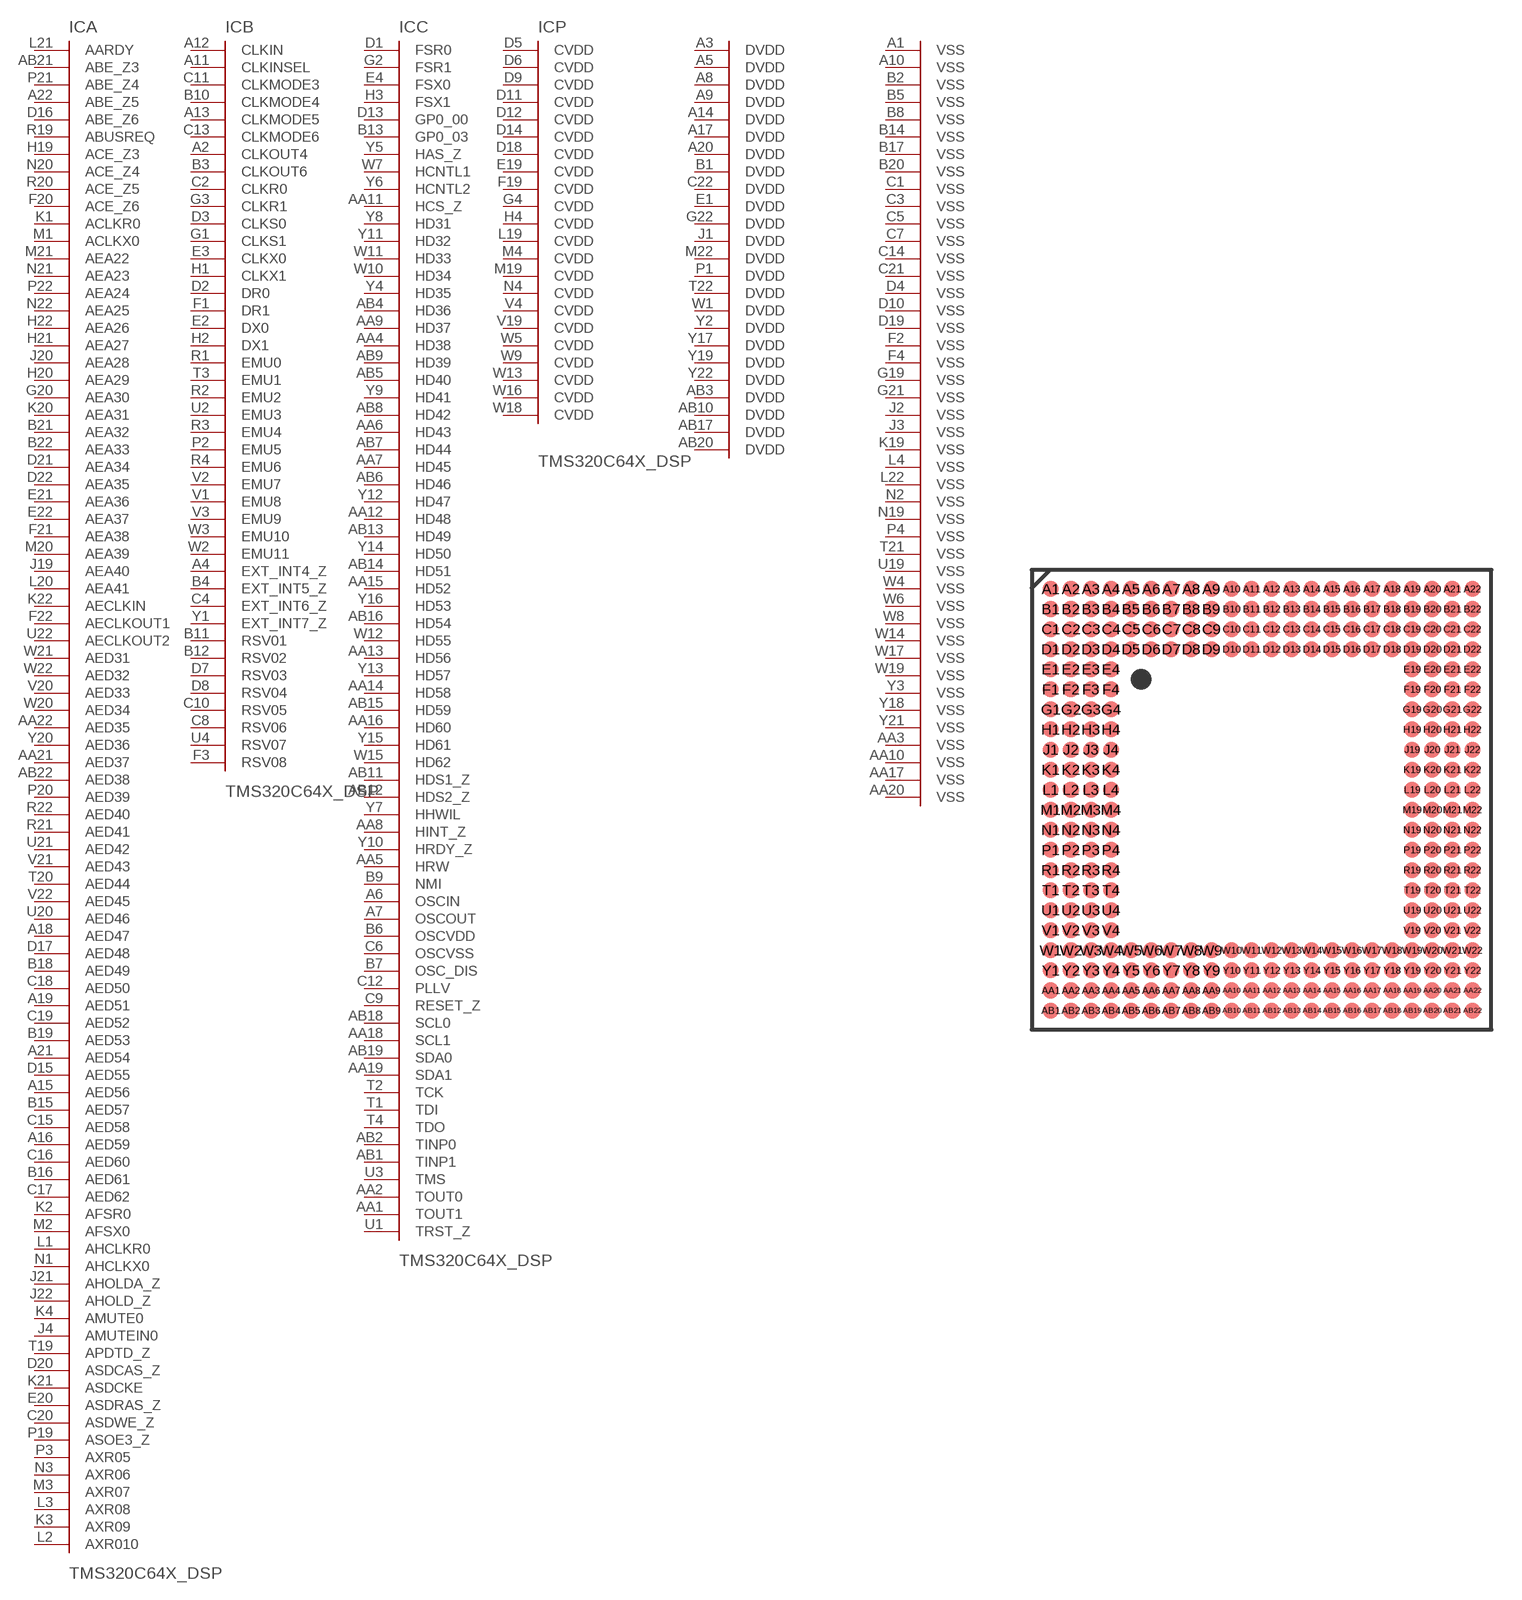
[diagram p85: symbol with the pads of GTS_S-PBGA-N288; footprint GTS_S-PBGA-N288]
Designator prefix IC; gates A=TMS320C64X_DSP-A B=TMS320C64X_DSP-B C=TMS320C64X_DSP-C P=TMS320C64X_DSP-P

## TMS320C64X_DSP (OC_FARNELL: 1610186; OC_NEWARK: unknown)  [GTS_S-PBGA-N288]
A1  P:VSS  pas
A2  B:CLKOUT4
A3  P:DVDD  pas
A4  B:EXT_INT4_Z
A5  P:DVDD  pas
A6  C:OSCIN  pas
A7  C:OSCOUT  pas
A8  P:DVDD  pas
A9  P:DVDD  pas
A10  P:VSS  pas
A11  B:CLKINSEL  in
A12  B:CLKIN  in
A13  B:CLKMODE5  in
A14  P:DVDD  pas
A15  A:AED56
A16  A:AED59
A17  P:DVDD  pas
A18  A:AED47
A19  A:AED51
A20  P:DVDD  pas
A21  A:AED54
A22  A:ABE_Z5  out
AA1  C:TOUT1
AA2  C:TOUT0
AA3  P:VSS  pas
AA4  C:HD38
AA5  C:HRW  in
AA6  C:HD43
AA7  C:HD45
AA8  C:HINT_Z
AA9  C:HD37
AA10  P:VSS  pas
AA11  C:HCS_Z  in
AA12  C:HD48
AA13  C:HD56
AA14  C:HD58
AA15  C:HD52
AA16  C:HD60
AA17  P:VSS  pas
AA18  C:SCL1
AA19  C:SDA1
AA20  P:VSS  pas
AA21  A:AED37
AA22  A:AED35
AB1  C:TINP1  in
AB2  C:TINP0  in
AB3  P:DVDD  pas
AB4  C:HD36
AB5  C:HD40
AB6  C:HD46
AB7  C:HD44
AB8  C:HD42
AB9  C:HD39
AB10  P:DVDD  pas
AB11  C:HDS1_Z  in
AB12  C:HDS2_Z  in
AB13  C:HD49
AB14  C:HD51
AB15  C:HD59
AB16  C:HD54
AB17  P:DVDD  pas
AB18  C:SCL0
AB19  C:SDA0
AB20  P:DVDD  pas
AB21  A:ABE_Z3  out
AB22  A:AED38
B1  P:DVDD  pas
B2  P:VSS  pas
B3  B:CLKOUT6
B4  B:EXT_INT5_Z
B5  P:VSS  pas
B6  C:OSCVDD  pas
B7  C:OSC_DIS  in
B8  P:VSS  pas
B9  C:NMI  in
B10  B:CLKMODE4  in
B11  B:RSV01  pas
B12  B:RSV02  pas
B13  C:GP0_03
B14  P:VSS  pas
B15  A:AED57
B16  A:AED61
B17  P:VSS  pas
B18  A:AED49
B19  A:AED53
B20  P:VSS  pas
B21  A:AEA32
B22  A:AEA33
C1  P:VSS  pas
C2  B:CLKR0
C3  P:VSS  pas
C4  B:EXT_INT6_Z
C5  P:VSS  pas
C6  C:OSCVSS  pas
C7  P:VSS  pas
C8  B:RSV06  in
C9  C:RESET_Z  in
C10  B:RSV05  out
C11  B:CLKMODE3  in
C12  C:PLLV  pas
C13  B:CLKMODE6  in
C14  P:VSS  pas
C15  A:AED58
C16  A:AED60
C17  A:AED62
C18  A:AED50
C19  A:AED52
C20  A:ASDWE_Z  out
C21  P:VSS  pas
C22  P:DVDD  pas
D1  C:FSR0
D2  B:DR0  in
D3  B:CLKS0  in
D4  P:VSS  pas
D5  P:CVDD  pas
D6  P:CVDD  pas
D7  B:RSV03  pas
D8  B:RSV04  pas
D9  P:CVDD  pas
D10  P:VSS  pas
D11  P:CVDD  pas
D12  P:CVDD  pas
D13  C:GP0_00
D14  P:CVDD  pas
D15  A:AED55
D16  A:ABE_Z6  out
D17  A:AED48
D18  P:CVDD  pas
D19  P:VSS  pas
D20  A:ASDCAS_Z  out
D21  A:AEA34
D22  A:AEA35
E1  P:DVDD  pas
E2  B:DX0
E3  B:CLKX0
E4  C:FSX0
E19  P:CVDD  pas
E20  A:ASDRAS_Z  out
E21  A:AEA36
E22  A:AEA37
F1  B:DR1  in
F2  P:VSS  pas
F3  B:RSV08  pas
F4  P:VSS  pas
F19  P:CVDD  pas
F20  A:ACE_Z6  out
F21  A:AEA38
F22  A:AECLKOUT1  out
G1  B:CLKS1  in
G2  C:FSR1
G3  B:CLKR1
G4  P:CVDD  pas
G19  P:VSS  pas
G20  A:AEA30
G21  P:VSS  pas
G22  P:DVDD  pas
H1  B:CLKX1
H2  B:DX1  out
H3  C:FSX1
H4  P:CVDD  pas
H19  A:ACE_Z3  out
H20  A:AEA29
H21  A:AEA27
H22  A:AEA26
J1  P:DVDD  pas
J2  P:VSS  pas
J3  P:VSS  pas
J4  A:AMUTEIN0  in
J19  A:AEA40
J20  A:AEA28
J21  A:AHOLDA_Z  out
J22  A:AHOLD_Z  in
K1  A:ACLKR0
K2  A:AFSR0
K3  A:AXR09
K4  A:AMUTE0
K19  P:VSS  pas
K20  A:AEA31
K21  A:ASDCKE  out
K22  A:AECLKIN  in
L1  A:AHCLKR0
L2  A:AXR010
L3  A:AXR08
L4  P:VSS  pas
L19  P:CVDD  pas
L20  A:AEA41
L21  A:AARDY  in
L22  P:VSS  pas
M1  A:ACLKX0
M2  A:AFSX0
M3  A:AXR07
M4  P:CVDD  pas
M19  P:CVDD  pas
M20  A:AEA39
M21  A:AEA22
M22  P:DVDD  pas
N1  A:AHCLKX0
N2  P:VSS  pas
N3  A:AXR06
N4  P:CVDD  pas
N19  P:VSS  pas
N20  A:ACE_Z4  out
N21  A:AEA23
N22  A:AEA25
P1  P:DVDD  pas
P2  B:EMU5
P3  A:AXR05
P4  P:VSS  pas
P19  A:ASOE3_Z  out
P20  A:AED39
P21  A:ABE_Z4  out
P22  A:AEA24
R1  B:EMU0
R2  B:EMU2
R3  B:EMU4
R4  B:EMU6
R19  A:ABUSREQ  out
R20  A:ACE_Z5  out
R21  A:AED41
R22  A:AED40
T1  C:TDI  in
T2  C:TCK  in
T3  B:EMU1  in
T4  C:TDO  out
T19  A:APDTD_Z  out
T20  A:AED44
T21  P:VSS  pas
T22  P:DVDD  pas
U1  C:TRST_Z  in
U2  B:EMU3
U3  C:TMS  in
U4  B:RSV07  pas
U19  P:VSS  pas
U20  A:AED46
U21  A:AED42
U22  A:AECLKOUT2  out
V1  B:EMU8
V2  B:EMU7
V3  B:EMU9
V4  P:CVDD  pas
V19  P:CVDD  pas
V20  A:AED33
V21  A:AED43
V22  A:AED45
W1  P:DVDD  pas
W2  B:EMU11
W3  B:EMU10
W4  P:VSS  pas
W5  P:CVDD  pas
W6  P:VSS  pas
W7  C:HCNTL1  in
W8  P:VSS  pas
W9  P:CVDD  pas
W10  C:HD34
W11  C:HD33
W12  C:HD55
W13  P:CVDD  pas
W14  P:VSS  pas
W15  C:HD62
W16  P:CVDD  pas
W17  P:VSS  pas
W18  P:CVDD  pas
W19  P:VSS  pas
W20  A:AED34
W21  A:AED31
W22  A:AED32
Y1  B:EXT_INT7_Z
Y2  P:DVDD  pas
Y3  P:VSS  pas
Y4  C:HD35
Y5  C:HAS_Z  in
Y6  C:HCNTL2  in
Y7  C:HHWIL  in
Y8  C:HD31
Y9  C:HD41
Y10  C:HRDY_Z
Y11  C:HD32
Y12  C:HD47
Y13  C:HD57
Y14  C:HD50
Y15  C:HD61
Y16  C:HD53
Y17  P:DVDD  pas
Y18  P:VSS  pas
Y19  P:DVDD  pas
Y20  A:AED36
Y21  P:VSS  pas
Y22  P:DVDD  pas

## Footprint GTS_S-PBGA-N288 (pad centres in mm)
Flip Chip BGA Package GTS (S-PBGA-N288) Auto generated by make-symbol-device-package-bsdl.ulp Rev. 29 Source: sprm148b.bsd http://focus.ti.com/lit/ug/spru811a/spru811a.pdf
smd 0.8 x 0.8: A1 -10.5,10.5; A2 -9.5,10.5; A3 -8.5,10.5; A4 -7.5,10.5; A5 -6.5,10.5; A6 -5.5,10.5; A7 -4.5,10.5; A8 -3.5,10.5; A9 -2.5,10.5; A10 -1.5,10.5; A11 -0.5,10.5; A12 0.5,10.5; A13 1.5,10.5; A14 2.5,10.5; A15 3.5,10.5; A16 4.5,10.5; A17 5.5,10.5; A18 6.5,10.5; A19 7.5,10.5; A20 8.5,10.5; A21 9.5,10.5; A22 10.5,10.5; AA1 -10.5,-9.5; AA2 -9.5,-9.5; AA3 -8.5,-9.5; AA4 -7.5,-9.5; AA5 -6.5,-9.5; AA6 -5.5,-9.5; AA7 -4.5,-9.5; AA8 -3.5,-9.5; AA9 -2.5,-9.5; AA10 -1.5,-9.5; AA11 -0.5,-9.5; AA12 0.5,-9.5; AA13 1.5,-9.5; AA14 2.5,-9.5; AA15 3.5,-9.5; AA16 4.5,-9.5; AA17 5.5,-9.5; AA18 6.5,-9.5; AA19 7.5,-9.5; AA20 8.5,-9.5; AA21 9.5,-9.5; AA22 10.5,-9.5; AB1 -10.5,-10.5; AB2 -9.5,-10.5; AB3 -8.5,-10.5; AB4 -7.5,-10.5; AB5 -6.5,-10.5; AB6 -5.5,-10.5; AB7 -4.5,-10.5; AB8 -3.5,-10.5; AB9 -2.5,-10.5; AB10 -1.5,-10.5; AB11 -0.5,-10.5; AB12 0.5,-10.5; AB13 1.5,-10.5; AB14 2.5,-10.5; AB15 3.5,-10.5; AB16 4.5,-10.5; AB17 5.5,-10.5; AB18 6.5,-10.5; AB19 7.5,-10.5; AB20 8.5,-10.5; AB21 9.5,-10.5; AB22 10.5,-10.5; B1 -10.5,9.5; B2 -9.5,9.5; B3 -8.5,9.5; B4 -7.5,9.5; B5 -6.5,9.5; B6 -5.5,9.5; B7 -4.5,9.5; B8 -3.5,9.5; B9 -2.5,9.5; B10 -1.5,9.5; B11 -0.5,9.5; B12 0.5,9.5; B13 1.5,9.5; B14 2.5,9.5; B15 3.5,9.5; B16 4.5,9.5; B17 5.5,9.5; B18 6.5,9.5; B19 7.5,9.5; B20 8.5,9.5; B21 9.5,9.5; B22 10.5,9.5; C1 -10.5,8.5; C2 -9.5,8.5; C3 -8.5,8.5; C4 -7.5,8.5; C5 -6.5,8.5; C6 -5.5,8.5; C7 -4.5,8.5; C8 -3.5,8.5; C9 -2.5,8.5; C10 -1.5,8.5; C11 -0.5,8.5; C12 0.5,8.5; C13 1.5,8.5; C14 2.5,8.5; C15 3.5,8.5; C16 4.5,8.5; C17 5.5,8.5; C18 6.5,8.5; C19 7.5,8.5; C20 8.5,8.5; C21 9.5,8.5; C22 10.5,8.5; D1 -10.5,7.5; D2 -9.5,7.5; D3 -8.5,7.5; D4 -7.5,7.5; D5 -6.5,7.5; D6 -5.5,7.5; D7 -4.5,7.5; D8 -3.5,7.5; D9 -2.5,7.5; D10 -1.5,7.5; D11 -0.5,7.5; D12 0.5,7.5; D13 1.5,7.5; D14 2.5,7.5; D15 3.5,7.5; D16 4.5,7.5; D17 5.5,7.5; D18 6.5,7.5; D19 7.5,7.5; D20 8.5,7.5; D21 9.5,7.5; D22 10.5,7.5; E1 -10.5,6.5; E2 -9.5,6.5; E3 -8.5,6.5; E4 -7.5,6.5; E19 7.5,6.5; E20 8.5,6.5; E21 9.5,6.5; E22 10.5,6.5; F1 -10.5,5.5; F2 -9.5,5.5; F3 -8.5,5.5; F4 -7.5,5.5; F19 7.5,5.5; F20 8.5,5.5; F21 9.5,5.5; F22 10.5,5.5; G1 -10.5,4.5; G2 -9.5,4.5; G3 -8.5,4.5; G4 -7.5,4.5; G19 7.5,4.5; G20 8.5,4.5; G21 9.5,4.5; G22 10.5,4.5; H1 -10.5,3.5; H2 -9.5,3.5; H3 -8.5,3.5; H4 -7.5,3.5; H19 7.5,3.5; H20 8.5,3.5; H21 9.5,3.5; H22 10.5,3.5; J1 -10.5,2.5; J2 -9.5,2.5; J3 -8.5,2.5; J4 -7.5,2.5; J19 7.5,2.5; J20 8.5,2.5; J21 9.5,2.5; J22 10.5,2.5; K1 -10.5,1.5; K2 -9.5,1.5; K3 -8.5,1.5; K4 -7.5,1.5; K19 7.5,1.5; K20 8.5,1.5; K21 9.5,1.5; K22 10.5,1.5; L1 -10.5,0.5; L2 -9.5,0.5; L3 -8.5,0.5; L4 -7.5,0.5; L19 7.5,0.5; L20 8.5,0.5; L21 9.5,0.5; L22 10.5,0.5; M1 -10.5,-0.5; M2 -9.5,-0.5; M3 -8.5,-0.5; M4 -7.5,-0.5; M19 7.5,-0.5; M20 8.5,-0.5; M21 9.5,-0.5; M22 10.5,-0.5; N1 -10.5,-1.5; N2 -9.5,-1.5; N3 -8.5,-1.5; N4 -7.5,-1.5; N19 7.5,-1.5; N20 8.5,-1.5; N21 9.5,-1.5; N22 10.5,-1.5; P1 -10.5,-2.5; P2 -9.5,-2.5; P3 -8.5,-2.5; P4 -7.5,-2.5; P19 7.5,-2.5; P20 8.5,-2.5; P21 9.5,-2.5; P22 10.5,-2.5; R1 -10.5,-3.5; R2 -9.5,-3.5; R3 -8.5,-3.5; R4 -7.5,-3.5; R19 7.5,-3.5; R20 8.5,-3.5; R21 9.5,-3.5; R22 10.5,-3.5; T1 -10.5,-4.5; T2 -9.5,-4.5; T3 -8.5,-4.5; T4 -7.5,-4.5; T19 7.5,-4.5; T20 8.5,-4.5; T21 9.5,-4.5; T22 10.5,-4.5; U1 -10.5,-5.5; U2 -9.5,-5.5; U3 -8.5,-5.5; U4 -7.5,-5.5; U19 7.5,-5.5; U20 8.5,-5.5; U21 9.5,-5.5; U22 10.5,-5.5; V1 -10.5,-6.5; V2 -9.5,-6.5; V3 -8.5,-6.5; V4 -7.5,-6.5; V19 7.5,-6.5; V20 8.5,-6.5; V21 9.5,-6.5; V22 10.5,-6.5; W1 -10.5,-7.5; W2 -9.5,-7.5; W3 -8.5,-7.5; W4 -7.5,-7.5; W5 -6.5,-7.5; W6 -5.5,-7.5; W7 -4.5,-7.5; W8 -3.5,-7.5; W9 -2.5,-7.5; W10 -1.5,-7.5; W11 -0.5,-7.5; W12 0.5,-7.5; W13 1.5,-7.5; W14 2.5,-7.5; W15 3.5,-7.5; W16 4.5,-7.5; W17 5.5,-7.5; W18 6.5,-7.5; W19 7.5,-7.5; W20 8.5,-7.5; W21 9.5,-7.5; W22 10.5,-7.5; Y1 -10.5,-8.5; Y2 -9.5,-8.5; Y3 -8.5,-8.5; Y4 -7.5,-8.5; Y5 -6.5,-8.5; Y6 -5.5,-8.5; Y7 -4.5,-8.5; Y8 -3.5,-8.5; Y9 -2.5,-8.5; Y10 -1.5,-8.5; Y11 -0.5,-8.5; Y12 0.5,-8.5; Y13 1.5,-8.5; Y14 2.5,-8.5; Y15 3.5,-8.5; Y16 4.5,-8.5; Y17 5.5,-8.5; Y18 6.5,-8.5; Y19 7.5,-8.5; Y20 8.5,-8.5; Y21 9.5,-8.5; Y22 10.5,-8.5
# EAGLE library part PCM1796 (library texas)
24-BIT, 192-kHz SAMPLING, ADVANCED SEGMENT, AUDIO STEREO DIGITAL-TO-ANALOG CONVERTER Source: http://focus.ti.com/lit/ds/symlink/pcm1796.pdf

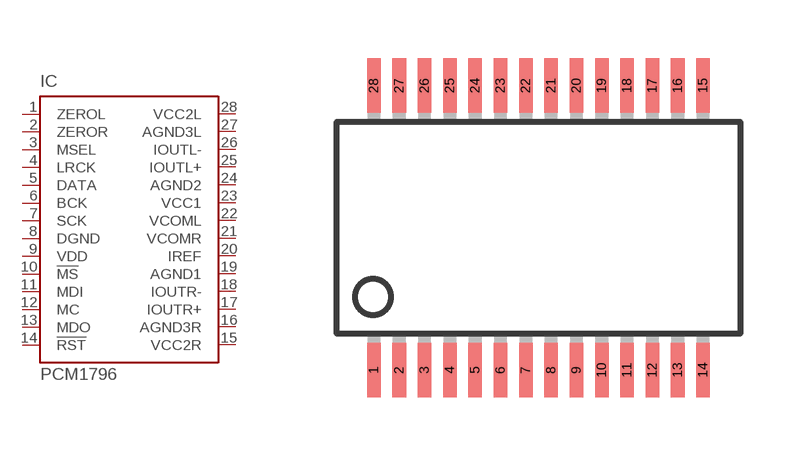
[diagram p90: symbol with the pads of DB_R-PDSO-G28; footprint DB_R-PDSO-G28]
Designator prefix IC

## PCM1796 (MF: TEXAS INSTRUMENT CONNECTORS; MPN: PCM1796DB; OC_FARNELL: unknown; OC_NEWARK: 90H2298)  [DB_R-PDSO-G28]
1  ZEROL
2  ZEROR
3  MSEL  in
4  LRCK  in
5  DATA  in
6  BCK  in
7  SCK  in
8  DGND  in
9  VDD  in
10  !MS
11  MDI  in
12  MC  in
13  MDO
14  !RST  in
15  VCC2R  in
16  AGND3R  in
17  IOUTR+  out
18  IOUTR-  out
19  AGND1  in
20  IREF  out
21  VCOMR  in
22  VCOML  in
23  VCC1  in
24  AGND2  in
25  IOUTL+  out
26  IOUTL-  out
27  AGND3L  in
28  VCC2L  in

## Footprint DB_R-PDSO-G28 (pad centres in mm)
DB (R-PDSO-G28) Source: http://focus.ti.com/lit/ds/symlink/ads1210.pdf
smd 0.348 x 1.397: 1 -4.225,-3.656; 2 -3.575,-3.656; 3 -2.925,-3.656; 4 -2.275,-3.656; 5 -1.625,-3.656; 6 -0.975,-3.656; 7 -0.325,-3.656; 8 0.325,-3.656; 9 0.975,-3.656; 10 1.625,-3.656; 11 2.275,-3.656; 12 2.925,-3.656; 13 3.575,-3.656; 14 4.225,-3.656; 15 4.225,3.656; 16 3.575,3.656; 17 2.925,3.656; 18 2.275,3.656; 19 1.625,3.656; 20 0.975,3.656; 21 0.325,3.656; 22 -0.325,3.656; 23 -0.975,3.656; 24 -1.625,3.656; 25 -2.275,3.656; 26 -2.925,3.656; 27 -3.575,3.656; 28 -4.225,3.656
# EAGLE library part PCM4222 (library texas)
High-Performance, Two-Channel, 24-Bit, 216kHz Sampling Multi-Bit Delta-Sigma Analog-to-Digital Converter Auto generated by make-symbol-device-package-bsdl.ulp Rev. 29 Source: http://focus.ti.com/lit/ds/symlink/pcm4222.pdf

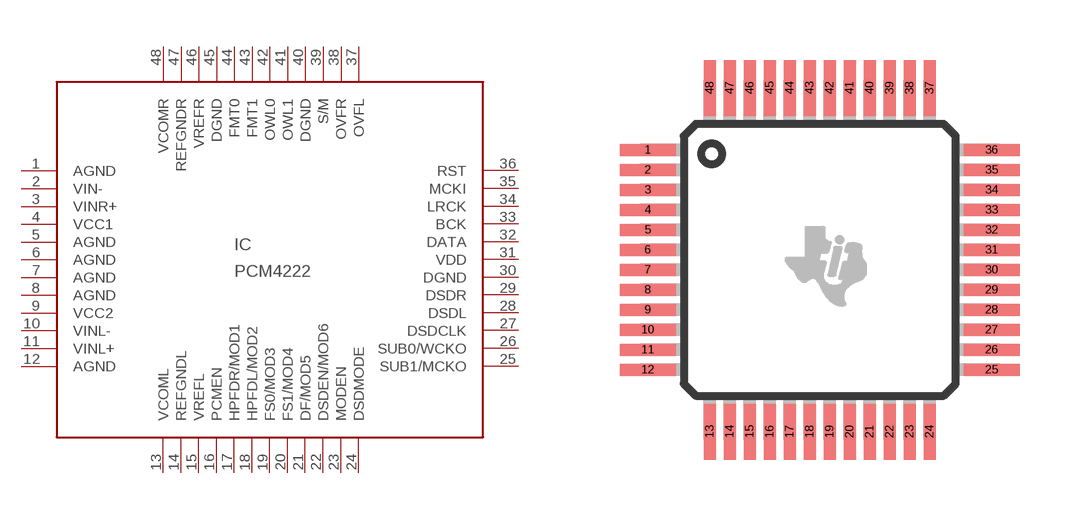
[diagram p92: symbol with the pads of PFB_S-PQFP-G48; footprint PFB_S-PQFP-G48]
Designator prefix IC

## PCM4222 (MPN: PCM4222PFB; OC_FARNELL: 1390708; OC_NEWARK: 36M9296)  [PFB_S-PQFP-G48]
1  AGND  pwr
2  VIN-  in
3  VINR+  in
4  VCC1  pwr
5  AGND  pwr
6  AGND  pwr
7  AGND  pwr
8  AGND  pwr
9  VCC2  pwr
10  VINL-  in
11  VINL+  in
12  AGND  pwr
13  VCOML  out
14  REFGNDL  pwr
15  VREFL  out
16  PCMEN  in
17  HPFDR/MOD1
18  HPFDL/MOD2
19  FS0/MOD3
20  FS1/MOD4
21  DF/MOD5
22  DSDEN/MOD6
23  MODEN  in
24  DSDMODE  in
25  SUB1/MCKO
26  SUB0/WCKO
27  DSDCLK  out
28  DSDL  out
29  DSDR  out
30  DGND  pwr
31  VDD  pwr
32  DATA  out
33  BCK
34  LRCK
35  MCKI  in
36  RST  in
37  OVFL  out
38  OVFR  out
39  S/M  in
40  DGND  out
41  OWL1  in
42  OWL0  in
43  FMT1  in
44  FMT0  in
45  DGND  pwr
46  VREFR  out
47  REFGNDR  pwr
48  VCOMR  out

## Footprint PFB_S-PQFP-G48 (pad centres in mm)
PFB (S-PQFP-G48) Source: http://focus.ti.com/lit/ds/symlink/pcm4220.pdf
smd 1.4 x 0.3: 1 -4.3,2.75; 2 -4.3,2.25; 3 -4.3,1.75; 4 -4.3,1.25; 5 -4.3,0.75; 6 -4.3,0.25; 7 -4.3,-0.25; 8 -4.3,-0.75; 9 -4.3,-1.25; 10 -4.3,-1.75; 11 -4.3,-2.25; 12 -4.3,-2.75; 25 4.3,-2.75; 26 4.3,-2.25; 27 4.3,-1.75; 28 4.3,-1.25; 29 4.3,-0.75; 30 4.3,-0.25; 31 4.3,0.25; 32 4.3,0.75; 33 4.3,1.25; 34 4.3,1.75; 35 4.3,2.25; 36 4.3,2.75
smd 0.3 x 1.4: 13 -2.75,-4.3; 14 -2.25,-4.3; 15 -1.75,-4.3; 16 -1.25,-4.3; 17 -0.75,-4.3; 18 -0.25,-4.3; 19 0.25,-4.3; 20 0.75,-4.3; 21 1.25,-4.3; 22 1.75,-4.3; 23 2.25,-4.3; 24 2.75,-4.3; 37 2.75,4.3; 38 2.25,4.3; 39 1.75,4.3; 40 1.25,4.3; 41 0.75,4.3; 42 0.25,4.3; 43 -0.25,4.3; 44 -0.75,4.3; 45 -1.25,4.3; 46 -1.75,4.3; 47 -2.25,4.3; 48 -2.75,4.3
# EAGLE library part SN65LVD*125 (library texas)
LVDS 4x4 CROSSPOINT SWITCH Source: http://focus.ti.com/lit/ds/symlink/sn65lvds125a.pdf

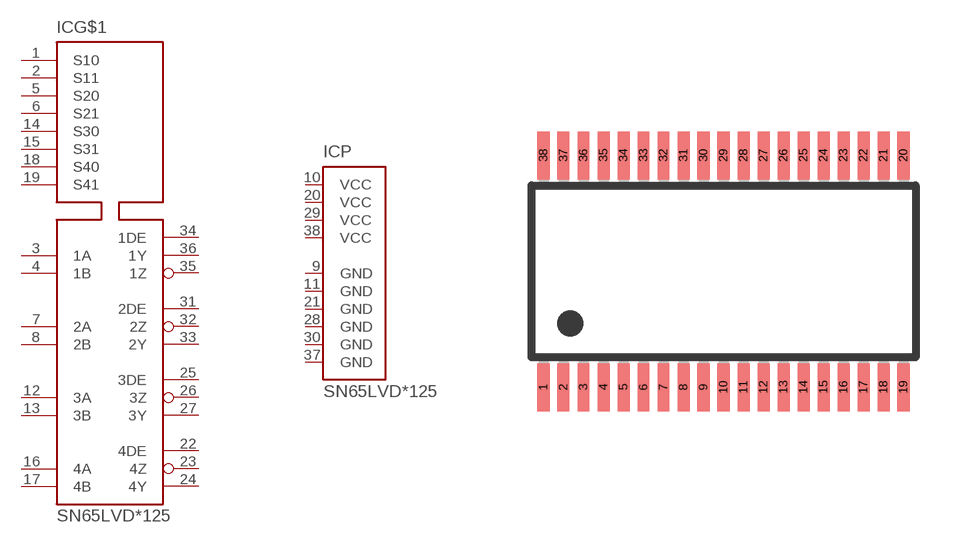
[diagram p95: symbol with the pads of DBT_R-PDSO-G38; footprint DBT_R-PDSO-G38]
Designator prefix IC; gates G$1=SN65LVDS125A P=VCC4-GND6

## SN65LVDS125A (MF: TEXAS INSTRUMENT CONNECTORS; MPN: SN65LVDS125ADBT; OC_FARNELL: 1408802; OC_NEWARK: 01J0701), SN65LVDT125A (MF: TEXAS INSTRUMENT CONNECTORS; MPN: SN65LVDT125ADBTR; OC_FARNELL: 1408842; OC_NEWARK: 01J0706)  [DBT_R-PDSO-G38]
1  G$1:S10  in
2  G$1:S11  in
3  G$1:1A  in
4  G$1:1B  in
5  G$1:S20  in
6  G$1:S21  in
7  G$1:2A  in
8  G$1:2B  in
9  P:GND  in
10  P:VCC  in
11  P:GND  in
12  G$1:3A  in
13  G$1:3B  in
14  G$1:S30  in
15  G$1:S31  in
16  G$1:4A  in
17  G$1:4B  in
18  G$1:S40  in
19  G$1:S41  in
20  P:VCC  in
21  P:GND  in
22  G$1:4DE  in
23  G$1:4Z  out
24  G$1:4Y  out
25  G$1:3DE  in
26  G$1:3Z  out
27  G$1:3Y  out
28  P:GND  in
29  P:VCC  in
30  P:GND  in
31  G$1:2DE  in
32  G$1:2Z  out
33  G$1:2Y  out
34  G$1:1DE  in
35  G$1:1Z  out
36  G$1:1Y  out
37  P:GND  in
38  P:VCC  in

## SN65LVDS125 (MF: TEXAS INSTRUMENT CONNECTORS; MPN: SN65LVDS125ADBT; OC_FARNELL: 1509804; OC_NEWARK: 01J0701), SN65LVDT125 (MF: TEXAS INSTRUMENT CONNECTORS; MPN: SN65LVDT125ADBT; OC_FARNELL: 1408842; OC_NEWARK: 01J0705)  [DBT_R-PDSO-G38]
Pads as for DBT_R-PDSO-G38

## Footprint DBT_R-PDSO-G38 (pad centres in mm)
DBT (R-PSDO-G38) Source: http://focus.ti.com/lit/ml/mpds019g/mpds019g.pdf
smd 0.3 x 1.2: 1 -4.5,-2.9; 2 -4,-2.9; 3 -3.5,-2.9; 4 -3,-2.9; 5 -2.5,-2.9; 6 -2,-2.9; 7 -1.5,-2.9; 8 -1,-2.9; 9 -0.5,-2.9; 10 0,-2.9; 11 0.5,-2.9; 12 1,-2.9; 13 1.5,-2.9; 14 2,-2.9; 15 2.5,-2.9; 16 3,-2.9; 17 3.5,-2.9; 18 4,-2.9; 19 4.5,-2.9; 20 4.5,2.9; 21 4,2.9; 22 3.5,2.9; 23 3,2.9; 24 2.5,2.9; 25 2,2.9; 26 1.5,2.9; 27 1,2.9; 28 0.5,2.9; 29 0,2.9; 30 -0.5,2.9; 31 -1,2.9; 32 -1.5,2.9; 33 -2,2.9; 34 -2.5,2.9; 35 -3,2.9; 36 -3.5,2.9; 37 -4,2.9; 38 -4.5,2.9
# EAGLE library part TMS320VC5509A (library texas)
TMS320VC5509A Fixed-Point Digital Signal Processor Auto generated by make-symbol-device-package-bsdl.ulp Rev. 30 Source: sprm155a.bsm http://focus.ti.com/lit/ds/symlink/tms320vc5509a.pdf

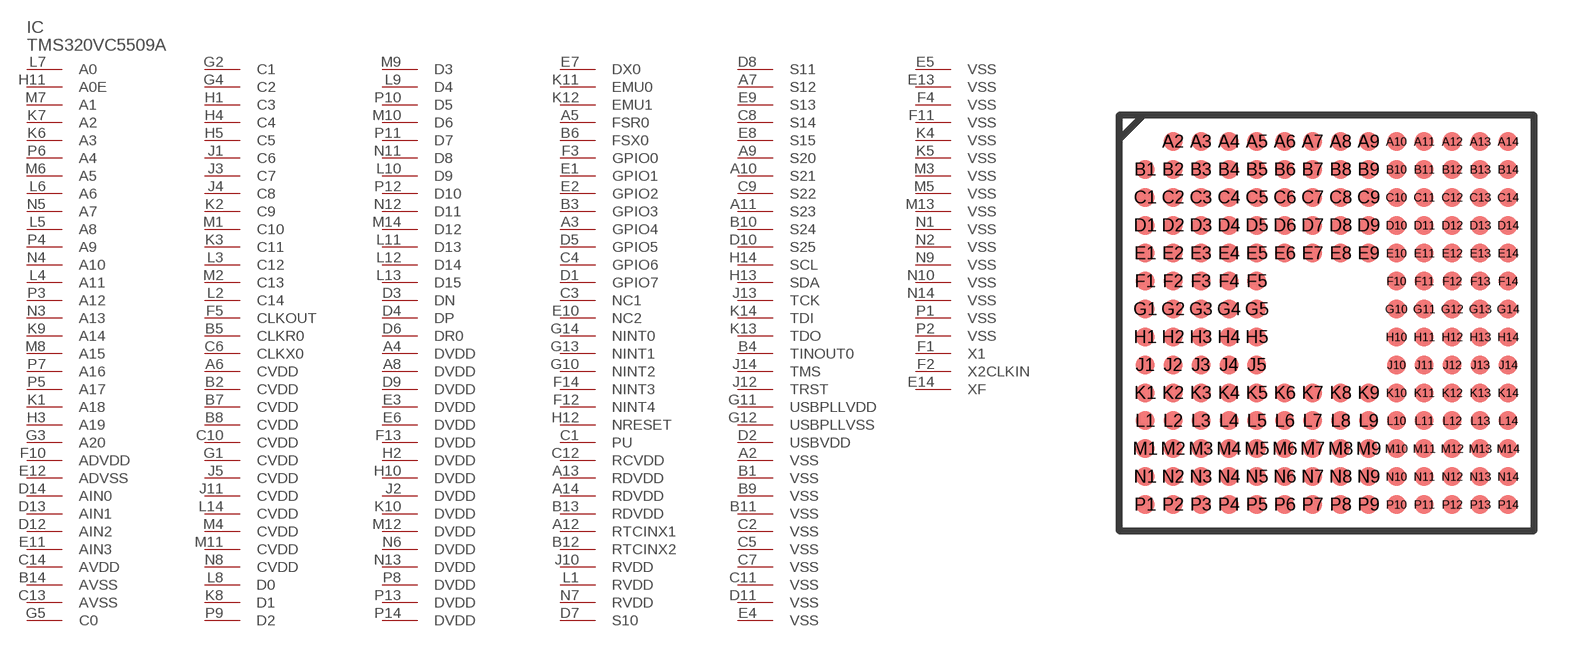
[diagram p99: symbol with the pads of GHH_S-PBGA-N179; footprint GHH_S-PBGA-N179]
Designator prefix IC

## TMS320VC5509A (MF: TEXAS INSTRUMENTS; MPN: TMS320VC5509AGHHR; OC_FARNELL: 1610194; OC_NEWARK: 92H7535)  [GHH_S-PBGA-N179]
A2  VSS  pwr
A3  GPIO4
A4  DVDD  pwr
A5  FSR0
A6  CVDD  pwr
A7  S12
A8  DVDD  pwr
A9  S20
A10  S21
A11  S23
A12  RTCINX1  pas
A13  RDVDD  pwr
A14  RDVDD  pwr
B1  VSS  pwr
B2  CVDD  pwr
B3  GPIO3
B4  TINOUT0
B5  CLKR0
B6  FSX0
B7  CVDD  pwr
B8  CVDD  pwr
B9  VSS  pwr
B10  S24
B11  VSS  pwr
B12  RTCINX2  pas
B13  RDVDD  pwr
B14  AVSS  pwr
C1  PU  pas
C2  VSS  pwr
C3  NC1  pas
C4  GPIO6
C5  VSS  pwr
C6  CLKX0
C7  VSS  pwr
C8  S14
C9  S22
C10  CVDD  pwr
C11  VSS  pwr
C12  RCVDD  pwr
C13  AVSS  pwr
C14  AVDD  pwr
D1  GPIO7
D2  USBVDD  pwr
D3  DN  pas
D4  DP  pas
D5  GPIO5
D6  DR0  in
D7  S10
D8  S11
D9  DVDD  pwr
D10  S25
D11  VSS  pwr
D12  AIN2  pas
D13  AIN1  pas
D14  AIN0  pas
E1  GPIO1
E2  GPIO2
E3  DVDD  pwr
E4  VSS  pwr
E5  VSS  pwr
E6  DVDD  pwr
E7  DX0  out
E8  S15
E9  S13
E10  NC2  pas
E11  AIN3  pas
E12  ADVSS  pwr
E13  VSS  pwr
E14  XF  out
F1  X1  pas
F2  X2CLKIN  in
F3  GPIO0
F4  VSS  pwr
F5  CLKOUT  out
F10  ADVDD  pwr
F11  VSS  pwr
F12  NINT4  in
F13  DVDD  pwr
F14  NINT3  in
G1  CVDD  pwr
G2  C1  out
G3  A20  out
G4  C2
G5  C0
G10  NINT2  in
G11  USBPLLVDD  pwr
G12  USBPLLVSS  pwr
G13  NINT1  in
G14  NINT0  in
H1  C3
H2  DVDD  pwr
H3  A19  out
H4  C4
H5  C5
H10  DVDD  pwr
H11  A0E  out
H12  NRESET  in
H13  SDA
H14  SCL
J1  C6
J2  DVDD  pwr
J3  C7
J4  C8
J5  CVDD  pwr
J10  RVDD  pwr
J11  CVDD  pwr
J12  TRST  in
J13  TCK  in
J14  TMS  in
K1  A18  out
K2  C9
K3  C11
K4  VSS  pwr
K5  VSS  pwr
K6  A3
K7  A2
K8  D1
K9  A14
K10  DVDD  pwr
K11  EMU0  in
K12  EMU1  in
K13  TDO  out
K14  TDI  in
L1  RVDD  pwr
L2  C14
L3  C12
L4  A11
L5  A8
L6  A6
L7  A0
L8  D0
L9  D4
L10  D9
L11  D13
L12  D14
L13  D15
L14  CVDD  pwr
M1  C10
M2  C13
M3  VSS  pwr
M4  CVDD  pwr
M5  VSS  pwr
M6  A5
M7  A1
M8  A15
M9  D3
M10  D6
M11  CVDD  pwr
M12  DVDD  pwr
M13  VSS  pwr
M14  D12
N1  VSS  pwr
N2  VSS  pwr
N3  A13
N4  A10
N5  A7
N6  DVDD  pwr
N7  RVDD  pwr
N8  CVDD  pwr
N9  VSS  pwr
N10  VSS  pwr
N11  D8
N12  D11
N13  DVDD  pwr
N14  VSS  pwr
P1  VSS  pwr
P2  VSS  pwr
P3  A12
P4  A9
P5  A17  out
P6  A4
P7  A16  out
P8  DVDD  pwr
P9  D2
P10  D5
P11  D7
P12  D10
P13  DVDD  pwr
P14  DVDD  pwr

## Footprint GHH_S-PBGA-N179 (pad centres in mm)
GHH (S-PBGA-N179) Auto generated by make-symbol-device-package-bsdl.ulp Rev. 30 Source: sprm155a.bsm http://focus.ti.com/lit/ds/symlink/tms320vc5509a.pdf
smd 0.55 x 0.55: A2 -4.4,5.2; A3 -3.6,5.2; A4 -2.8,5.2; A5 -2,5.2; A6 -1.2,5.2; A7 -0.4,5.2; A8 0.4,5.2; A9 1.2,5.2; A10 2,5.2; A11 2.8,5.2; A12 3.6,5.2; A13 4.4,5.2; A14 5.2,5.2; B1 -5.2,4.4; B2 -4.4,4.4; B3 -3.6,4.4; B4 -2.8,4.4; B5 -2,4.4; B6 -1.2,4.4; B7 -0.4,4.4; B8 0.4,4.4; B9 1.2,4.4; B10 2,4.4; B11 2.8,4.4; B12 3.6,4.4; B13 4.4,4.4; B14 5.2,4.4; C1 -5.2,3.6; C2 -4.4,3.6; C3 -3.6,3.6; C4 -2.8,3.6; C5 -2,3.6; C6 -1.2,3.6; C7 -0.4,3.6; C8 0.4,3.6; C9 1.2,3.6; C10 2,3.6; C11 2.8,3.6; C12 3.6,3.6; C13 4.4,3.6; C14 5.2,3.6; D1 -5.2,2.8; D2 -4.4,2.8; D3 -3.6,2.8; D4 -2.8,2.8; D5 -2,2.8; D6 -1.2,2.8; D7 -0.4,2.8; D8 0.4,2.8; D9 1.2,2.8; D10 2,2.8; D11 2.8,2.8; D12 3.6,2.8; D13 4.4,2.8; D14 5.2,2.8; E1 -5.2,2; E2 -4.4,2; E3 -3.6,2; E4 -2.8,2; E5 -2,2; E6 -1.2,2; E7 -0.4,2; E8 0.4,2; E9 1.2,2; E10 2,2; E11 2.8,2; E12 3.6,2; E13 4.4,2; E14 5.2,2; F1 -5.2,1.2; F2 -4.4,1.2; F3 -3.6,1.2; F4 -2.8,1.2; F5 -2,1.2; F10 2,1.2; F11 2.8,1.2; F12 3.6,1.2; F13 4.4,1.2; F14 5.2,1.2; G1 -5.2,0.4; G2 -4.4,0.4; G3 -3.6,0.4; G4 -2.8,0.4; G5 -2,0.4; G10 2,0.4; G11 2.8,0.4; G12 3.6,0.4; G13 4.4,0.4; G14 5.2,0.4; H1 -5.2,-0.4; H2 -4.4,-0.4; H3 -3.6,-0.4; H4 -2.8,-0.4; H5 -2,-0.4; H10 2,-0.4; H11 2.8,-0.4; H12 3.6,-0.4; H13 4.4,-0.4; H14 5.2,-0.4; J1 -5.2,-1.2; J2 -4.4,-1.2; J3 -3.6,-1.2; J4 -2.8,-1.2; J5 -2,-1.2; J10 2,-1.2; J11 2.8,-1.2; J12 3.6,-1.2; J13 4.4,-1.2; J14 5.2,-1.2; K1 -5.2,-2; K2 -4.4,-2; K3 -3.6,-2; K4 -2.8,-2; K5 -2,-2; K6 -1.2,-2; K7 -0.4,-2; K8 0.4,-2; K9 1.2,-2; K10 2,-2; K11 2.8,-2; K12 3.6,-2; K13 4.4,-2; K14 5.2,-2; L1 -5.2,-2.8; L2 -4.4,-2.8; L3 -3.6,-2.8; L4 -2.8,-2.8; L5 -2,-2.8; L6 -1.2,-2.8; L7 -0.4,-2.8; L8 0.4,-2.8; L9 1.2,-2.8; L10 2,-2.8; L11 2.8,-2.8; L12 3.6,-2.8; L13 4.4,-2.8; L14 5.2,-2.8; M1 -5.2,-3.6; M2 -4.4,-3.6; M3 -3.6,-3.6; M4 -2.8,-3.6; M5 -2,-3.6; M6 -1.2,-3.6; M7 -0.4,-3.6; M8 0.4,-3.6; M9 1.2,-3.6; M10 2,-3.6; M11 2.8,-3.6; M12 3.6,-3.6; M13 4.4,-3.6; M14 5.2,-3.6; N1 -5.2,-4.4; N2 -4.4,-4.4; N3 -3.6,-4.4; N4 -2.8,-4.4; N5 -2,-4.4; N6 -1.2,-4.4; N7 -0.4,-4.4; N8 0.4,-4.4; N9 1.2,-4.4; N10 2,-4.4; N11 2.8,-4.4; N12 3.6,-4.4; N13 4.4,-4.4; N14 5.2,-4.4; P1 -5.2,-5.2; P2 -4.4,-5.2; P3 -3.6,-5.2; P4 -2.8,-5.2; P5 -2,-5.2; P6 -1.2,-5.2; P7 -0.4,-5.2; P8 0.4,-5.2; P9 1.2,-5.2; P10 2,-5.2; P11 2.8,-5.2; P12 3.6,-5.2; P13 4.4,-5.2; P14 5.2,-5.2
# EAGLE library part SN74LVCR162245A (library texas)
16-BIT BUS TRANSCEIVER WITH 3-STATE OUTPUTS Auto generated by make-symbol-device-package-bsdl.ulp Rev. 33 Source: http://focus.ti.com/lit/ds/symlink/sn74lvcr162245.pdf

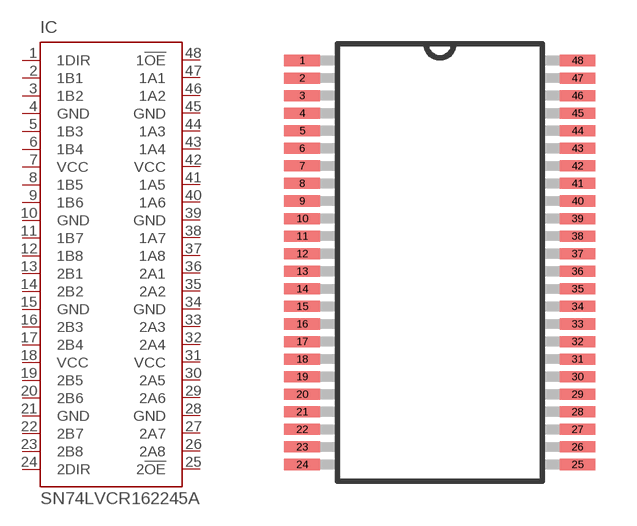
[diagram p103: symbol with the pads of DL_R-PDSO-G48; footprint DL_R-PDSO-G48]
Designator prefix IC

## SN74LVCR162245A (MPN: SN74LVCR162245DL; OC_FARNELL: 1739707; OC_NEWARK: 50R6613)  [DL_R-PDSO-G48]
1  1DIR  in
2  1B1  hiz
3  1B2  hiz
4  GND  pwr
5  1B3  hiz
6  1B4  hiz
7  VCC  pwr
8  1B5  hiz
9  1B6  hiz
10  GND  pwr
11  1B7  hiz
12  1B8  hiz
13  2B1  hiz
14  2B2  hiz
15  GND  pwr
16  2B3  hiz
17  2B4  hiz
18  VCC  pwr
19  2B5  hiz
20  2B6  hiz
21  GND  hiz
22  2B7  hiz
23  2B8  hiz
24  2DIR  in
25  2!OE  in
26  2A8  hiz
27  2A7  hiz
28  GND  pwr
29  2A6  hiz
30  2A5  hiz
31  VCC  pwr
32  2A4  hiz
33  2A3  hiz
34  GND  pwr
35  2A2  hiz
36  2A1  hiz
37  1A8  hiz
38  1A7  hiz
39  GND  hiz
40  1A6  hiz
41  1A5  hiz
42  VCC  pwr
43  1A4  hiz
44  1A3  hiz
45  GND  pwr
46  1A2  hiz
47  1A1  hiz
48  1!OE  in

## Footprint DL_R-PDSO-G48 (pad centres in mm)
DL_R-PDSO-G48 Auto generated by make-symbol-device-package-bsdl.ulp Rev. 33
smd 1.3 x 0.4: 1 -4.98,7.303; 2 -4.98,6.668; 3 -4.98,6.032; 4 -4.98,5.397; 5 -4.98,4.763; 6 -4.98,4.128; 7 -4.98,3.493; 8 -4.98,2.857; 9 -4.98,2.223; 10 -4.98,1.587; 11 -4.98,0.953; 12 -4.98,0.318; 13 -4.98,-0.318; 14 -4.98,-0.953; 15 -4.98,-1.587; 16 -4.98,-2.223; 17 -4.98,-2.857; 18 -4.98,-3.493; 19 -4.98,-4.128; 20 -4.98,-4.763; 21 -4.98,-5.397; 22 -4.98,-6.032; 23 -4.98,-6.668; 24 -4.98,-7.303; 25 4.98,-7.303; 26 4.98,-6.668; 27 4.98,-6.032; 28 4.98,-5.397; 29 4.98,-4.763; 30 4.98,-4.128; 31 4.98,-3.493; 32 4.98,-2.857; 33 4.98,-2.223; 34 4.98,-1.587; 35 4.98,-0.953; 36 4.98,-0.318; 37 4.98,0.318; 38 4.98,0.953; 39 4.98,1.587; 40 4.98,2.223; 41 4.98,2.857; 42 4.98,3.493; 43 4.98,4.128; 44 4.98,4.763; 45 4.98,5.397; 46 4.98,6.032; 47 4.98,6.668; 48 4.98,7.303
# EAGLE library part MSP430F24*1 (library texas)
MIXED SIGNAL MICROCONTROLLER Source: http://focus.ti.com/lit/ds/symlink/msp430f2471.pdf

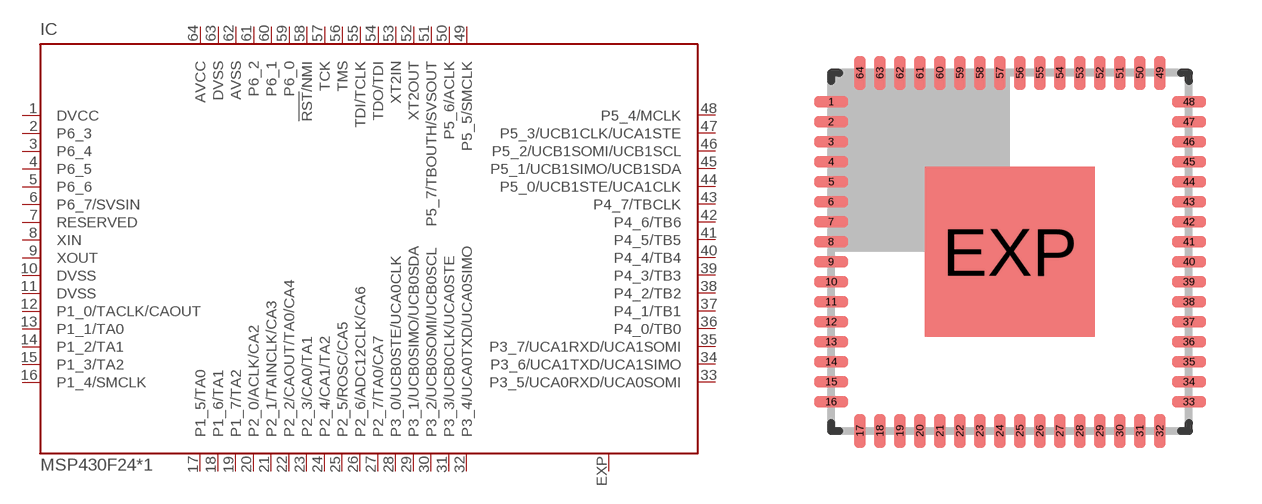
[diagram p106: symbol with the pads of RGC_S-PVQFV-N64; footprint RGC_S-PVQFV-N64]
Designator prefix IC

## MSP430F2471TRGC (OC_FARNELL: unknown; OC_NEWARK: unknown), MSP430F2481TRGC (OC_FARNELL: 1753309; OC_NEWARK: unknown), MSP430F2491TRGC (MPN: MSP430F2491TRGCT; OC_FARNELL: 1649447; OC_NEWARK: 65M1728)  [RGC_S-PVQFV-N64]
1  DVCC  pwr
2  P6_3
3  P6_4
4  P6_5
5  P6_6
6  P6_7/SVSIN
7  RESERVED  out
8  XIN  in
9  XOUT  out
10  DVSS  in
11  DVSS  in
12  P1_0/TACLK/CAOUT
13  P1_1/TA0
14  P1_2/TA1
15  P1_3/TA2
16  P1_4/SMCLK
17  P1_5/TA0
18  P1_6/TA1
19  P1_7/TA2
20  P2_0/ACLK/CA2
21  P2_1/TAINCLK/CA3
22  P2_2/CAOUT/TA0/CA4
23  P2_3/CA0/TA1
24  P2_4/CA1/TA2
25  P2_5/ROSC/CA5
26  P2_6/ADC12CLK/CA6
27  P2_7/TA0/CA7
28  P3_0/UCB0STE/UCA0CLK
29  P3_1/UCB0SIMO/UCB0SDA
30  P3_2/UCB0SOMI/UCB0SCL
31  P3_3/UCB0CLK/UCA0STE
32  P3_4/UCA0TXD/UCA0SIMO
33  P3_5/UCA0RXD/UCA0SOMI
34  P3_6/UCA1TXD/UCA1SIMO
35  P3_7/UCA1RXD/UCA1SOMI
36  P4_0/TB0
37  P4_1/TB1
38  P4_2/TB2
39  P4_3/TB3
40  P4_4/TB4
41  P4_5/TB5
42  P4_6/TB6
43  P4_7/TBCLK
44  P5_0/UCB1STE/UCA1CLK
45  P5_1/UCB1SIMO/UCB1SDA
46  P5_2/UCB1SOMI/UCB1SCL
47  P5_3/UCB1CLK/UCA1STE
48  P5_4/MCLK
49  P5_5/SMCLK
50  P5_6/ACLK
51  P5_7/TBOUTH/SVSOUT
52  XT2OUT  out
53  XT2IN  in
54  TDO/TDI
55  TDI/TCLK  in
56  TMS  in
57  TCK  in
58  !RST!/NMI  in
59  P6_0
60  P6_1
61  P6_2
62  AVSS  pwr
63  DVSS  pwr
64  AVCC  pwr
EXP  EXP  pas

## Footprint RGC_S-PVQFV-N64 (pad centres in mm)
RGC(S-PVQFN-N64) CUSTOM DEVICE PASTRIC QUAD FLATPACK NO-LEAD Source: http://focus.ti.com/lit/ds/symlink/msp430f2471.pdf
smd 0.85 x 0.28: 1 -4.475,3.75; 2 -4.475,3.25; 3 -4.475,2.75; 4 -4.475,2.25; 5 -4.475,1.75; 6 -4.475,1.25; 7 -4.475,0.75; 8 -4.475,0.25; 9 -4.475,-0.25; 10 -4.475,-0.75; 11 -4.475,-1.25; 12 -4.475,-1.75; 13 -4.475,-2.25; 14 -4.475,-2.75; 15 -4.475,-3.25; 16 -4.475,-3.75; 33 4.475,-3.75; 34 4.475,-3.25; 35 4.475,-2.75; 36 4.475,-2.25; 37 4.475,-1.75; 38 4.475,-1.25; 39 4.475,-0.75; 40 4.475,-0.25; 41 4.475,0.25; 42 4.475,0.75; 43 4.475,1.25; 44 4.475,1.75; 45 4.475,2.25; 46 4.475,2.75; 47 4.475,3.25; 48 4.475,3.75
smd 0.28 x 0.85: 17 -3.75,-4.475; 18 -3.25,-4.475; 19 -2.75,-4.475; 20 -2.25,-4.475; 21 -1.75,-4.475; 22 -1.25,-4.475; 23 -0.75,-4.475; 24 -0.25,-4.475; 25 0.25,-4.475; 26 0.75,-4.475; 27 1.25,-4.475; 28 1.75,-4.475; 29 2.25,-4.475; 30 2.75,-4.475; 31 3.25,-4.475; 32 3.75,-4.475; 49 3.75,4.475; 50 3.25,4.475; 51 2.75,4.475; 52 2.25,4.475; 53 1.75,4.475; 54 1.25,4.475; 55 0.75,4.475; 56 0.25,4.475; 57 -0.25,4.475; 58 -0.75,4.475; 59 -1.25,4.475; 60 -1.75,4.475; 61 -2.25,4.475; 62 -2.75,4.475; 63 -3.25,4.475; 64 -3.75,4.475
smd 4.25 x 4.25: EXP 0,0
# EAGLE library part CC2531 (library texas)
A USB Enabled System-On-Chip Solution for 2.4-GHz IEEE 802.15.4 and ZigBee Source: http://focus.ti.com/lit/ds/symlink/cc2531.pdf

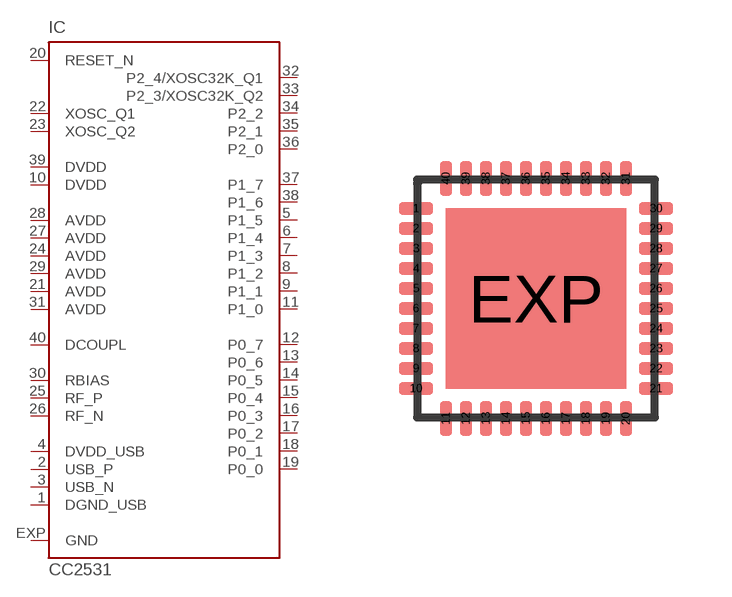
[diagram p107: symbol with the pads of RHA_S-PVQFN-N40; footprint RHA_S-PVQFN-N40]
Designator prefix IC

## CC2531 (MPN: CC2531F256RHAT; OC_FARNELL: 1776351; OC_NEWARK: 34R2713)  [RHA_S-PVQFN-N40]
1  DGND_USB  pwr
2  USB_P
3  USB_N
4  DVDD_USB  pwr
5  P1_5
6  P1_4
7  P1_3
8  P1_2
9  P1_1
10  DVDD  pwr
11  P1_0
12  P0_7
13  P0_6
14  P0_5
15  P0_4
16  P0_3
17  P0_2
18  P0_1
19  P0_0
20  RESET_N  in
21  AVDD  pwr
22  XOSC_Q1
23  XOSC_Q2
24  AVDD  pwr
25  RF_P
26  RF_N
27  AVDD  pwr
28  AVDD  pwr
29  AVDD  pwr
30  RBIAS
31  AVDD  pwr
32  P2_4/XOSC32K_Q1
33  P2_3/XOSC32K_Q2
34  P2_2
35  P2_1
36  P2_0
37  P1_7
38  P1_6
39  DVDD  pwr
40  DCOUPL  pwr
EXP  GND  pas

## Footprint RHA_S-PVQFN-N40 (pad centres in mm)
RHA (S-PVQFN-N40) Source: http://focus.ti.com/lit/ds/symlink/cc2531.pdf
smd 0.85 x 0.3: 1 -3,2.25; 2 -3,1.75; 3 -3,1.25; 4 -3,0.75; 5 -3,0.25; 6 -3,-0.25; 7 -3,-0.75; 8 -3,-1.25; 9 -3,-1.75; 10 -3,-2.25; 21 3,-2.25; 22 3,-1.75; 23 3,-1.25; 24 3,-0.75; 25 3,-0.25; 26 3,0.25; 27 3,0.75; 28 3,1.25; 29 3,1.75; 30 3,2.25
smd 0.3 x 0.85: 11 -2.25,-3; 12 -1.75,-3; 13 -1.25,-3; 14 -0.75,-3; 15 -0.25,-3; 16 0.25,-3; 17 0.75,-3; 18 1.25,-3; 19 1.75,-3; 20 2.25,-3; 31 2.25,3; 32 1.75,3; 33 1.25,3; 34 0.75,3; 35 0.25,3; 36 -0.25,3; 37 -0.75,3; 38 -1.25,3; 39 -1.75,3; 40 -2.25,3
smd 4.5 x 4.5: EXP 0,0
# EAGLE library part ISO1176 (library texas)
ISOLATED RS-485 PROFIBUS TRANSCEIVER Source: Data sheet

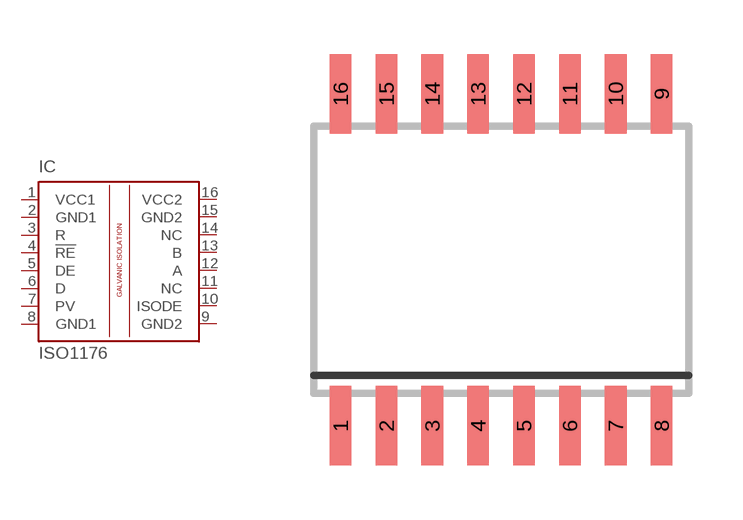
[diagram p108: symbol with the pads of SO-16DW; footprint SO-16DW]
Designator prefix IC

## ISO1176 (MPN: ISO1176DW; OC_FARNELL: 1755037; OC_NEWARK: 13N4111)  [SO-16DW]
1  VCC1  in
2  GND1  in
3  R  in
4  !RE  in
5  DE  in
6  D  in
7  PV  in
8  GND1  in
9  GND2  in
10  ISODE  in
11  NC  in
12  A  in
13  B  in
14  NC  in
15  GND2  in
16  VCC2  in

## Footprint SO-16DW (pad centres in mm)
DW (RPDSO-G16) Source: http://focus.ti.com/lit/ds/symlink/iso1176.pdf
smd 0.6 x 2.2: 1 -4.445,-4.6; 2 -3.175,-4.6; 3 -1.905,-4.6; 4 -0.635,-4.6; 5 0.635,-4.6; 6 1.905,-4.6; 7 3.175,-4.6; 8 4.445,-4.6; 9 4.445,4.6; 10 3.175,4.6; 11 1.905,4.6; 12 0.635,4.6; 13 -0.635,4.6; 14 -1.905,4.6; 15 -3.175,4.6; 16 -4.445,4.6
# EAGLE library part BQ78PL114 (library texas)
PowerLAN (TM) Master Gateway Battery Management Controller With PowerPump(TM) Cell Balancing Technology Auto generated by make-symbol-device-package-bsdl.ulp Rev. 35 Source: Datasheet

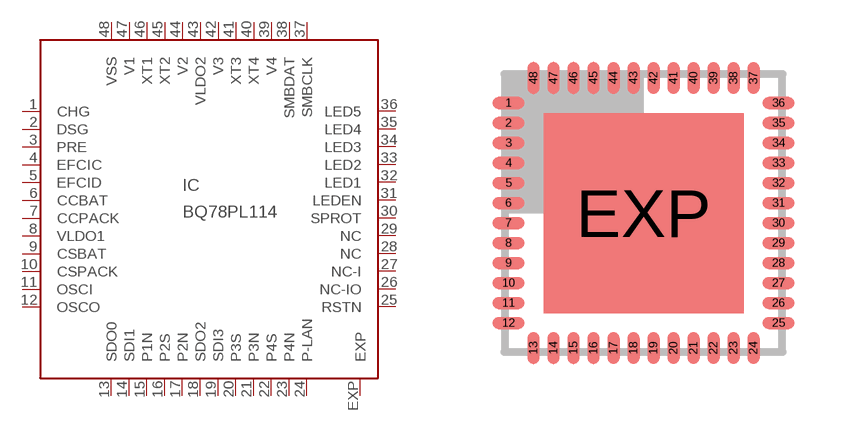
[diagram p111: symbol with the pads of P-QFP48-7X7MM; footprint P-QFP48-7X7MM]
Designator prefix IC

## BQ78PL114 (MPN: BQ78PL114RGZR; OC_FARNELL: 1684746; OC_NEWARK: 12P8640)  [P-QFP48-7X7MM]
1  CHG  out
2  DSG  out
3  PRE  out
4  EFCIC  in
5  EFCID  in
6  CCBAT  in
7  CCPACK  in
8  VLDO1  pwr
9  CSBAT  in
10  CSPACK  in
11  OSCI  in
12  OSCO  out
13  SDO0  out
14  SDI1  in
15  P1N  out
16  P2S  out
17  P2N  out
18  SDO2  out
19  SDI3  in
20  P3S  out
21  P3N  out
22  P4S  out
23  P4N  out
24  P-LAN
25  RSTN  in
26  NC-IO
27  NC-I  in
28  NC  nc
29  NC  nc
30  SPROT  out
31  LEDEN
32  LED1  out
33  LED2  out
34  LED3  out
35  LED4  out
36  LED5  out
37  SMBCLK
38  SMBDAT
39  V4  in
40  XT4  in
41  XT3  in
42  V3  in
43  VLDO2  pwr
44  V2  in
45  XT2  in
46  XT1  in
47  V1  in
48  VSS  in
EXP  EXP  pas

## Footprint P-QFP48-7X7MM (pad centres in mm)
P-QFP48 7x7mm Auto generated by make-symbol-device-package-bsdl.ulp Rev. 35 Source: Datasheet
smd 0.8 x 0.3: 1 -3.375,2.75; 2 -3.375,2.25; 3 -3.375,1.75; 4 -3.375,1.25; 5 -3.375,0.75; 6 -3.375,0.25; 7 -3.375,-0.25; 8 -3.375,-0.75; 9 -3.375,-1.25; 10 -3.375,-1.75; 11 -3.375,-2.25; 12 -3.375,-2.75; 25 3.375,-2.75; 26 3.375,-2.25; 27 3.375,-1.75; 28 3.375,-1.25; 29 3.375,-0.75; 30 3.375,-0.25; 31 3.375,0.25; 32 3.375,0.75; 33 3.375,1.25; 34 3.375,1.75; 35 3.375,2.25; 36 3.375,2.75
smd 0.3 x 0.8: 13 -2.75,-3.375; 14 -2.25,-3.375; 15 -1.75,-3.375; 16 -1.25,-3.375; 17 -0.75,-3.375; 18 -0.25,-3.375; 19 0.25,-3.375; 20 0.75,-3.375; 21 1.25,-3.375; 22 1.75,-3.375; 23 2.25,-3.375; 24 2.75,-3.375; 37 2.75,3.375; 38 2.25,3.375; 39 1.75,3.375; 40 1.25,3.375; 41 0.75,3.375; 42 0.25,3.375; 43 -0.25,3.375; 44 -0.75,3.375; 45 -1.25,3.375; 46 -1.75,3.375; 47 -2.25,3.375; 48 -2.75,3.375
smd 5 x 5: EXP 0,0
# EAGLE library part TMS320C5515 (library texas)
TMS320C5515 Auto generated by make-symbol-device-package-bsdl.ulp Rev. 36 Source: Data sheet

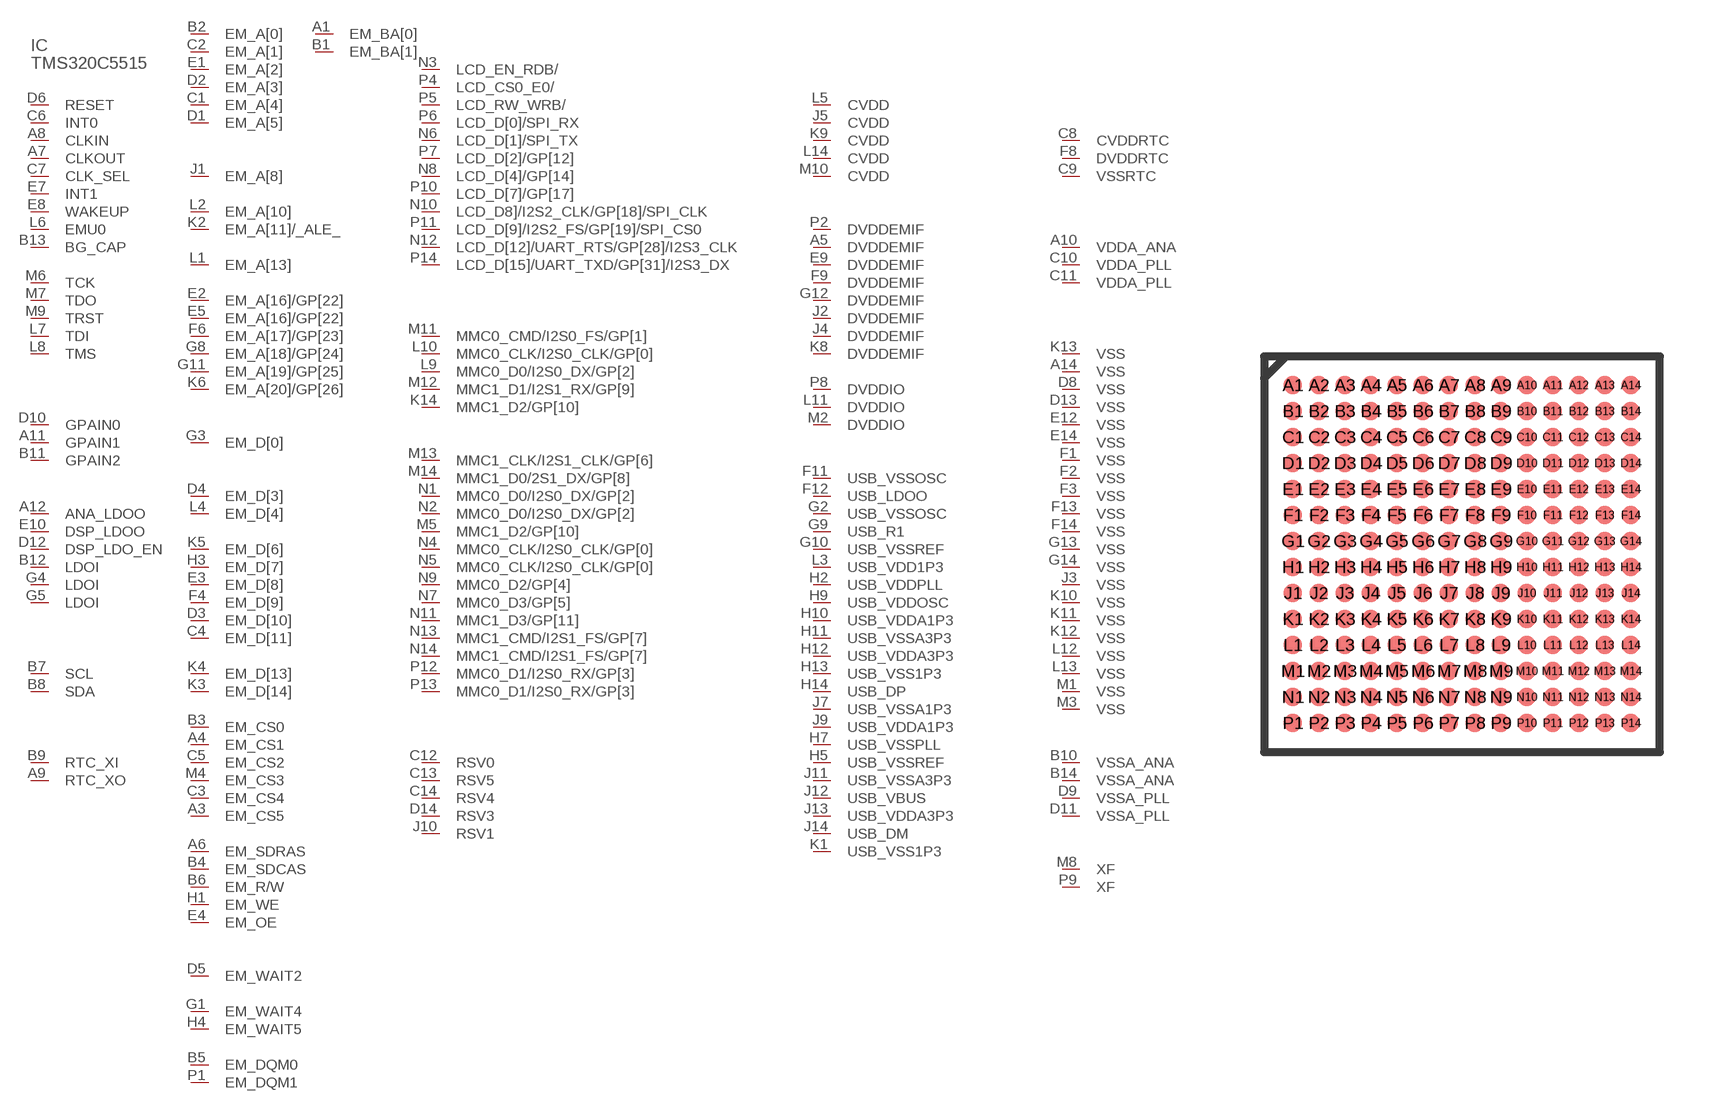
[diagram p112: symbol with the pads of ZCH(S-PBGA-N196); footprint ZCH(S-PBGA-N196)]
Designator prefix IC

## TMS320C5515  [ZCH(S-PBGA-N196)]
A1  EM_BA[0]
A3  EM_CS5
A4  EM_CS1
A5  DVDDEMIF  pwr
A6  EM_SDRAS
A7  CLKOUT
A8  CLKIN  in
A9  RTC_XO  in
A10  VDDA_ANA  pwr
A11  GPAIN1
A12  ANA_LDOO  pwr
A14  VSS  pwr
B1  EM_BA[1]
B2  EM_A[0]  hiz
B3  EM_CS0
B4  EM_SDCAS
B5  EM_DQM0
B6  EM_R/W
B7  SCL  hiz
B8  SDA  hiz
B9  RTC_XI  in
B10  VSSA_ANA  pwr
B11  GPAIN2
B12  LDOI  pwr
B13  BG_CAP  out
B14  VSSA_ANA  pwr
C1  EM_A[4]  hiz
C2  EM_A[1]  hiz
C3  EM_CS4
C4  EM_D[11]  hiz
C5  EM_CS2
C6  INT0  in
C7  CLK_SEL  in
C8  CVDDRTC  pwr
C9  VSSRTC  pwr
C10  VDDA_PLL  pwr
C11  VDDA_PLL
C12  RSV0  in
C13  RSV5  in
C14  RSV4  in
D1  EM_A[5]  hiz
D2  EM_A[3]  hiz
D3  EM_D[10]  hiz
D4  EM_D[3]  hiz
D5  EM_WAIT2  in
D6  RESET  in
D8  VSS
D9  VSSA_PLL  pwr
D10  GPAIN0
D11  VSSA_PLL  pwr
D12  DSP_LDO_EN  in
D13  VSS  in
D14  RSV3  in
E1  EM_A[2]  hiz
E2  EM_A[16]/GP[22]  hiz
E3  EM_D[8]  hiz
E4  EM_OE
E5  EM_A[16]/GP[22]  hiz
E7  INT1  in
E8  WAKEUP  hiz
E9  DVDDEMIF  pwr
E10  DSP_LDOO  pwr
E12  VSS  pwr
E14  VSS  pwr
F1  VSS  hiz
F2  VSS  hiz
F3  VSS  hiz
F4  EM_D[9]  hiz
F6  EM_A[17]/GP[23]  pwr
F8  DVDDRTC  pwr
F9  DVDDEMIF  pwr
F11  USB_VSSOSC  pwr
F12  USB_LDOO  pwr
F13  VSS  pwr
F14  VSS  pwr
G1  EM_WAIT4  in
G2  USB_VSSOSC  hiz
G3  EM_D[0]  hiz
G4  LDOI  pwr
G5  LDOI  pwr
G8  EM_A[18]/GP[24]  pwr
G9  USB_R1
G10  USB_VSSREF  pwr
G11  EM_A[19]/GP[25]  pwr
G12  DVDDEMIF  pwr
G13  VSS  in
G14  VSS  out
H1  EM_WE
H2  USB_VDDPLL  hiz
H3  EM_D[7]  hiz
H4  EM_WAIT5  in
H5  USB_VSSREF  pwr
H7  USB_VSSPLL  pwr
H9  USB_VDDOSC  pwr
H10  USB_VDDA1P3  pwr
H11  USB_VSSA3P3  pwr
H12  USB_VDDA3P3  pwr
H13  USB_VSS1P3  pwr
H14  USB_DP
J1  EM_A[8]  hiz
J2  DVDDEMIF  hiz
J3  VSS  hiz
J4  DVDDEMIF  hiz
J5  CVDD  pwr
J7  USB_VSSA1P3  pwr
J9  USB_VDDA1P3  pwr
J10  RSV1  pwr
J11  USB_VSSA3P3  pwr
J12  USB_VBUS
J13  USB_VDDA3P3  pwr
J14  USB_DM
K1  USB_VSS1P3  hiz
K2  EM_A[11]/_ALE_  hiz
K3  EM_D[14]  hiz
K4  EM_D[13]  hiz
K5  EM_D[6]  hiz
K6  EM_A[20]/GP[26]  in
K8  DVDDEMIF  pwr
K9  CVDD  pwr
K10  VSS  pwr
K11  VSS  pwr
K12  VSS  pwr
K13  VSS  pwr
K14  MMC1_D2/GP[10]  hiz
L1  EM_A[13]  hiz
L2  EM_A[10]  hiz
L3  USB_VDD1P3  hiz
L4  EM_D[4]  hiz
L5  CVDD  pwr
L6  EMU0  hiz
L7  TDI  in
L8  TMS  in
L9  MMC0_D0/I2S0_DX/GP[2]  hiz
L10  MMC0_CLK/I2S0_CLK/GP[0]  hiz
L11  DVDDIO  hiz
L12  VSS  hiz
L13  VSS  hiz
L14  CVDD  hiz
M1  VSS  hiz
M2  DVDDIO  hiz
M3  VSS
M4  EM_CS3
M5  MMC1_D2/GP[10]  hiz
M6  TCK  in
M7  TDO
M8  XF
M9  TRST  in
M10  CVDD  hiz
M11  MMC0_CMD/I2S0_FS/GP[1]  hiz
M12  MMC1_D1/I2S1_RX/GP[9]  hiz
M13  MMC1_CLK/I2S1_CLK/GP[6]  hiz
M14  MMC1_D0/2S1_DX/GP[8]  hiz
N1  MMC0_D0/I2S0_DX/GP[2]  hiz
N2  MMC0_D0/I2S0_DX/GP[2]
N3  LCD_EN_RDB/
N4  MMC0_CLK/I2S0_CLK/GP[0]  hiz
N5  MMC0_CLK/I2S0_CLK/GP[0]  hiz
N6  LCD_D[1]/SPI_TX  hiz
N7  MMC0_D3/GP[5]  hiz
N8  LCD_D[4]/GP[14]  hiz
N9  MMC0_D2/GP[4]  hiz
N10  LCD_D8]/I2S2_CLK/GP[18]/SPI_CLK  hiz
N11  MMC1_D3/GP[11]  hiz
N12  LCD_D[12]/UART_RTS/GP[28]/I2S3_CLK  hiz
N13  MMC1_CMD/I2S1_FS/GP[7]
N14  MMC1_CMD/I2S1_FS/GP[7]  pwr
P1  EM_DQM1
P2  DVDDEMIF  pwr
P4  LCD_CS0_E0/  hiz
P5  LCD_RW_WRB/  hiz
P6  LCD_D[0]/SPI_RX  hiz
P7  LCD_D[2]/GP[12]  hiz
P8  DVDDIO  pwr
P9  XF  hiz
P10  LCD_D[7]/GP[17]  hiz
P11  LCD_D[9]/I2S2_FS/GP[19]/SPI_CS0  hiz
P12  MMC0_D1/I2S0_RX/GP[3]  hiz
P13  MMC0_D1/I2S0_RX/GP[3]  hiz
P14  LCD_D[15]/UART_TXD/GP[31]/I2S3_DX  hiz

## Footprint ZCH(S-PBGA-N196) (pad centres in mm)
PLASTIC BALL GRID ARRAY ZCH (S-PBGA-N196) Auto generated by make-symbol-device-package-bsdl.ulp Rev. 36 Source: Data sheet
smd 0.46 x 0.46: A1 -4.225,4.225; A2 -3.575,4.225; A3 -2.925,4.225; A4 -2.275,4.225; A5 -1.625,4.225; A6 -0.975,4.225; A7 -0.325,4.225; A8 0.325,4.225; A9 0.975,4.225; A10 1.625,4.225; A11 2.275,4.225; A12 2.925,4.225; A13 3.575,4.225; A14 4.225,4.225; B1 -4.225,3.575; B2 -3.575,3.575; B3 -2.925,3.575; B4 -2.275,3.575; B5 -1.625,3.575; B6 -0.975,3.575; B7 -0.325,3.575; B8 0.325,3.575; B9 0.975,3.575; B10 1.625,3.575; B11 2.275,3.575; B12 2.925,3.575; B13 3.575,3.575; B14 4.225,3.575; C1 -4.225,2.925; C2 -3.575,2.925; C3 -2.925,2.925; C4 -2.275,2.925; C5 -1.625,2.925; C6 -0.975,2.925; C7 -0.325,2.925; C8 0.325,2.925; C9 0.975,2.925; C10 1.625,2.925; C11 2.275,2.925; C12 2.925,2.925; C13 3.575,2.925; C14 4.225,2.925; D1 -4.225,2.275; D2 -3.575,2.275; D3 -2.925,2.275; D4 -2.275,2.275; D5 -1.625,2.275; D6 -0.975,2.275; D7 -0.325,2.275; D8 0.325,2.275; D9 0.975,2.275; D10 1.625,2.275; D11 2.275,2.275; D12 2.925,2.275; D13 3.575,2.275; D14 4.225,2.275; E1 -4.225,1.625; E2 -3.575,1.625; E3 -2.925,1.625; E4 -2.275,1.625; E5 -1.625,1.625; E6 -0.975,1.625; E7 -0.325,1.625; E8 0.325,1.625; E9 0.975,1.625; E10 1.625,1.625; E11 2.275,1.625; E12 2.925,1.625; E13 3.575,1.625; E14 4.225,1.625; F1 -4.225,0.975; F2 -3.575,0.975; F3 -2.925,0.975; F4 -2.275,0.975; F5 -1.625,0.975; F6 -0.975,0.975; F7 -0.325,0.975; F8 0.325,0.975; F9 0.975,0.975; F10 1.625,0.975; F11 2.275,0.975; F12 2.925,0.975; F13 3.575,0.975; F14 4.225,0.975; G1 -4.225,0.325; G2 -3.575,0.325; G3 -2.925,0.325; G4 -2.275,0.325; G5 -1.625,0.325; G6 -0.975,0.325; G7 -0.325,0.325; G8 0.325,0.325; G9 0.975,0.325; G10 1.625,0.325; G11 2.275,0.325; G12 2.925,0.325; G13 3.575,0.325; G14 4.225,0.325; H1 -4.225,-0.325; H2 -3.575,-0.325; H3 -2.925,-0.325; H4 -2.275,-0.325; H5 -1.625,-0.325; H6 -0.975,-0.325; H7 -0.325,-0.325; H8 0.325,-0.325; H9 0.975,-0.325; H10 1.625,-0.325; H11 2.275,-0.325; H12 2.925,-0.325; H13 3.575,-0.325; H14 4.225,-0.325; J1 -4.225,-0.975; J2 -3.575,-0.975; J3 -2.925,-0.975; J4 -2.275,-0.975; J5 -1.625,-0.975; J6 -0.975,-0.975; J7 -0.325,-0.975; J8 0.325,-0.975; J9 0.975,-0.975; J10 1.625,-0.975; J11 2.275,-0.975; J12 2.925,-0.975; J13 3.575,-0.975; J14 4.225,-0.975; K1 -4.225,-1.625; K2 -3.575,-1.625; K3 -2.925,-1.625; K4 -2.275,-1.625; K5 -1.625,-1.625; K6 -0.975,-1.625; K7 -0.325,-1.625; K8 0.325,-1.625; K9 0.975,-1.625; K10 1.625,-1.625; K11 2.275,-1.625; K12 2.925,-1.625; K13 3.575,-1.625; K14 4.225,-1.625; L1 -4.225,-2.275; L2 -3.575,-2.275; L3 -2.925,-2.275; L4 -2.275,-2.275; L5 -1.625,-2.275; L6 -0.975,-2.275; L7 -0.325,-2.275; L8 0.325,-2.275; L9 0.975,-2.275; L10 1.625,-2.275; L11 2.275,-2.275; L12 2.925,-2.275; L13 3.575,-2.275; L14 4.225,-2.275; M1 -4.225,-2.925; M2 -3.575,-2.925; M3 -2.925,-2.925; M4 -2.275,-2.925; M5 -1.625,-2.925; M6 -0.975,-2.925; M7 -0.325,-2.925; M8 0.325,-2.925; M9 0.975,-2.925; M10 1.625,-2.925; M11 2.275,-2.925; M12 2.925,-2.925; M13 3.575,-2.925; M14 4.225,-2.925; N1 -4.225,-3.575; N2 -3.575,-3.575; N3 -2.925,-3.575; N4 -2.275,-3.575; N5 -1.625,-3.575; N6 -0.975,-3.575; N7 -0.325,-3.575; N8 0.325,-3.575; N9 0.975,-3.575; N10 1.625,-3.575; N11 2.275,-3.575; N12 2.925,-3.575; N13 3.575,-3.575; N14 4.225,-3.575; P1 -4.225,-4.225; P2 -3.575,-4.225; P3 -2.925,-4.225; P4 -2.275,-4.225; P5 -1.625,-4.225; P6 -0.975,-4.225; P7 -0.325,-4.225; P8 0.325,-4.225; P9 0.975,-4.225; P10 1.625,-4.225; P11 2.275,-4.225; P12 2.925,-4.225; P13 3.575,-4.225; P14 4.225,-4.225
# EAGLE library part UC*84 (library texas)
CURRENT-MODE PWM CONTROLLER Source: Data sheet

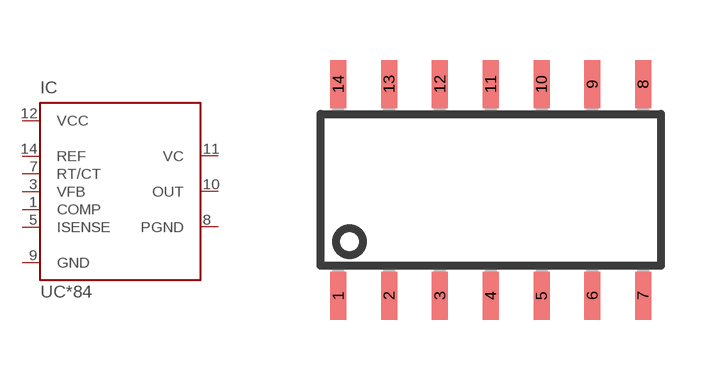
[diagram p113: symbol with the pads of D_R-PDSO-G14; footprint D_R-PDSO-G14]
Designator prefix IC

## UC2842D (MF: TEXAS INSTRUMENTS; MPN: UC2842D8TR; OC_FARNELL: 1413230), UC3842D (MF: TEXAS INSTRUMENTS; MPN: UC3842D; OC_FARNELL: 1652427)  [D_R-PDSO-G14]
1  COMP  pas
3  VFB  in
5  ISENSE  in
7  RT/CT  in
8  PGND  pas
9  GND  pwr
10  OUT  out
11  VC  pas
12  VCC  pwr
14  REF  out

## UC2843D (MF: TEXAS INSTRUMENTS; MPN: UC2843D; OC_FARNELL: 1388056), UC3843D (MF: TEXAS INSTRUMENTS; MPN: UC3843DG4; OC_FARNELL: 1234952)  [D_R-PDSO-G14]
Pads as for D_R-PDSO-G14

## UC2844D (OC_FARNELL: unknown), UC3844D (MF: ON SEMICONDUCTOR; MPN: UC3844BDG; OC_FARNELL: 1228725)  [D_R-PDSO-G14]
Pads as for D_R-PDSO-G14

## UC2845D (MF: TEXAS INSTRUMENTS; MPN: UC2845DG4; OC_FARNELL: 1234881), UC3845D (MF: TEXAS INSTRUMENTS; MPN: UC3845DG4; OC_FARNELL: 1234967)  [D_R-PDSO-G14]
Pads as for D_R-PDSO-G14

## Footprint D_R-PDSO-G14 (pad centres in mm)
PLASTIC SMALL-OUTLINE PACKAGE SO 14 JEDEC MS-012, D Type Source: www.ti.com/.. slvs087l.pdf
smd 0.4 x 1.2: 1 -3.81,-2.65; 2 -2.54,-2.65; 3 -1.27,-2.65; 4 0,-2.65; 5 1.27,-2.65; 6 2.54,-2.65; 7 3.81,-2.65; 8 3.81,2.65; 9 2.54,2.65; 10 1.27,2.65; 11 0,2.65; 12 -1.27,2.65; 13 -2.54,2.65; 14 -3.81,2.65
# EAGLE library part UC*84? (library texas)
CURRENT-MODE PWM CONTROLLER Source: Data sheet

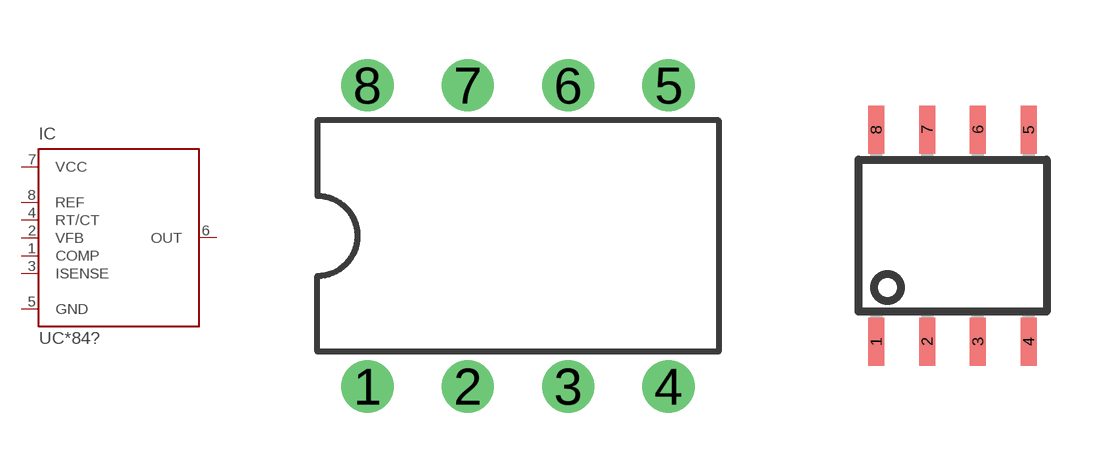
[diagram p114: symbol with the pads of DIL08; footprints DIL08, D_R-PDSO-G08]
Designator prefix IC

## UC2842P (OC_FARNELL: unknown), UC3842P (MF: NTE ELECTRONICS; MPN: NTE7096; OC_FARNELL: 4531085)  [DIL08]
1  COMP  pas
2  VFB  in
3  ISENSE  in
4  RT/CT  in
5  GND  pwr
6  OUT  out
7  VCC  pwr
8  REF  out

## UC2843P (OC_FARNELL: unknown), UC3843P (OC_FARNELL: unknown)  [DIL08]
Pads as for DIL08

## UC2844P (OC_FARNELL: unknown), UC3844P (OC_FARNELL: unknown)  [DIL08]
Pads as for DIL08

## UC2845P (OC_FARNELL: unknown), UC3845P (OC_FARNELL: unknown)  [DIL08]
Pads as for DIL08

## UC2842D (MF: TEXAS INSTRUMENTS; MPN: UC2842D8TR; OC_FARNELL: 1413230), UC3842D (MF: UNITRODE; MPN: UC3842AD8; OC_FARNELL: 1101423)  [D_R-PDSO-G08]
Pads as for DIL08

## UC2843D (MF: TEXAS INSTRUMENTS; MPN: UC2843D8G4; OC_FARNELL: 1207369), UC3843D (MF: UNITRODE; MPN: UC3843D8; OC_FARNELL: 1101424)  [D_R-PDSO-G08]
Pads as for DIL08

## UC2844D (OC_FARNELL: unknown), UC3844D (MF: ON SEMICONDUCTOR; MPN: UC3844BD1G; OC_FARNELL: 1211129)  [D_R-PDSO-G08]
Pads as for DIL08

## UC2845D (OC_FARNELL: unknown), UC3845D (MF: TEXAS INSTRUMENTS; MPN: UC3845D8G4; OC_FARNELL: 1219426)  [D_R-PDSO-G08]
Pads as for DIL08

## Footprint DIL08 (pad centres in mm)
Dual In Line Package
drill 0.813 pad 1.27: 1 -3.81,-3.81; 2 -1.27,-3.81; 3 1.27,-3.81; 4 3.81,-3.81; 5 3.81,3.81; 6 1.27,3.81; 7 -1.27,3.81; 8 -3.81,3.81

## Footprint D_R-PDSO-G08 (pad centres in mm)
PLASTIC SMALL-OUTLINE PACKAGE SO 14 JEDEC MS-012, D Type Source: www.ti.com/.. slvs087l.pdf
smd 0.4 x 1.2: 1 -1.905,-2.65; 2 -0.635,-2.65; 3 0.635,-2.65; 4 1.905,-2.65; 5 1.905,2.65; 6 0.635,2.65; 7 -0.635,2.65; 8 -1.905,2.65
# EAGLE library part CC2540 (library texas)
2.4-GHz Bluetooth® low energy System-on-Chip Auto generated by make-symbol-device-package-bsdl.ulp Rev. 39 Source: cc2540.txt

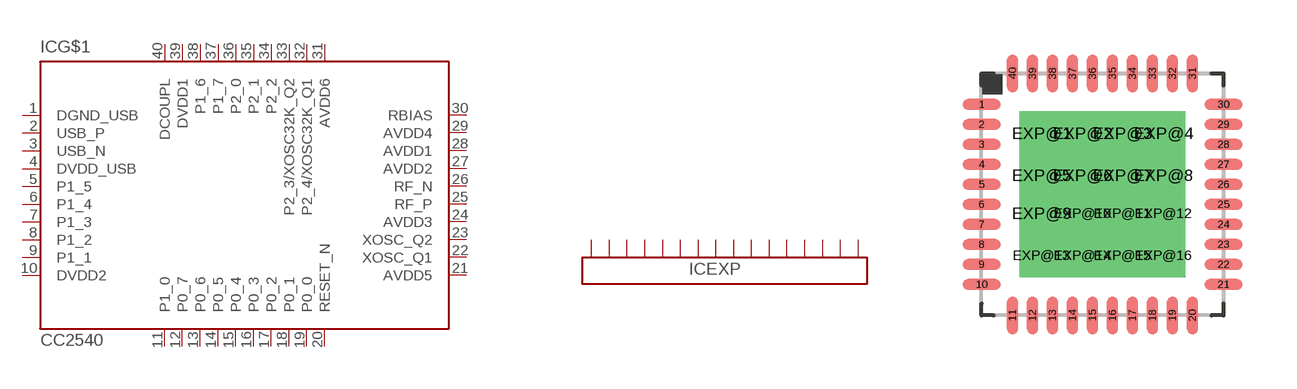
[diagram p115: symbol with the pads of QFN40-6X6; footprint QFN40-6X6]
Designator prefix IC; gates G$1=CC2540 EXP=EXP-16

## CC2540  [QFN40-6X6]
1  G$1:DGND_USB  pwr
2  G$1:USB_P
3  G$1:USB_N
4  G$1:DVDD_USB  pwr
5  G$1:P1_5
6  G$1:P1_4
7  G$1:P1_3
8  G$1:P1_2
9  G$1:P1_1
10  G$1:DVDD2  pwr
11  G$1:P1_0
12  G$1:P0_7
13  G$1:P0_6
14  G$1:P0_5
15  G$1:P0_4
16  G$1:P0_3
17  G$1:P0_2
18  G$1:P0_1
19  G$1:P0_0
20  G$1:RESET_N  in
21  G$1:AVDD5  pwr
22  G$1:XOSC_Q1
23  G$1:XOSC_Q2
24  G$1:AVDD3  pwr
25  G$1:RF_P  in
26  G$1:RF_N  in
27  G$1:AVDD2  pwr
28  G$1:AVDD1  pwr
29  G$1:AVDD4  pwr
30  G$1:RBIAS
31  G$1:AVDD6  pwr
32  G$1:P2_4/XOSC32K_Q1
33  G$1:P2_3/XOSC32K_Q2
34  G$1:P2_2
35  G$1:P2_1
36  G$1:P2_0
37  G$1:P1_7
38  G$1:P1_6
39  G$1:DVDD1  pwr
40  G$1:DCOUPL  pwr
EXP@1  EXP:EXP16  in
EXP@2  EXP:EXP16  in
EXP@3  EXP:EXP16  in
EXP@4  EXP:EXP16  in
EXP@5  EXP:EXP16  in
EXP@6  EXP:EXP16  in
EXP@7  EXP:EXP16  in
EXP@8  EXP:EXP16  in
EXP@9  EXP:EXP16  in
EXP@10  EXP:EXP16  in
EXP@11  EXP:EXP16  in
EXP@12  EXP:EXP16  in
EXP@13  EXP:EXP16  in
EXP@14  EXP:EXP16  in
EXP@15  EXP:EXP16  in
EXP@16  EXP:EXP16  in

## Footprint QFN40-6X6 (pad centres in mm)
RHA (S-PQFP-N40) 6 x 6 mm Source: http://focus.ti.com/lit/ds/symlink/tps65020.pdf
smd 0.95 x 0.28: 1 -3.025,2.25; 2 -3.025,1.75; 3 -3.025,1.25; 4 -3.025,0.75; 5 -3.025,0.25; 6 -3.025,-0.25; 7 -3.025,-0.75; 8 -3.025,-1.25; 9 -3.025,-1.75; 10 -3.025,-2.25; 21 3.025,-2.25; 22 3.025,-1.75; 23 3.025,-1.25; 24 3.025,-0.75; 25 3.025,-0.25; 26 3.025,0.25; 27 3.025,0.75; 28 3.025,1.25; 29 3.025,1.75; 30 3.025,2.25
smd 0.28 x 0.95: 11 -2.25,-3.025; 12 -1.75,-3.025; 13 -1.25,-3.025; 14 -0.75,-3.025; 15 -0.25,-3.025; 16 0.25,-3.025; 17 0.75,-3.025; 18 1.25,-3.025; 19 1.75,-3.025; 20 2.25,-3.025; 31 2.25,3.025; 32 1.75,3.025; 33 1.25,3.025; 34 0.75,3.025; 35 0.25,3.025; 36 -0.25,3.025; 37 -0.75,3.025; 38 -1.25,3.025; 39 -1.75,3.025; 40 -2.25,3.025
drill 0.3 pad 1.1 square: EXP@1 -1.525,1.525; EXP@2 -0.5,1.525; EXP@3 0.5,1.525; EXP@4 1.525,1.525; EXP@5 -1.525,0.475; EXP@6 -0.5,0.475; EXP@7 0.5,0.475; EXP@8 1.525,0.475; EXP@9 -1.525,-0.475; EXP@10 -0.5,-0.475; EXP@11 0.5,-0.475; EXP@12 1.525,-0.475; EXP@13 -1.525,-1.525; EXP@14 -0.5,-1.525; EXP@15 0.5,-1.525; EXP@16 1.525,-1.525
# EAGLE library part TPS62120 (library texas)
15V, 75mA High Efficient Buck Converter Source: tps62120.pdf (www.ti.com)

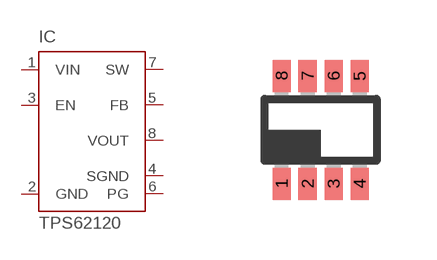
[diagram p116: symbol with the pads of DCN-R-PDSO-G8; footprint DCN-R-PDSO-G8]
Designator prefix IC

## TPS62120  [DCN-R-PDSO-G8]
1  VIN  in
2  GND  pwr
3  EN  in
4  SGND  pas
5  FB  in
6  PG  pas
7  SW  out
8  VOUT  out

## Footprint DCN-R-PDSO-G8 (pad centres in mm)
DCN (R-PDSO-G8) PLASTIC SMALL-OUTLINE PACKAGE (DIE DOWN) Source: tps62120.pdf (www.ti.com)
smd 0.45 x 0.8: 1 -0.975,-1.35; 2 -0.325,-1.35; 3 0.325,-1.35; 4 0.975,-1.35; 5 0.975,1.35; 6 0.325,1.35; 7 -0.325,1.35; 8 -0.975,1.35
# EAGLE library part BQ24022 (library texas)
SINGLE-CHIP, LI-ION AND LI-POL CHARGER IC WITH AUTONOMOUS USB-PORT AND AC-ADAPTER SUPPLY MANAGEMENT (bqTINY™-II) Source: bq24022.pdf (www.ti.com)

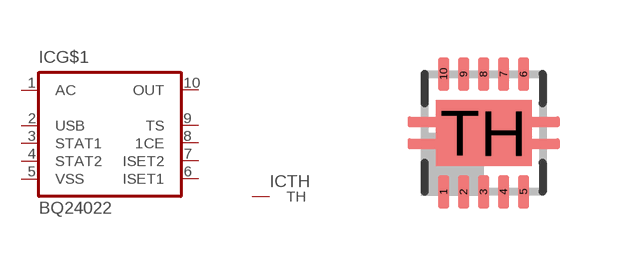
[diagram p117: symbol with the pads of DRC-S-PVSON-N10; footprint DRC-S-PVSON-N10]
Designator prefix IC; gates G$1=BQ24022 TH=THERMAL

## BQ24022  [DRC-S-PVSON-N10]
1  G$1:AC  in
2  G$1:USB
3  G$1:STAT1
4  G$1:STAT2
5  G$1:VSS  pwr
6  G$1:ISET1  in
7  G$1:ISET2  in
8  G$1:1CE  in
9  G$1:TS  in
10  G$1:OUT  out
TH  TH:TH  pas

## Footprint DRC-S-PVSON-N10 (pad centres in mm)
DRK (S-PDSO-N10) Source: www.ti.com .. bq27010.pdf changed 2011-11-09
smd 0.28 x 0.85: 1 -1,-1.475; 2 -0.5,-1.475; 3 0,-1.475; 4 0.5,-1.475; 5 1,-1.475; 6 1,1.475; 7 0.5,1.475; 8 0,1.475; 9 -0.5,1.475; 10 -1,1.475
smd 2.4 x 1.65: TH 0,0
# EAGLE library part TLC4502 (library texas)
FAMILY OF SELF-CALIBRATING (Self-Cal TM) PRECISION CMOS RAIL-TO-RAIL OUTPUT OPERATIONAL AMPLIFIERS Source: Data sheet

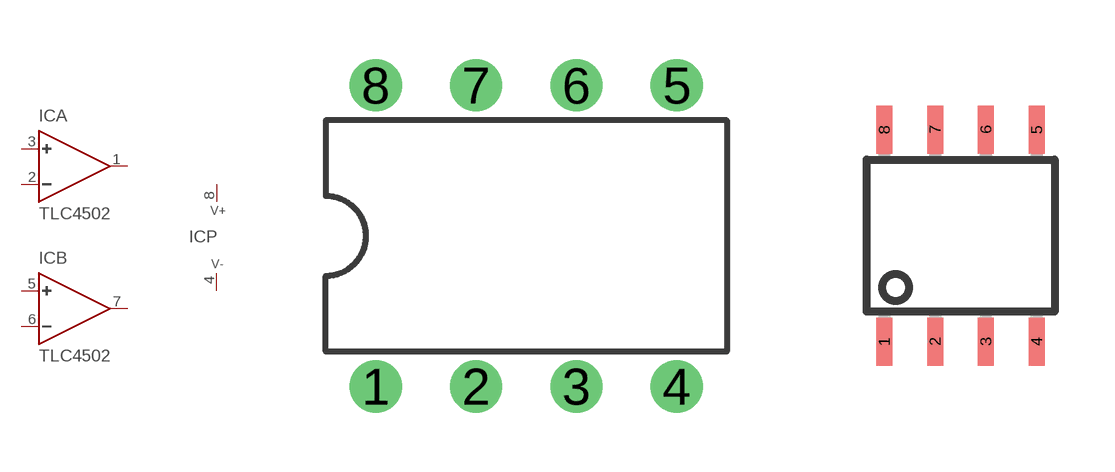
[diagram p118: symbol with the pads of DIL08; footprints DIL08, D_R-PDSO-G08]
Designator prefix IC; gates A=TLC450X B=TLC450X P=TLC450P

## TLC4502JG  [DIL08]
1  A:OUT  out
2  A:-  in
3  A:+  in
4  P:V-  pwr
5  B:+  in
6  B:-  in
7  B:OUT  out
8  P:V+  pwr

## TLC4502D  [D_R-PDSO-G08]
Pads as for DIL08

## Footprint DIL08 (pad centres in mm)
Dual In Line Package
drill 0.813 pad 1.27: 1 -3.81,-3.81; 2 -1.27,-3.81; 3 1.27,-3.81; 4 3.81,-3.81; 5 3.81,3.81; 6 1.27,3.81; 7 -1.27,3.81; 8 -3.81,3.81

## Footprint D_R-PDSO-G08 (pad centres in mm)
PLASTIC SMALL-OUTLINE PACKAGE SO 14 JEDEC MS-012, D Type Source: www.ti.com/.. slvs087l.pdf
smd 0.4 x 1.2: 1 -1.905,-2.65; 2 -0.635,-2.65; 3 0.635,-2.65; 4 1.905,-2.65; 5 1.905,2.65; 6 0.635,2.65; 7 -0.635,2.65; 8 -1.905,2.65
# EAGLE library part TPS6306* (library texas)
HIGH INPUT VOLTAGE BUCK-BOOST CONVERTER WITH 2A SWITCH CURRENT Source: http://www.ti.com/lit/ds/symlink/tps63060.pdf

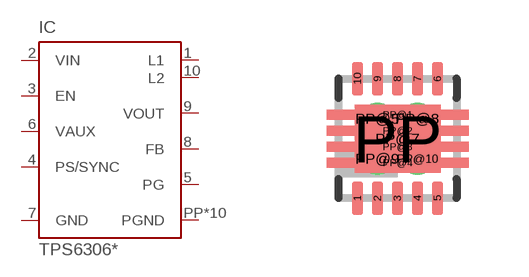
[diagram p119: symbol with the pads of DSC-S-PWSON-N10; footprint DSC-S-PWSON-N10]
Designator prefix IC

## TPS63060, TPS63061  [DSC-S-PWSON-N10]
1  L1  in
2  VIN  in
3  EN  in
4  PS/SYNC  in
5  PG  out
6  VAUX  pwr
7  GND  in
8  FB  in
9  VOUT  out
10  L2  in
PP  PGND  pwr
PP@1  PGND  pwr
PP@2  PGND  pwr
PP@3  PGND  pwr
PP@4  PGND  pwr
PP@5  PGND  pwr
PP@7  PGND  pwr
PP@8  PGND  pwr
PP@9  PGND  pwr
PP@10  PGND  pwr

## Footprint DSC-S-PWSON-N10 (pad centres in mm)
DSC (S-PWSON-N10) Source: http://www.ti.com/lit/ds/symlink/tps63060.pdf
smd 0.28 x 0.85: 1 -1,-1.488; 2 -0.5,-1.488; 3 0,-1.488; 4 0.5,-1.488; 5 1,-1.488; 6 1,1.5; 7 0.5,1.5; 8 0,1.5; 9 -0.5,1.5; 10 -1,1.5
smd 2.15 x 1.7: PP 0,0
smd 3.55 x 0.25: PP@1 0,0.6; PP@2 0,0.2; PP@3 0,-0.2; PP@4 0,-0.6
drill 0.3 pad 0.4: PP@5 -0.5,0.5; PP@7 0,0; PP@8 0.5,0.5; PP@9 -0.5,-0.5; PP@10 0.5,-0.5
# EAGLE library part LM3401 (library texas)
Hysteretic PFET Controller for High Power LED Drive APPLICATIONS: LED Driver Battery Charger Source: http://www.ti.com/lit/ds/symlink/lm3401.pdf

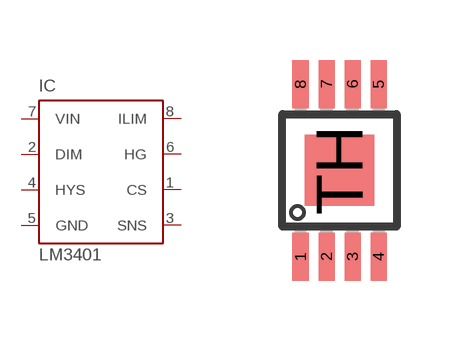
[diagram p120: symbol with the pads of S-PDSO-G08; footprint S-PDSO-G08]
Designator prefix IC

## LM3401  [S-PDSO-G08]
1  CS  in
2  DIM  pas
3  SNS  in
4  HYS  in
5  GND  pwr
6  HG  out
7  VIN  in
8  ILIM  in

## Footprint S-PDSO-G08 (pad centres in mm)
DGN (S-PDSO-G8) PowerPAD (TM) Plastic Small-Outline Package Source: http://focus.ti.com/lit/ds/symlink/ths4211.pdf
smd 0.4 x 1.2: 1 -0.975,-2.157; 2 -0.325,-2.157; 3 0.325,-2.157; 4 0.975,-2.157; 5 0.975,2.157; 6 0.325,2.157; 7 -0.325,2.157; 8 -0.975,2.157
smd 1.73 x 1.78: TH 0,0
